# LEF file generated by Abstract Generator version 5.5.12 on Aug 29 14:42:19 2003
#
# Contains LEF for bin IO.
# Options:   [ ] Antenna
#            [x] Geometry
#            [ ] Technology

VERSION 5.4 ;
NAMESCASESENSITIVE ON ;
BUSBITCHARS "[]" ;
DIVIDERCHAR "/" ;
UNITS
  DATABASE MICRONS 1000 ;
END UNITS

USEMINSPACING OBS ON ;
USEMINSPACING PIN OFF ;
CLEARANCEMEASURE EUCLIDEAN ;


MANUFACTURINGGRID 0.001 ;




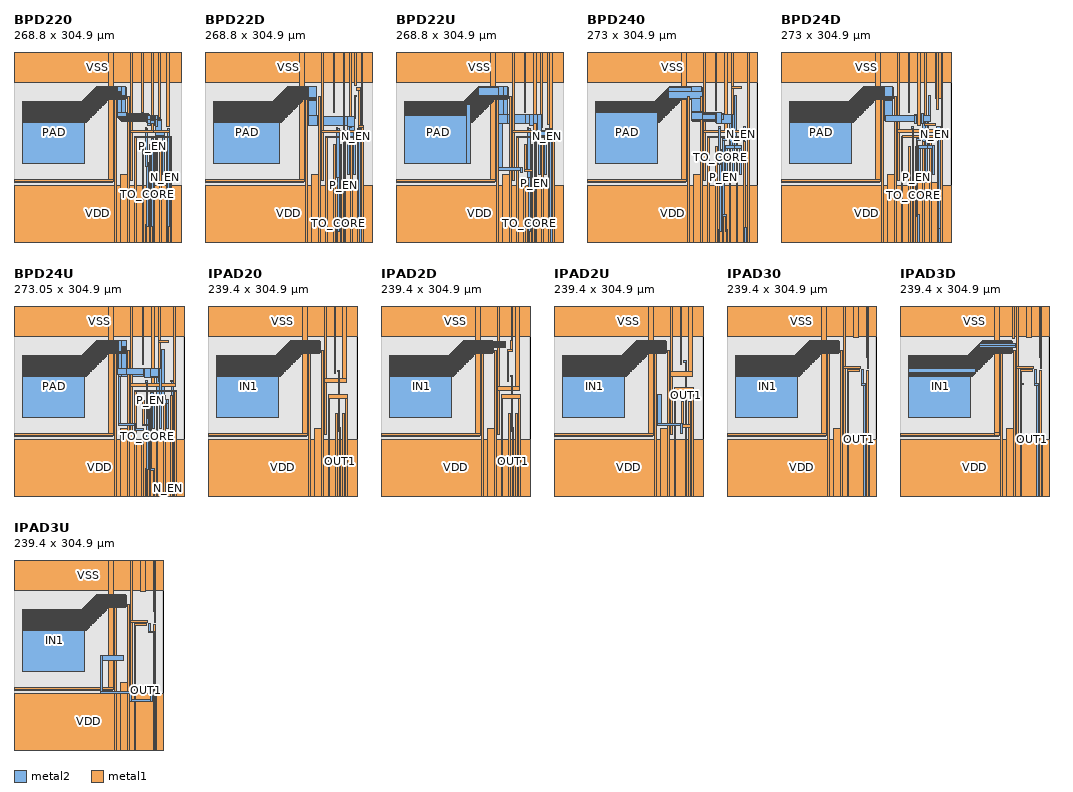
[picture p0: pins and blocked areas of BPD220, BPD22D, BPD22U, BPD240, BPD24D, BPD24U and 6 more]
MACRO BPD220
  CLASS  PAD ;
  FOREIGN BPD220 0.000 0.000 ;
  ORIGIN 0.000 0.000 ;
  SIZE 268.800 BY 304.900 ;
  SYMMETRY X Y R90  ;
  SITE IO ;
  PIN N_EN
    DIRECTION INPUT ;
    PORT
      LAYER metal2 ;
        RECT 244.450 0.000 246.950 27.700 ;
        RECT 246.250 25.200 248.750 182.250 ;
    END
  END N_EN
  PIN TO_CORE
    DIRECTION OUTPUT ;
    PORT
      LAYER metal2 ;
        RECT 211.300 121.300 214.100 181.400 ;
        RECT 212.650 25.200 215.150 128.200 ;
        RECT 210.850 0.000 213.350 27.700 ;
        RECT 210.250 179.000 212.750 183.950 ;
    END
  END TO_CORE
  PIN VSS
    DIRECTION INOUT ;
    USE GROUND ;
    SHAPE ABUTMENT ;
    PORT
      LAYER metal2 ;
        RECT 0.000 256.200 268.800 304.900 ;
      LAYER metal1 ;
        RECT 0.750 95.850 158.334 100.500 ;
        RECT 0.000 256.200 268.800 304.900 ;
        RECT 186.750 175.100 249.900 178.250 ;
        RECT 245.250 184.850 248.800 304.900 ;
        RECT 231.450 183.800 234.950 304.900 ;
        RECT 220.550 175.100 224.250 304.900 ;
        RECT 186.750 175.100 224.250 178.500 ;
        RECT 205.100 208.600 207.600 304.900 ;
        RECT 186.750 99.300 190.950 304.900 ;
        RECT 186.850 99.200 190.850 304.900 ;
        RECT 151.350 97.066 159.550 304.900 ;
        RECT 0.750 96.850 159.334 100.500 ;
    END
  END VSS
  PIN PAD
    DIRECTION INOUT ;
    PORT
      LAYER metal2 ;
        RECT 14.751 125.550 112.998 225.550 ;
        RECT 14.650 125.651 112.998 225.550 ;
        RECT 112.998 229.147 179.547 229.799 ;
        RECT 14.650 126.352 113.800 225.550 ;
        RECT 227.850 170.550 241.800 176.000 ;
        RECT 237.600 107.600 241.800 176.000 ;
        RECT 227.850 170.550 236.350 196.450 ;
        RECT 169.500 196.400 235.800 197.000 ;
        RECT 227.900 107.600 230.800 202.000 ;
        RECT 227.850 107.650 230.800 202.000 ;
        RECT 166.500 199.400 231.800 201.000 ;
        RECT 227.399 185.800 230.150 202.650 ;
        RECT 167.500 198.400 232.800 200.000 ;
        RECT 226.150 186.800 230.150 202.650 ;
        RECT 168.500 197.400 233.800 199.000 ;
        RECT 214.122 190.950 230.150 202.650 ;
        RECT 214.250 190.822 219.500 202.650 ;
        RECT 214.650 186.300 219.500 202.650 ;
        RECT 165.500 200.400 217.650 203.550 ;
        RECT 165.500 200.400 216.650 204.550 ;
        RECT 165.500 200.400 215.650 205.550 ;
        RECT 165.500 200.400 214.650 206.550 ;
        RECT 169.500 196.400 234.800 198.000 ;
        RECT 213.122 191.950 214.250 206.950 ;
        RECT 170.500 195.400 236.350 196.450 ;
        RECT 172.950 192.950 214.250 206.950 ;
        RECT 132.048 229.800 180.200 248.497 ;
        RECT 165.500 200.400 180.200 207.550 ;
        RECT 132.150 229.147 179.547 249.150 ;
        RECT 112.749 228.600 179.200 229.550 ;
        RECT 165.500 200.400 179.200 249.150 ;
        RECT 172.500 193.400 179.200 249.150 ;
        RECT 171.500 194.400 236.350 196.450 ;
        RECT 112.749 228.452 152.150 229.550 ;
        RECT 111.749 227.452 151.150 228.550 ;
        RECT 110.749 226.452 150.150 227.550 ;
        RECT 109.749 225.452 149.150 226.550 ;
        RECT 14.650 224.452 148.150 225.550 ;
        RECT 13.800 223.452 147.150 224.700 ;
        RECT 13.800 222.452 146.150 224.700 ;
        RECT 13.800 221.452 145.150 224.700 ;
        RECT 13.800 220.452 144.150 224.700 ;
        RECT 13.800 219.452 143.150 224.700 ;
        RECT 13.800 218.452 142.150 224.700 ;
        RECT 13.800 217.452 141.150 224.700 ;
        RECT 13.800 216.452 140.150 224.700 ;
        RECT 13.800 215.452 139.150 224.700 ;
        RECT 13.800 214.452 138.150 224.700 ;
        RECT 13.800 213.452 137.150 224.700 ;
        RECT 13.800 212.452 136.150 224.700 ;
        RECT 13.800 211.452 135.150 224.700 ;
        RECT 13.800 210.452 134.150 224.700 ;
        RECT 13.800 209.452 133.150 224.700 ;
        RECT 13.800 208.452 132.150 224.700 ;
        RECT 132.048 229.147 179.547 248.849 ;
        RECT 13.800 208.350 132.048 224.700 ;
        RECT 131.048 229.800 180.200 247.849 ;
        RECT 13.800 207.350 131.048 224.700 ;
        RECT 130.048 229.800 180.200 246.849 ;
        RECT 13.800 206.350 130.048 224.700 ;
        RECT 129.048 229.800 180.200 245.849 ;
        RECT 13.800 205.350 129.048 224.700 ;
        RECT 128.048 229.800 180.200 244.849 ;
        RECT 13.800 204.350 128.048 224.700 ;
        RECT 127.048 229.800 180.200 243.849 ;
        RECT 13.800 203.350 127.048 224.700 ;
        RECT 126.048 229.800 180.200 242.849 ;
        RECT 13.800 202.350 126.048 224.700 ;
        RECT 125.048 229.800 180.200 241.849 ;
        RECT 13.800 201.350 125.048 224.700 ;
        RECT 125.032 229.800 180.200 241.833 ;
        RECT 124.800 229.800 180.200 241.601 ;
        RECT 13.800 201.118 124.800 224.700 ;
        RECT 123.800 229.800 180.200 240.601 ;
        RECT 13.800 200.118 123.800 224.700 ;
        RECT 122.800 229.800 180.200 239.601 ;
        RECT 13.800 199.118 122.800 224.700 ;
        RECT 121.800 229.800 180.200 238.601 ;
        RECT 13.800 198.118 121.800 224.700 ;
        RECT 120.800 229.800 180.200 237.601 ;
        RECT 13.800 197.118 120.800 224.700 ;
        RECT 119.800 229.800 180.200 236.601 ;
        RECT 13.800 196.118 119.800 224.700 ;
        RECT 118.800 229.800 180.200 235.601 ;
        RECT 13.800 195.118 118.800 224.700 ;
        RECT 117.800 229.800 180.200 234.601 ;
        RECT 13.800 194.118 117.800 224.700 ;
        RECT 116.800 229.800 180.200 233.601 ;
        RECT 13.800 193.118 116.800 224.700 ;
        RECT 115.800 229.800 180.200 232.601 ;
        RECT 13.800 192.118 115.800 224.700 ;
        RECT 114.800 229.800 180.200 231.601 ;
        RECT 13.800 191.118 114.800 224.700 ;
        RECT 113.800 229.800 180.200 230.601 ;
        RECT 13.800 126.501 113.800 224.700 ;
    END
  END PAD
  PIN VDD
    DIRECTION INOUT ;
    USE POWER ;
    SHAPE ABUTMENT ;
    PORT
      LAYER metal1 ;
        RECT 161.150 0.000 164.197 233.850 ;
        RECT 0.000 0.000 268.800 90.700 ;
        RECT 250.550 0.000 253.050 169.600 ;
        RECT 245.000 0.000 247.500 161.100 ;
        RECT 233.600 0.000 236.100 161.100 ;
        RECT 222.200 0.000 224.700 161.100 ;
        RECT 216.700 0.000 219.200 155.850 ;
        RECT 205.900 0.000 208.400 155.850 ;
        RECT 193.450 0.000 195.950 169.600 ;
        RECT 182.053 0.000 185.150 233.900 ;
        RECT 182.053 0.000 184.800 234.250 ;
        RECT 181.650 0.000 185.150 233.847 ;
        RECT 170.652 0.000 185.150 108.750 ;
        RECT 170.150 0.000 185.150 108.248 ;
        RECT 161.150 0.000 164.650 233.797 ;
        RECT 161.550 0.000 164.197 234.250 ;
    END
    PORT
      CLASS CORE ;
      LAYER metal1 ;
        RECT 193.450 167.100 253.050 169.600 ;
    END
  END VDD
  PIN P_EN
    DIRECTION INPUT ;
    PORT
      LAYER metal2 ;
        RECT 221.050 25.200 223.550 165.600 ;
        RECT 223.450 0.000 225.950 27.700 ;
        RECT 221.050 163.100 224.000 165.600 ;
    END
  END P_EN
  OBS 
      LAYER metal2 ;
        RECT 0.850 228.500 106.799 253.250 ;
        RECT 167.600 111.198 167.702 192.450 ;
        RECT 167.600 111.700 178.700 190.000 ;
        RECT 167.600 111.700 170.000 190.450 ;
        RECT 167.600 111.700 169.550 191.450 ;
        RECT 167.600 111.700 168.550 192.450 ;
        RECT 183.150 237.200 183.800 253.250 ;
        RECT 188.100 93.650 190.500 96.250 ;
        RECT 193.900 210.500 202.150 253.250 ;
        RECT 165.950 102.550 168.950 108.552 ;
        RECT 198.900 93.650 202.950 190.000 ;
        RECT 165.950 104.750 205.800 108.300 ;
        RECT 166.150 102.450 168.950 108.552 ;
        RECT 166.150 102.350 168.850 108.652 ;
        RECT 0.850 104.850 168.650 108.950 ;
        RECT 0.850 104.850 168.600 109.000 ;
        RECT 0.850 104.850 167.600 109.550 ;
        RECT 0.850 104.850 150.800 110.101 ;
        RECT 0.850 104.850 149.800 122.548 ;
        RECT 0.850 103.450 148.400 122.600 ;
        RECT 115.948 104.850 149.298 123.050 ;
        RECT 115.948 103.450 148.400 123.402 ;
        RECT 198.900 157.900 208.300 164.150 ;
        RECT 198.900 158.800 208.350 164.150 ;
        RECT 198.900 104.750 205.800 190.000 ;
        RECT 195.700 162.150 205.800 190.000 ;
        RECT 193.900 181.450 207.300 190.000 ;
        RECT 193.900 186.900 211.700 187.872 ;
        RECT 193.900 186.900 211.300 188.000 ;
        RECT 116.750 103.450 148.400 188.168 ;
        RECT 193.900 186.900 211.172 189.000 ;
        RECT 117.750 103.450 148.400 189.168 ;
        RECT 193.900 186.900 210.172 190.000 ;
        RECT 118.750 103.450 148.400 190.168 ;
        RECT 119.750 103.450 148.400 191.168 ;
        RECT 120.750 103.450 148.400 192.168 ;
        RECT 121.750 103.450 148.400 193.168 ;
        RECT 122.750 103.450 148.400 194.168 ;
        RECT 123.750 103.450 148.400 195.168 ;
        RECT 124.750 103.450 148.400 196.168 ;
        RECT 125.750 103.450 148.400 197.168 ;
        RECT 126.750 103.450 148.400 198.168 ;
        RECT 127.750 103.450 148.400 198.400 ;
        RECT 127.998 103.450 148.400 199.400 ;
        RECT 128.998 103.450 148.400 200.400 ;
        RECT 129.998 103.450 148.400 201.400 ;
        RECT 130.998 103.450 148.400 202.400 ;
        RECT 131.998 103.450 148.400 203.400 ;
        RECT 132.998 103.450 148.400 204.400 ;
        RECT 133.998 103.450 148.400 205.400 ;
        RECT 134.998 103.450 148.400 205.502 ;
        RECT 135.100 103.450 148.400 206.502 ;
        RECT 136.100 103.450 148.400 207.502 ;
        RECT 137.100 103.450 148.400 208.502 ;
        RECT 138.100 103.450 148.400 209.502 ;
        RECT 139.100 103.450 148.400 210.502 ;
        RECT 140.100 103.450 148.400 211.502 ;
        RECT 141.100 103.450 148.400 212.502 ;
        RECT 142.100 103.450 148.400 213.502 ;
        RECT 143.100 103.450 148.400 214.502 ;
        RECT 144.100 103.450 148.400 215.502 ;
        RECT 145.100 103.450 148.400 216.502 ;
        RECT 146.100 103.450 148.400 217.502 ;
        RECT 147.100 103.450 148.400 218.502 ;
        RECT 148.100 103.450 148.400 219.502 ;
        RECT 210.550 210.500 217.600 253.250 ;
        RECT 220.550 207.800 224.250 253.250 ;
        RECT 227.200 210.500 228.500 253.250 ;
        RECT 227.650 93.650 230.650 104.650 ;
        RECT 231.450 207.800 234.950 253.250 ;
        RECT 239.050 93.650 242.050 104.650 ;
        RECT 237.900 210.500 242.300 253.250 ;
        RECT 251.750 210.500 267.950 253.250 ;
      LAYER metal1 ;
        RECT 0.750 106.650 149.350 249.448 ;
        RECT 0.750 103.250 148.600 253.450 ;
        RECT 166.150 110.250 179.130 135.394 ;
        RECT 166.150 102.350 168.650 135.394 ;
        RECT 166.157 111.270 180.150 135.413 ;
        RECT 166.238 111.270 180.150 135.448 ;
        RECT 166.238 110.468 179.348 135.532 ;
        RECT 166.956 110.468 179.348 136.250 ;
        RECT 166.750 139.250 178.900 253.450 ;
        RECT 167.400 110.250 178.900 253.450 ;
        RECT 166.150 139.850 178.900 253.450 ;
        RECT 166.150 139.906 179.900 253.450 ;
        RECT 166.150 140.156 180.150 253.450 ;
        RECT 162.300 237.000 184.000 253.450 ;
        RECT 187.900 93.450 190.700 96.450 ;
        RECT 193.700 181.250 217.800 205.850 ;
        RECT 205.600 181.250 208.300 206.000 ;
        RECT 193.700 181.250 202.600 212.700 ;
        RECT 193.700 181.250 202.550 231.700 ;
        RECT 193.700 229.200 202.600 231.700 ;
        RECT 210.250 183.800 218.250 249.300 ;
        RECT 210.250 181.250 217.800 250.100 ;
        RECT 193.700 181.250 202.350 253.450 ;
        RECT 210.350 181.250 217.800 253.450 ;
        RECT 198.700 93.450 203.150 164.650 ;
        RECT 198.500 120.950 203.150 164.650 ;
        RECT 198.500 157.900 208.300 164.650 ;
        RECT 211.150 93.450 213.950 164.350 ;
        RECT 210.350 157.650 213.950 164.350 ;
        RECT 198.500 158.600 219.450 164.350 ;
        RECT 227.450 93.450 230.850 164.350 ;
        RECT 238.850 93.450 242.250 164.350 ;
        RECT 198.500 163.850 247.800 164.350 ;
        RECT 198.500 158.600 212.850 164.650 ;
        RECT 221.500 163.100 227.500 165.600 ;
        RECT 227.000 181.250 268.050 182.100 ;
        RECT 230.000 179.750 248.750 182.250 ;
        RECT 227.000 181.250 248.750 182.250 ;
        RECT 226.550 183.800 229.050 249.300 ;
        RECT 227.000 181.250 228.700 253.450 ;
        RECT 237.700 179.750 242.500 253.450 ;
        RECT 251.550 181.250 268.050 253.450 ;
        RECT 255.800 93.450 268.050 164.350 ;
      LAYER via1 ;
        RECT 0.750 0.750 268.050 304.150 ;
  END 
END BPD220


MACRO BPD22D
  CLASS  PAD ;
  FOREIGN BPD22D 0.000 0.000 ;
  ORIGIN 0.000 0.000 ;
  SIZE 268.800 BY 304.900 ;
  SYMMETRY X Y R90  ;
  SITE IO ;
  PIN N_EN
    DIRECTION INPUT ;
    PORT
      LAYER metal2 ;
        RECT 246.750 29.400 249.250 182.250 ;
        RECT 248.650 0.000 251.150 31.900 ;
        RECT 244.000 179.750 249.250 182.250 ;
    END
  END N_EN
  PIN TO_CORE
    DIRECTION OUTPUT ;
    PORT
      LAYER metal2 ;
        RECT 211.800 104.100 215.650 181.400 ;
        RECT 213.150 16.800 215.650 181.400 ;
        RECT 210.850 0.000 213.350 19.300 ;
        RECT 210.750 179.000 213.250 183.950 ;
    END
  END TO_CORE
  PIN VSS
    DIRECTION INOUT ;
    USE GROUND ;
    SHAPE ABUTMENT ;
    PORT
      LAYER metal2 ;
        RECT 0.000 256.200 268.800 304.900 ;
      LAYER metal1 ;
        RECT 0.750 95.850 158.334 100.500 ;
        RECT 0.000 256.200 268.800 304.900 ;
        RECT 250.600 188.000 253.450 304.900 ;
        RECT 186.750 175.100 244.600 178.150 ;
        RECT 240.000 250.650 242.600 304.900 ;
        RECT 232.350 183.800 235.100 304.900 ;
        RECT 221.550 175.100 224.300 304.900 ;
        RECT 186.750 175.100 224.300 178.600 ;
        RECT 205.600 208.600 208.100 304.900 ;
        RECT 186.750 99.300 190.950 304.900 ;
        RECT 186.850 99.200 190.850 304.900 ;
        RECT 151.350 97.066 159.550 304.900 ;
        RECT 0.750 96.850 159.334 100.500 ;
    END
  END VSS
  PIN PAD
    DIRECTION INOUT ;
    PORT
      LAYER metal2 ;
        RECT 113.749 228.600 179.700 230.550 ;
        RECT 114.749 228.600 179.700 231.550 ;
        RECT 115.749 228.600 179.700 232.550 ;
        RECT 116.749 228.600 179.700 233.550 ;
        RECT 117.749 228.600 179.700 234.550 ;
        RECT 239.800 232.950 243.350 235.450 ;
        RECT 239.800 197.950 242.300 235.450 ;
        RECT 238.700 107.600 242.300 174.800 ;
        RECT 167.700 186.651 240.200 202.150 ;
        RECT 168.001 186.350 240.200 202.150 ;
        RECT 228.350 169.450 240.200 202.150 ;
        RECT 228.350 107.650 232.050 202.150 ;
        RECT 228.400 107.600 232.050 202.150 ;
        RECT 227.999 185.350 240.200 202.150 ;
        RECT 166.700 187.651 181.700 202.551 ;
        RECT 166.700 187.651 180.700 203.551 ;
        RECT 132.150 228.600 179.700 249.150 ;
        RECT 165.149 227.600 179.700 249.150 ;
        RECT 166.149 226.600 179.700 249.150 ;
        RECT 166.700 187.651 179.700 249.150 ;
        RECT 112.749 227.952 158.150 229.550 ;
        RECT 111.749 226.952 157.150 228.550 ;
        RECT 110.749 225.952 156.150 227.550 ;
        RECT 109.749 224.952 155.150 226.550 ;
        RECT 14.650 223.952 154.150 225.550 ;
        RECT 13.800 222.952 153.150 224.700 ;
        RECT 13.800 221.952 152.150 224.700 ;
        RECT 13.800 220.952 151.150 224.700 ;
        RECT 13.800 219.952 150.150 224.700 ;
        RECT 13.800 218.952 149.150 224.700 ;
        RECT 13.800 217.952 148.150 224.700 ;
        RECT 13.800 216.952 147.150 224.700 ;
        RECT 13.800 215.952 146.150 224.700 ;
        RECT 13.800 214.952 145.150 224.700 ;
        RECT 13.800 213.952 144.150 224.700 ;
        RECT 13.800 212.952 143.150 224.700 ;
        RECT 13.800 211.952 142.150 224.700 ;
        RECT 13.800 210.952 141.150 224.700 ;
        RECT 13.800 209.952 140.150 224.700 ;
        RECT 13.800 208.952 139.150 224.700 ;
        RECT 13.800 207.952 138.150 224.700 ;
        RECT 13.800 206.952 137.150 224.700 ;
        RECT 13.800 205.952 136.150 224.700 ;
        RECT 13.800 204.952 135.150 224.700 ;
        RECT 13.800 203.952 134.150 224.700 ;
        RECT 13.800 202.952 133.150 224.700 ;
        RECT 13.800 201.952 132.150 224.700 ;
        RECT 131.548 228.600 179.700 248.349 ;
        RECT 13.800 201.350 131.548 224.700 ;
        RECT 131.532 228.600 179.700 248.333 ;
        RECT 131.300 228.600 179.700 248.101 ;
        RECT 13.800 201.118 131.300 224.700 ;
        RECT 130.300 228.600 179.700 247.101 ;
        RECT 13.800 200.118 130.300 224.700 ;
        RECT 129.300 228.600 179.700 246.101 ;
        RECT 13.800 199.118 129.300 224.700 ;
        RECT 128.300 228.600 179.700 245.101 ;
        RECT 13.800 198.118 128.300 224.700 ;
        RECT 127.300 228.600 179.700 244.101 ;
        RECT 13.800 197.118 127.300 224.700 ;
        RECT 126.300 228.600 179.700 243.101 ;
        RECT 13.800 196.118 126.300 224.700 ;
        RECT 125.300 228.600 179.700 242.101 ;
        RECT 13.800 195.118 125.300 224.700 ;
        RECT 124.300 228.600 179.700 241.101 ;
        RECT 13.800 194.118 124.300 224.700 ;
        RECT 123.300 228.600 179.700 240.101 ;
        RECT 13.800 193.118 123.300 224.700 ;
        RECT 122.300 228.600 179.700 239.101 ;
        RECT 13.800 192.118 122.300 224.700 ;
        RECT 121.300 228.600 179.700 238.101 ;
        RECT 13.800 191.118 121.300 224.700 ;
        RECT 120.300 228.600 179.700 237.101 ;
        RECT 13.800 126.501 120.300 224.700 ;
        RECT 14.650 126.352 120.300 225.550 ;
        RECT 119.498 228.600 179.700 236.299 ;
        RECT 14.650 125.651 119.498 225.550 ;
        RECT 14.751 125.550 119.498 225.550 ;
        RECT 118.749 228.600 179.700 235.550 ;
    END
  END PAD
  PIN VDD
    DIRECTION INOUT ;
    USE POWER ;
    SHAPE ABUTMENT ;
    PORT
      LAYER metal1 ;
        RECT 161.150 0.000 164.197 233.850 ;
        RECT 0.000 0.000 268.800 90.700 ;
        RECT 246.350 183.750 253.550 186.300 ;
        RECT 251.050 0.000 253.550 186.300 ;
        RECT 193.950 167.100 253.550 169.600 ;
        RECT 246.350 183.750 248.850 248.550 ;
        RECT 245.500 0.000 248.000 161.100 ;
        RECT 234.100 0.000 236.600 161.100 ;
        RECT 222.700 0.000 225.200 161.100 ;
        RECT 217.200 0.000 219.700 155.850 ;
        RECT 206.400 0.000 208.900 155.850 ;
        RECT 193.950 0.000 196.450 169.600 ;
        RECT 182.053 0.000 185.150 233.900 ;
        RECT 182.053 0.000 184.800 234.250 ;
        RECT 181.650 0.000 185.150 233.847 ;
        RECT 170.652 0.000 185.150 108.750 ;
        RECT 170.150 0.000 185.150 108.248 ;
        RECT 161.150 0.000 164.650 233.797 ;
        RECT 161.550 0.000 164.197 234.250 ;
    END
    PORT
      CLASS CORE ;
      LAYER metal1 ;
        RECT 242.500 243.050 248.850 248.550 ;
    END
  END VDD
  PIN P_EN
    DIRECTION INPUT ;
    PORT
      LAYER metal2 ;
        RECT 221.550 16.800 224.050 165.600 ;
        RECT 223.450 0.000 225.950 19.300 ;
        RECT 221.550 163.100 224.500 165.600 ;
    END
  END P_EN
  OBS 
      LAYER metal2 ;
        RECT 0.850 228.500 106.799 253.250 ;
        RECT 182.650 237.200 183.800 253.250 ;
        RECT 188.100 93.650 191.000 96.250 ;
        RECT 193.900 206.501 202.650 253.250 ;
        RECT 151.302 101.150 155.250 109.550 ;
        RECT 150.800 101.652 155.250 109.550 ;
        RECT 165.950 102.550 170.150 108.950 ;
        RECT 150.800 101.750 155.850 109.550 ;
        RECT 165.950 104.750 191.150 108.300 ;
        RECT 166.150 102.350 170.150 108.950 ;
        RECT 0.850 104.850 169.550 109.550 ;
        RECT 0.850 104.850 151.302 109.599 ;
        RECT 0.850 104.850 150.800 110.101 ;
        RECT 167.600 102.350 167.702 183.400 ;
        RECT 0.850 104.850 149.800 122.548 ;
        RECT 0.850 103.450 148.400 122.600 ;
        RECT 122.448 104.850 149.298 123.050 ;
        RECT 122.448 103.450 148.400 123.402 ;
        RECT 188.650 104.750 191.150 160.400 ;
        RECT 199.400 93.650 203.450 174.100 ;
        RECT 188.650 157.900 208.800 160.400 ;
        RECT 199.400 158.800 208.850 164.150 ;
        RECT 196.200 162.150 208.400 174.100 ;
        RECT 196.200 162.150 203.100 183.400 ;
        RECT 167.600 111.700 178.700 183.400 ;
        RECT 193.900 181.550 207.800 183.400 ;
        RECT 196.200 162.150 198.700 184.350 ;
        RECT 200.600 93.650 203.100 184.450 ;
        RECT 123.250 103.450 148.400 188.168 ;
        RECT 124.250 103.450 148.400 189.168 ;
        RECT 125.250 103.450 148.400 190.168 ;
        RECT 126.250 103.450 148.400 191.168 ;
        RECT 127.250 103.450 148.400 192.168 ;
        RECT 128.250 103.450 148.400 193.168 ;
        RECT 129.250 103.450 148.400 194.168 ;
        RECT 130.250 103.450 148.400 195.168 ;
        RECT 131.250 103.450 148.400 196.168 ;
        RECT 132.250 103.450 148.400 197.168 ;
        RECT 133.250 103.450 148.400 198.168 ;
        RECT 134.250 103.450 148.400 198.400 ;
        RECT 134.498 103.450 148.400 199.002 ;
        RECT 135.100 103.450 148.400 200.002 ;
        RECT 136.100 103.450 148.400 201.002 ;
        RECT 137.100 103.450 148.400 202.002 ;
        RECT 138.100 103.450 148.400 203.002 ;
        RECT 139.100 103.450 148.400 204.002 ;
        RECT 140.100 103.450 148.400 205.002 ;
        RECT 141.100 103.450 148.400 206.002 ;
        RECT 142.100 103.450 148.400 207.002 ;
        RECT 143.100 103.450 148.400 208.002 ;
        RECT 144.100 103.450 148.400 209.002 ;
        RECT 145.100 103.450 148.400 210.002 ;
        RECT 146.100 103.450 148.400 211.002 ;
        RECT 147.100 103.450 148.400 212.002 ;
        RECT 148.100 103.450 148.400 213.002 ;
        RECT 211.050 206.501 218.600 253.250 ;
        RECT 221.550 207.800 224.300 253.250 ;
        RECT 227.250 206.501 229.400 253.250 ;
        RECT 228.150 93.650 231.150 101.150 ;
        RECT 232.350 207.800 235.100 253.250 ;
        RECT 239.550 93.650 242.550 101.150 ;
        RECT 238.050 238.400 243.400 240.100 ;
        RECT 238.050 238.400 239.550 247.700 ;
        RECT 245.550 251.500 247.650 253.250 ;
        RECT 256.400 251.500 267.950 253.250 ;
      LAYER metal1 ;
        RECT 0.750 106.650 149.350 249.448 ;
        RECT 0.750 103.250 148.600 253.450 ;
        RECT 166.150 110.250 179.130 135.394 ;
        RECT 166.150 102.350 168.650 135.394 ;
        RECT 166.157 111.270 180.150 135.413 ;
        RECT 166.238 111.270 180.150 135.448 ;
        RECT 166.238 110.468 179.348 135.532 ;
        RECT 166.956 110.468 179.348 136.250 ;
        RECT 166.750 139.250 178.900 253.450 ;
        RECT 167.400 110.250 178.900 253.450 ;
        RECT 166.150 139.850 178.900 253.450 ;
        RECT 166.150 139.906 179.900 253.450 ;
        RECT 166.150 140.156 180.150 253.450 ;
        RECT 162.300 237.000 184.000 253.450 ;
        RECT 187.900 93.450 191.200 96.450 ;
        RECT 193.700 181.350 218.800 205.850 ;
        RECT 193.700 181.350 203.100 212.700 ;
        RECT 193.700 181.350 203.050 231.700 ;
        RECT 193.700 229.200 203.100 231.700 ;
        RECT 210.750 181.350 218.800 253.150 ;
        RECT 193.700 181.350 202.850 253.450 ;
        RECT 210.850 181.350 218.800 253.450 ;
        RECT 198.200 181.350 200.700 254.200 ;
        RECT 230.500 179.750 246.500 182.250 ;
        RECT 227.050 181.350 246.500 182.250 ;
        RECT 237.850 179.750 243.600 240.300 ;
        RECT 237.850 179.750 243.350 241.550 ;
        RECT 237.850 179.750 239.750 247.900 ;
        RECT 227.050 181.350 229.600 253.450 ;
        RECT 245.350 251.300 247.850 253.450 ;
        RECT 199.200 93.450 203.650 164.650 ;
        RECT 199.000 120.950 203.650 164.650 ;
        RECT 199.000 157.900 208.800 164.650 ;
        RECT 211.650 93.450 214.450 164.350 ;
        RECT 210.850 157.650 214.450 164.350 ;
        RECT 199.000 158.600 219.950 164.350 ;
        RECT 227.950 93.450 231.350 164.350 ;
        RECT 239.350 93.450 242.750 164.350 ;
        RECT 199.000 163.850 248.300 164.350 ;
        RECT 199.000 158.600 213.350 164.650 ;
        RECT 222.000 163.100 228.000 165.600 ;
        RECT 256.200 251.300 268.050 253.450 ;
        RECT 256.300 93.450 268.050 164.350 ;
      LAYER via1 ;
        RECT 0.750 0.750 268.050 304.150 ;
  END 
END BPD22D

MACRO BPD22U
  CLASS  PAD ;
  FOREIGN BPD22U 0.000 0.000 ;
  ORIGIN 0.000 0.000 ;
  SIZE 268.800 BY 304.900 ;
  SYMMETRY X Y R90  ;
  SITE IO ;
  PIN N_EN
    DIRECTION INPUT ;
    PORT
      LAYER metal2 ;
        RECT 246.700 25.200 249.200 182.250 ;
        RECT 248.650 0.000 251.150 27.700 ;
        RECT 240.250 179.750 249.200 182.250 ;
    END
  END N_EN
  PIN TO_CORE
    DIRECTION OUTPUT ;
    PORT
      LAYER metal2 ;
        RECT 211.750 104.100 215.600 181.400 ;
        RECT 213.100 16.800 215.600 181.400 ;
        RECT 210.850 0.000 213.350 19.300 ;
        RECT 210.700 179.000 213.200 183.950 ;
    END
  END TO_CORE
  PIN VSS
    DIRECTION INOUT ;
    USE GROUND ;
    SHAPE ABUTMENT ;
    PORT
      LAYER metal2 ;
        RECT 0.000 256.200 268.800 304.900 ;
      LAYER metal1 ;
        RECT 0.750 95.850 158.334 100.500 ;
        RECT 0.000 256.200 268.800 304.900 ;
        RECT 243.700 188.200 250.800 304.900 ;
        RECT 245.850 175.100 250.800 304.900 ;
        RECT 207.000 175.100 250.800 178.250 ;
        RECT 231.900 183.800 235.400 304.900 ;
        RECT 221.000 175.100 224.700 304.900 ;
        RECT 186.750 175.150 224.700 178.500 ;
        RECT 205.550 208.600 208.050 304.900 ;
        RECT 186.750 99.300 190.950 304.900 ;
        RECT 186.850 99.200 190.850 304.900 ;
        RECT 151.350 97.066 159.550 304.900 ;
        RECT 0.750 96.850 159.334 100.500 ;
    END
  END VSS
  PIN PAD
    DIRECTION INOUT ;
    PORT
      LAYER metal2 ;
        RECT 238.050 107.600 242.250 178.050 ;
        RECT 228.300 170.750 242.250 178.050 ;
        RECT 228.350 107.600 232.100 158.100 ;
        RECT 228.300 107.650 232.050 204.300 ;
        RECT 208.004 189.800 233.900 204.300 ;
        RECT 226.550 170.800 233.900 204.300 ;
        RECT 165.100 190.650 227.450 204.350 ;
        RECT 214.700 186.800 220.300 204.350 ;
        RECT 165.100 114.750 202.950 120.300 ;
        RECT 200.400 111.750 202.950 120.300 ;
        RECT 132.150 229.650 180.200 248.497 ;
        RECT 132.150 228.997 179.547 249.150 ;
        RECT 165.100 190.650 179.300 204.554 ;
        RECT 112.749 228.600 179.150 229.550 ;
        RECT 165.100 190.650 178.300 249.150 ;
        RECT 165.100 190.043 172.600 249.150 ;
        RECT 165.100 114.750 171.600 249.150 ;
        RECT 112.749 228.002 158.150 229.550 ;
        RECT 111.749 227.002 157.150 228.550 ;
        RECT 110.749 226.002 156.150 227.550 ;
        RECT 109.749 225.002 155.150 226.550 ;
        RECT 14.650 224.002 154.150 225.550 ;
        RECT 13.800 223.002 153.150 224.700 ;
        RECT 13.800 222.002 152.150 224.700 ;
        RECT 13.800 221.002 151.150 224.700 ;
        RECT 13.800 220.002 150.150 224.700 ;
        RECT 13.800 219.002 149.150 224.700 ;
        RECT 13.800 218.002 148.150 224.700 ;
        RECT 13.800 217.002 147.150 224.700 ;
        RECT 13.800 216.002 146.150 224.700 ;
        RECT 13.800 215.002 145.150 224.700 ;
        RECT 13.800 214.002 144.150 224.700 ;
        RECT 13.800 213.002 143.150 224.700 ;
        RECT 13.800 212.002 142.150 224.700 ;
        RECT 13.800 211.002 141.150 224.700 ;
        RECT 13.800 210.002 140.150 224.700 ;
        RECT 13.800 209.002 139.150 224.700 ;
        RECT 13.800 208.002 138.150 224.700 ;
        RECT 13.800 207.002 137.150 224.700 ;
        RECT 13.800 206.002 136.150 224.700 ;
        RECT 13.800 205.002 135.150 224.700 ;
        RECT 13.800 204.002 134.150 224.700 ;
        RECT 13.800 203.002 133.150 224.700 ;
        RECT 131.498 202.002 132.150 248.299 ;
        RECT 131.482 229.650 180.200 248.283 ;
        RECT 131.250 201.350 131.498 248.051 ;
        RECT 130.250 201.118 131.250 247.051 ;
        RECT 129.250 200.118 130.250 246.051 ;
        RECT 128.250 199.118 129.250 245.051 ;
        RECT 127.250 198.118 128.250 244.051 ;
        RECT 126.250 197.118 127.250 243.051 ;
        RECT 125.250 196.118 126.250 242.051 ;
        RECT 124.250 195.118 125.250 241.051 ;
        RECT 123.250 194.118 124.250 240.051 ;
        RECT 122.250 193.118 123.250 239.051 ;
        RECT 121.250 192.118 122.250 238.051 ;
        RECT 120.250 191.118 121.250 237.051 ;
        RECT 13.800 126.501 120.250 224.700 ;
        RECT 119.448 126.352 120.250 236.249 ;
        RECT 14.650 125.651 119.448 225.550 ;
        RECT 14.751 125.550 119.448 225.550 ;
        RECT 118.749 229.650 180.200 235.550 ;
        RECT 117.749 229.650 180.200 234.550 ;
        RECT 116.749 229.650 180.200 233.550 ;
        RECT 115.749 229.650 180.200 232.550 ;
        RECT 114.749 229.650 180.200 231.550 ;
        RECT 113.749 125.550 119.448 230.550 ;
    END
  END PAD
  PIN VDD
    DIRECTION INOUT ;
    USE POWER ;
    SHAPE ABUTMENT ;
    PORT
      LAYER metal1 ;
        RECT 161.150 0.000 164.197 233.850 ;
        RECT 0.000 0.000 268.800 90.700 ;
        RECT 251.000 0.000 254.150 169.600 ;
        RECT 245.450 0.000 247.950 161.100 ;
        RECT 234.050 0.000 236.550 161.100 ;
        RECT 222.650 0.000 225.150 161.100 ;
        RECT 217.100 0.000 219.650 155.850 ;
        RECT 206.350 113.550 219.650 116.700 ;
        RECT 214.700 0.000 219.650 116.700 ;
        RECT 206.350 113.550 208.850 155.850 ;
        RECT 205.000 0.000 207.500 94.950 ;
        RECT 193.900 0.000 196.400 169.600 ;
        RECT 182.053 0.000 185.150 233.900 ;
        RECT 182.053 0.000 184.800 234.250 ;
        RECT 181.650 0.000 185.150 233.847 ;
        RECT 170.652 0.000 185.150 108.750 ;
        RECT 170.150 0.000 185.150 108.248 ;
        RECT 161.150 0.000 164.650 233.797 ;
        RECT 161.550 0.000 164.197 234.250 ;
    END
    PORT
      CLASS CORE ;
      LAYER metal1 ;
        RECT 193.900 167.100 254.150 169.600 ;
    END
  END VDD
  PIN P_EN
    DIRECTION INPUT ;
    PORT
      LAYER metal2 ;
        RECT 221.500 21.000 224.000 165.600 ;
        RECT 223.450 0.000 225.950 23.500 ;
        RECT 221.500 163.100 224.450 165.600 ;
    END
  END P_EN
  OBS 
      LAYER metal2 ;
        RECT 0.850 228.500 106.799 253.250 ;
        RECT 166.150 102.350 168.650 108.950 ;
        RECT 0.850 104.850 168.600 109.000 ;
        RECT 0.850 104.850 167.600 109.550 ;
        RECT 0.850 104.850 149.800 121.300 ;
        RECT 0.850 104.850 149.400 121.700 ;
        RECT 0.850 103.450 148.400 122.600 ;
        RECT 122.398 103.450 148.400 123.402 ;
        RECT 123.200 103.450 148.400 188.168 ;
        RECT 124.200 103.450 148.400 189.168 ;
        RECT 125.200 103.450 148.400 190.168 ;
        RECT 126.200 103.450 148.400 191.168 ;
        RECT 127.200 103.450 148.400 192.168 ;
        RECT 128.200 103.450 148.400 193.168 ;
        RECT 129.200 103.450 148.400 194.168 ;
        RECT 130.200 103.450 148.400 195.168 ;
        RECT 131.200 103.450 148.400 196.168 ;
        RECT 132.200 103.450 148.400 197.168 ;
        RECT 133.200 103.450 148.400 198.168 ;
        RECT 134.200 103.450 148.400 198.400 ;
        RECT 134.448 103.450 148.400 199.052 ;
        RECT 135.100 103.450 148.400 200.052 ;
        RECT 136.100 103.450 148.400 201.052 ;
        RECT 137.100 103.450 148.400 202.052 ;
        RECT 138.100 103.450 148.400 203.052 ;
        RECT 139.100 103.450 148.400 204.052 ;
        RECT 140.100 103.450 148.400 205.052 ;
        RECT 141.100 103.450 148.400 206.052 ;
        RECT 142.100 103.450 148.400 207.052 ;
        RECT 143.100 103.450 148.400 208.052 ;
        RECT 144.100 103.450 148.400 209.052 ;
        RECT 145.100 103.450 148.400 210.052 ;
        RECT 146.100 103.450 148.400 211.052 ;
        RECT 147.100 103.450 148.400 212.052 ;
        RECT 148.100 103.450 148.400 213.052 ;
        RECT 167.600 111.198 167.702 111.800 ;
        RECT 167.600 111.700 178.700 111.800 ;
        RECT 183.150 237.200 183.800 253.250 ;
        RECT 193.900 207.504 202.600 253.250 ;
        RECT 174.550 124.850 179.150 135.350 ;
        RECT 199.350 123.250 203.400 174.100 ;
        RECT 174.550 132.450 205.700 135.350 ;
        RECT 199.350 132.450 205.700 174.100 ;
        RECT 199.350 157.900 208.750 164.150 ;
        RECT 199.350 158.800 208.800 164.150 ;
        RECT 196.150 162.150 208.350 174.100 ;
        RECT 196.150 162.150 203.050 187.700 ;
        RECT 193.900 181.450 207.750 186.850 ;
        RECT 174.550 123.250 178.700 187.093 ;
        RECT 175.550 123.250 178.700 187.700 ;
        RECT 193.900 181.450 205.054 187.700 ;
        RECT 200.550 123.250 203.050 188.300 ;
        RECT 199.350 93.650 202.050 108.800 ;
        RECT 186.750 96.850 202.050 99.350 ;
        RECT 199.350 97.900 210.150 101.150 ;
        RECT 188.100 93.650 190.950 108.350 ;
        RECT 186.750 96.850 190.950 108.350 ;
        RECT 187.750 96.850 190.750 108.550 ;
        RECT 199.350 97.900 208.800 108.800 ;
        RECT 187.750 96.850 189.750 109.350 ;
        RECT 187.950 96.850 189.750 109.550 ;
        RECT 211.000 207.504 218.050 253.250 ;
        RECT 221.000 207.800 224.700 253.250 ;
        RECT 227.650 207.504 228.950 253.250 ;
        RECT 228.100 93.650 231.100 101.150 ;
        RECT 231.900 207.800 235.400 253.250 ;
        RECT 238.350 207.504 240.750 253.250 ;
        RECT 239.500 93.650 242.500 101.150 ;
        RECT 253.750 207.504 267.950 253.250 ;
      LAYER metal1 ;
        RECT 0.750 106.650 149.350 249.448 ;
        RECT 0.750 103.250 148.600 253.450 ;
        RECT 166.150 110.250 179.130 135.394 ;
        RECT 166.150 102.350 168.650 135.394 ;
        RECT 166.157 111.270 180.150 135.413 ;
        RECT 166.238 111.270 180.150 135.448 ;
        RECT 166.238 110.468 179.348 135.532 ;
        RECT 166.956 110.468 179.348 136.250 ;
        RECT 166.750 139.250 178.900 253.450 ;
        RECT 167.400 110.250 178.900 253.450 ;
        RECT 166.150 139.850 178.900 253.450 ;
        RECT 166.150 139.906 179.900 253.450 ;
        RECT 166.150 140.156 180.150 253.450 ;
        RECT 162.300 237.000 184.000 253.450 ;
        RECT 187.900 93.450 191.150 96.450 ;
        RECT 193.700 172.350 204.250 172.400 ;
        RECT 211.750 121.350 214.250 155.050 ;
        RECT 196.150 181.200 208.700 205.850 ;
        RECT 193.700 181.250 218.250 205.850 ;
        RECT 193.700 181.250 203.050 212.700 ;
        RECT 193.700 181.250 203.000 231.700 ;
        RECT 193.700 229.200 203.050 231.700 ;
        RECT 210.700 183.800 218.700 249.300 ;
        RECT 210.700 181.250 218.250 250.100 ;
        RECT 193.700 181.250 202.800 253.450 ;
        RECT 210.800 181.250 218.250 253.450 ;
        RECT 230.400 179.750 243.200 182.250 ;
        RECT 227.450 181.250 243.200 182.250 ;
        RECT 238.150 179.750 243.100 185.450 ;
        RECT 227.000 183.800 229.500 249.300 ;
        RECT 227.450 181.250 229.150 253.450 ;
        RECT 238.150 179.750 240.950 253.450 ;
        RECT 199.150 93.450 202.250 164.650 ;
        RECT 199.000 96.850 204.900 99.350 ;
        RECT 210.250 93.450 211.950 110.800 ;
        RECT 199.150 97.700 211.950 110.800 ;
        RECT 227.900 93.450 231.300 110.800 ;
        RECT 239.300 93.450 242.700 110.800 ;
        RECT 199.150 97.700 207.550 110.900 ;
        RECT 199.150 96.850 203.600 164.650 ;
        RECT 198.950 120.950 203.600 164.650 ;
        RECT 198.950 157.900 208.750 164.650 ;
        RECT 228.350 93.450 230.850 164.350 ;
        RECT 239.750 93.450 242.250 164.350 ;
        RECT 198.950 158.600 219.900 164.350 ;
        RECT 227.900 158.600 231.300 164.350 ;
        RECT 239.300 158.600 242.700 164.350 ;
        RECT 198.950 163.850 248.250 164.350 ;
        RECT 210.800 157.650 213.300 164.650 ;
        RECT 198.950 158.600 213.300 164.650 ;
        RECT 221.950 163.100 227.950 165.600 ;
        RECT 253.550 181.250 268.050 253.450 ;
        RECT 256.900 158.600 268.050 164.350 ;
        RECT 256.900 93.450 268.050 110.800 ;
      LAYER via1 ;
        RECT 0.750 0.750 268.050 304.150 ;
  END 
END BPD22U

MACRO BPD240
  CLASS  PAD ;
  FOREIGN BPD240 0.000 0.000 ;
  ORIGIN 0.000 0.000 ;
  SIZE 273.000 BY 304.900 ;
  SYMMETRY X Y R90  ;
  SITE IO ;
  PIN N_EN
    DIRECTION INPUT ;
    PORT
      LAYER metal2 ;
        RECT 250.900 21.000 253.400 184.900 ;
        RECT 252.850 0.000 255.350 23.500 ;
        RECT 250.900 182.400 253.800 184.900 ;
    END
  END N_EN
  PIN TO_CORE
    DIRECTION OUTPUT ;
    PORT
      LAYER metal2 ;
        RECT 211.750 123.600 214.250 184.800 ;
        RECT 213.100 16.800 215.600 149.200 ;
        RECT 210.700 182.300 214.250 184.800 ;
        RECT 210.850 0.000 213.350 19.300 ;
    END
  END TO_CORE
  PIN VSS
    DIRECTION INOUT ;
    USE GROUND ;
    SHAPE ABUTMENT ;
    PORT
      LAYER metal2 ;
        RECT 0.000 256.200 273.000 304.900 ;
      LAYER metal1 ;
        RECT 0.750 95.850 158.334 100.500 ;
        RECT 0.000 256.200 273.000 304.900 ;
        RECT 257.100 178.700 260.550 304.900 ;
        RECT 186.750 175.200 260.500 178.700 ;
        RECT 231.900 246.900 248.250 249.400 ;
        RECT 231.900 183.800 235.400 304.900 ;
        RECT 221.000 175.200 224.700 304.900 ;
        RECT 205.550 211.400 208.050 304.900 ;
        RECT 186.750 99.300 190.950 304.900 ;
        RECT 186.850 99.200 190.850 304.900 ;
        RECT 151.350 97.066 159.550 304.900 ;
        RECT 0.750 96.850 159.334 100.500 ;
    END
  END VSS
  PIN PAD
    DIRECTION INOUT ;
    PORT
      LAYER metal2 ;
        RECT 228.300 149.400 247.950 155.500 ;
        RECT 245.050 107.600 247.950 155.500 ;
        RECT 237.300 149.400 240.700 234.300 ;
        RECT 228.300 149.400 240.700 204.300 ;
        RECT 222.650 149.300 237.000 155.100 ;
        RECT 233.700 107.600 237.000 204.300 ;
        RECT 168.100 195.103 240.700 204.300 ;
        RECT 208.300 189.800 240.700 204.300 ;
        RECT 222.650 107.600 225.650 155.100 ;
        RECT 167.100 196.103 219.300 204.600 ;
        RECT 167.100 196.103 218.300 205.600 ;
        RECT 167.100 196.103 217.300 206.600 ;
        RECT 167.100 196.103 216.300 207.600 ;
        RECT 169.100 194.103 240.700 204.300 ;
        RECT 207.700 190.400 216.300 207.600 ;
        RECT 170.100 193.103 240.700 204.300 ;
        RECT 206.700 191.400 216.300 207.600 ;
        RECT 170.603 192.600 240.700 204.300 ;
        RECT 205.700 192.400 216.300 207.600 ;
        RECT 167.100 196.103 185.400 208.404 ;
        RECT 131.048 229.850 184.550 247.650 ;
        RECT 131.048 229.700 184.400 247.800 ;
        RECT 167.100 196.103 184.400 209.404 ;
        RECT 132.150 228.600 183.050 249.150 ;
        RECT 167.100 196.103 183.400 248.800 ;
        RECT 112.749 228.452 152.150 229.550 ;
        RECT 111.749 227.452 151.150 228.550 ;
        RECT 110.749 226.452 150.150 227.550 ;
        RECT 109.749 225.452 149.150 226.550 ;
        RECT 14.650 224.452 148.150 225.550 ;
        RECT 13.800 223.452 147.150 224.700 ;
        RECT 13.800 222.452 146.150 224.700 ;
        RECT 13.800 221.452 145.150 224.700 ;
        RECT 13.800 220.452 144.150 224.700 ;
        RECT 13.800 219.452 143.150 224.700 ;
        RECT 13.800 218.452 142.150 224.700 ;
        RECT 13.800 217.452 141.150 224.700 ;
        RECT 13.800 216.452 140.150 224.700 ;
        RECT 13.800 215.452 139.150 224.700 ;
        RECT 13.800 214.452 138.150 224.700 ;
        RECT 13.800 213.452 137.150 224.700 ;
        RECT 13.800 212.452 136.150 224.700 ;
        RECT 13.800 211.452 135.150 224.700 ;
        RECT 13.800 210.452 134.150 224.700 ;
        RECT 13.800 209.452 133.150 224.700 ;
        RECT 13.800 208.452 132.150 224.700 ;
        RECT 132.048 228.600 183.050 248.849 ;
        RECT 13.800 208.350 132.048 224.700 ;
        RECT 131.048 228.600 183.400 247.849 ;
        RECT 130.048 207.350 131.048 246.849 ;
        RECT 129.048 206.350 130.048 245.849 ;
        RECT 128.048 205.350 129.048 244.849 ;
        RECT 127.048 204.350 128.048 243.849 ;
        RECT 126.048 203.350 127.048 242.849 ;
        RECT 125.048 202.350 126.048 241.849 ;
        RECT 125.032 229.850 184.550 241.833 ;
        RECT 124.800 201.350 125.048 241.601 ;
        RECT 123.800 201.118 124.800 240.601 ;
        RECT 122.800 200.118 123.800 239.601 ;
        RECT 121.800 199.118 122.800 238.601 ;
        RECT 120.800 198.118 121.800 237.601 ;
        RECT 119.800 197.118 120.800 236.601 ;
        RECT 118.800 196.118 119.800 235.601 ;
        RECT 117.800 195.118 118.800 234.601 ;
        RECT 116.800 194.118 117.800 233.601 ;
        RECT 115.800 193.118 116.800 232.601 ;
        RECT 114.800 192.118 115.800 231.601 ;
        RECT 113.800 191.118 114.800 230.601 ;
        RECT 13.800 126.501 113.800 224.700 ;
        RECT 112.998 126.352 113.800 229.799 ;
        RECT 14.650 125.651 112.998 225.550 ;
        RECT 14.751 125.550 112.998 225.550 ;
    END
  END PAD
  PIN VDD
    DIRECTION INOUT ;
    USE POWER ;
    SHAPE ABUTMENT ;
    PORT
      LAYER metal1 ;
        RECT 161.150 0.000 164.197 233.850 ;
        RECT 0.000 0.000 273.000 90.700 ;
        RECT 258.200 0.000 260.700 169.600 ;
        RECT 251.650 0.000 254.150 161.100 ;
        RECT 239.750 0.000 242.250 161.100 ;
        RECT 228.350 0.000 230.850 161.100 ;
        RECT 217.150 0.000 219.650 152.650 ;
        RECT 206.350 0.000 208.850 152.600 ;
        RECT 193.900 0.000 196.400 169.650 ;
        RECT 182.053 0.000 185.150 233.900 ;
        RECT 182.053 0.000 184.800 234.250 ;
        RECT 181.650 0.000 185.150 233.847 ;
        RECT 170.652 0.000 185.150 108.750 ;
        RECT 170.150 0.000 185.150 108.248 ;
        RECT 161.150 0.000 164.650 233.797 ;
        RECT 161.550 0.000 164.197 234.250 ;
    END
    PORT
      CLASS CORE ;
      LAYER metal1 ;
        RECT 193.900 167.100 260.700 169.600 ;
    END
  END VDD
  PIN P_EN
    DIRECTION INPUT ;
    PORT
      LAYER metal2 ;
        RECT 218.150 40.300 220.650 165.600 ;
        RECT 223.450 0.000 225.950 19.300 ;
        RECT 218.150 163.100 224.450 165.600 ;
        RECT 218.150 40.300 224.000 44.500 ;
        RECT 221.500 16.800 224.000 44.500 ;
    END
  END P_EN
  OBS 
      LAYER metal2 ;
        RECT 0.850 228.500 106.799 253.250 ;
        RECT 167.600 111.198 167.702 189.650 ;
        RECT 167.600 111.700 178.700 189.650 ;
        RECT 167.600 111.198 167.653 190.153 ;
        RECT 188.100 93.650 190.950 96.250 ;
        RECT 193.900 212.354 202.600 253.250 ;
        RECT 165.950 102.550 168.950 108.552 ;
        RECT 165.950 104.750 189.650 108.300 ;
        RECT 166.150 102.450 168.950 108.552 ;
        RECT 166.150 102.350 168.850 108.652 ;
        RECT 0.850 104.850 168.650 108.950 ;
        RECT 0.850 104.850 168.600 109.000 ;
        RECT 0.850 104.850 167.600 109.550 ;
        RECT 0.850 104.850 150.800 110.101 ;
        RECT 0.850 104.850 149.800 122.548 ;
        RECT 0.850 103.450 148.400 122.600 ;
        RECT 115.948 104.850 149.298 123.050 ;
        RECT 115.948 103.450 148.400 123.402 ;
        RECT 199.350 93.650 203.400 189.450 ;
        RECT 186.150 104.750 189.650 160.200 ;
        RECT 186.150 157.700 208.800 160.200 ;
        RECT 199.350 155.550 208.800 164.150 ;
        RECT 195.850 162.100 205.950 187.200 ;
        RECT 193.900 181.650 207.750 186.850 ;
        RECT 193.900 181.650 205.350 187.450 ;
        RECT 116.750 103.450 148.400 188.168 ;
        RECT 193.900 181.650 204.750 188.450 ;
        RECT 117.750 103.450 148.400 189.168 ;
        RECT 193.900 181.650 203.750 189.450 ;
        RECT 193.900 181.650 203.050 189.650 ;
        RECT 118.750 103.450 148.400 190.168 ;
        RECT 119.750 103.450 148.400 191.168 ;
        RECT 120.750 103.450 148.400 192.168 ;
        RECT 121.750 103.450 148.400 193.168 ;
        RECT 122.750 103.450 148.400 194.168 ;
        RECT 123.750 103.450 148.400 195.168 ;
        RECT 124.750 103.450 148.400 196.168 ;
        RECT 125.750 103.450 148.400 197.168 ;
        RECT 126.750 103.450 148.400 198.168 ;
        RECT 127.750 103.450 148.400 198.400 ;
        RECT 127.998 103.450 148.400 199.400 ;
        RECT 128.998 103.450 148.400 200.400 ;
        RECT 129.998 103.450 148.400 201.400 ;
        RECT 130.998 103.450 148.400 202.400 ;
        RECT 131.998 103.450 148.400 203.400 ;
        RECT 132.998 103.450 148.400 204.400 ;
        RECT 133.998 103.450 148.400 205.400 ;
        RECT 134.998 103.450 148.400 205.502 ;
        RECT 135.100 103.450 148.400 206.502 ;
        RECT 136.100 103.450 148.400 207.502 ;
        RECT 137.100 103.450 148.400 208.502 ;
        RECT 138.100 103.450 148.400 209.502 ;
        RECT 139.100 103.450 148.400 210.502 ;
        RECT 140.100 103.450 148.400 211.502 ;
        RECT 141.100 103.450 148.400 212.502 ;
        RECT 142.100 103.450 148.400 213.502 ;
        RECT 143.100 103.450 148.400 214.502 ;
        RECT 144.100 103.450 148.400 215.502 ;
        RECT 145.100 103.450 148.400 216.502 ;
        RECT 146.100 103.450 148.400 217.502 ;
        RECT 147.100 103.450 148.400 218.502 ;
        RECT 148.100 103.450 148.400 219.502 ;
        RECT 211.000 212.354 218.050 253.250 ;
        RECT 221.000 207.800 224.700 253.250 ;
        RECT 223.600 93.650 225.400 104.650 ;
        RECT 227.650 212.354 228.950 253.250 ;
        RECT 231.900 207.800 235.400 253.250 ;
        RECT 233.800 93.650 236.800 104.650 ;
        RECT 245.200 93.650 247.950 104.650 ;
        RECT 238.350 252.350 254.150 253.250 ;
        RECT 238.350 237.250 254.150 243.950 ;
        RECT 263.500 252.350 272.150 253.250 ;
        RECT 263.500 237.250 272.150 243.950 ;
      LAYER metal1 ;
        RECT 0.750 106.650 149.350 249.448 ;
        RECT 0.750 103.250 148.600 253.450 ;
        RECT 166.150 110.250 179.130 135.394 ;
        RECT 166.150 102.350 168.650 135.394 ;
        RECT 166.157 111.270 180.150 135.413 ;
        RECT 166.238 111.270 180.150 135.448 ;
        RECT 166.238 110.468 179.348 135.532 ;
        RECT 166.956 110.468 179.348 136.250 ;
        RECT 166.750 139.250 178.900 253.450 ;
        RECT 167.400 110.250 178.900 253.450 ;
        RECT 166.150 139.850 178.900 253.450 ;
        RECT 166.150 139.906 179.900 253.450 ;
        RECT 166.150 140.156 180.150 253.450 ;
        RECT 162.300 237.000 184.000 253.450 ;
        RECT 187.900 93.450 191.150 96.450 ;
        RECT 193.700 181.450 218.250 208.650 ;
        RECT 206.150 181.450 208.700 208.750 ;
        RECT 193.700 181.450 203.050 234.500 ;
        RECT 210.700 183.800 218.700 249.300 ;
        RECT 210.700 181.450 218.250 252.900 ;
        RECT 193.700 181.450 202.800 253.450 ;
        RECT 210.800 181.450 218.250 253.450 ;
        RECT 227.000 183.800 229.500 249.300 ;
        RECT 227.450 181.450 229.150 253.450 ;
        RECT 238.150 252.150 254.350 253.450 ;
        RECT 237.300 183.800 254.350 243.300 ;
        RECT 238.150 181.450 254.350 244.150 ;
        RECT 251.300 181.450 253.800 246.000 ;
        RECT 199.150 93.450 203.600 164.600 ;
        RECT 198.950 117.700 203.600 164.600 ;
        RECT 198.950 154.300 205.950 164.600 ;
        RECT 210.350 153.800 214.400 164.350 ;
        RECT 211.600 93.450 214.400 164.350 ;
        RECT 222.400 93.450 225.600 165.600 ;
        RECT 198.950 155.400 225.600 164.350 ;
        RECT 233.600 93.450 237.000 164.350 ;
        RECT 245.000 93.450 248.900 164.350 ;
        RECT 198.950 163.850 255.450 164.350 ;
        RECT 198.950 155.350 212.850 164.600 ;
        RECT 221.950 163.100 227.950 165.600 ;
        RECT 263.300 252.150 272.250 253.450 ;
        RECT 263.300 181.450 272.250 244.150 ;
        RECT 199.150 172.350 272.250 172.450 ;
        RECT 193.700 172.400 272.250 172.450 ;
        RECT 263.450 93.450 272.250 164.350 ;
      LAYER via1 ;
        RECT 0.750 0.750 272.250 304.150 ;
  END 
END BPD240



MACRO BPD24D
  CLASS  PAD ;
  FOREIGN BPD24D 0.000 0.000 ;
  ORIGIN 0.000 0.000 ;
  SIZE 273.000 BY 304.900 ;
  SYMMETRY X Y R90  ;
  SITE IO ;
  PIN N_EN
    DIRECTION INPUT ;
    PORT
      LAYER metal2 ;
        RECT 252.850 0.000 255.350 22.250 ;
        RECT 250.300 182.900 255.800 185.400 ;
        RECT 253.300 16.950 255.800 185.400 ;
    END
  END N_EN
  PIN TO_CORE
    DIRECTION OUTPUT ;
    PORT
      LAYER metal2 ;
        RECT 210.500 123.600 213.000 184.800 ;
        RECT 210.850 0.000 213.350 149.200 ;
        RECT 209.450 182.300 213.000 184.800 ;
    END
  END TO_CORE
  PIN VSS
    DIRECTION INOUT ;
    USE GROUND ;
    SHAPE ABUTMENT ;
    PORT
      LAYER metal2 ;
        RECT 0.000 256.200 273.000 304.900 ;
      LAYER metal1 ;
        RECT 0.750 95.850 158.334 100.500 ;
        RECT 0.000 256.200 273.000 304.900 ;
        RECT 247.900 230.150 259.350 304.900 ;
        RECT 256.850 175.550 259.350 304.900 ;
        RECT 186.750 175.550 259.350 180.200 ;
        RECT 249.500 213.050 252.000 304.900 ;
        RECT 230.650 186.950 247.850 190.300 ;
        RECT 230.650 186.950 234.150 304.900 ;
        RECT 219.750 186.200 223.450 304.900 ;
        RECT 204.300 208.100 206.800 304.900 ;
        RECT 186.750 99.300 190.950 304.900 ;
        RECT 186.850 99.200 190.850 304.900 ;
        RECT 151.350 97.066 159.550 304.900 ;
        RECT 0.750 96.850 159.334 100.500 ;
    END
  END VSS
  PIN PAD
    DIRECTION INOUT ;
    PORT
      LAYER metal2 ;
        RECT 14.751 125.550 112.998 225.550 ;
        RECT 14.650 125.651 112.998 225.550 ;
        RECT 112.998 229.147 179.547 229.799 ;
        RECT 14.650 126.352 113.800 225.550 ;
        RECT 13.800 126.501 113.800 224.700 ;
        RECT 113.800 229.800 180.200 230.601 ;
        RECT 13.800 191.118 114.800 224.700 ;
        RECT 114.800 229.800 180.200 231.601 ;
        RECT 13.800 192.118 115.800 224.700 ;
        RECT 115.800 229.800 180.200 232.601 ;
        RECT 13.800 193.118 116.800 224.700 ;
        RECT 116.800 229.800 180.200 233.601 ;
        RECT 13.800 194.118 117.800 224.700 ;
        RECT 117.800 229.800 180.200 234.601 ;
        RECT 221.400 149.400 246.700 155.100 ;
        RECT 243.800 107.600 246.700 155.100 ;
        RECT 236.050 193.000 239.750 234.300 ;
        RECT 225.250 193.000 239.750 202.850 ;
        RECT 227.050 149.400 235.950 202.850 ;
        RECT 221.400 149.300 235.750 155.100 ;
        RECT 232.450 107.600 235.750 202.850 ;
        RECT 225.250 189.600 228.600 205.950 ;
        RECT 167.188 193.500 228.600 202.900 ;
        RECT 221.400 107.600 224.400 155.100 ;
        RECT 214.100 189.800 217.450 205.400 ;
        RECT 214.050 189.800 217.450 202.900 ;
        RECT 132.048 229.800 180.200 248.497 ;
        RECT 132.150 229.147 179.547 249.150 ;
        RECT 112.749 229.050 179.450 229.550 ;
        RECT 112.749 228.600 178.450 229.550 ;
        RECT 165.600 227.600 178.450 249.150 ;
        RECT 166.350 194.338 178.450 249.150 ;
        RECT 112.749 228.452 152.150 229.550 ;
        RECT 111.749 227.452 151.150 228.550 ;
        RECT 110.749 226.452 150.150 227.550 ;
        RECT 109.749 225.452 149.150 226.550 ;
        RECT 14.650 224.452 148.150 225.550 ;
        RECT 13.800 223.452 147.150 224.700 ;
        RECT 13.800 222.452 146.150 224.700 ;
        RECT 13.800 221.452 145.150 224.700 ;
        RECT 13.800 220.452 144.150 224.700 ;
        RECT 13.800 219.452 143.150 224.700 ;
        RECT 13.800 218.452 142.150 224.700 ;
        RECT 13.800 217.452 141.150 224.700 ;
        RECT 13.800 216.452 140.150 224.700 ;
        RECT 13.800 215.452 139.150 224.700 ;
        RECT 13.800 214.452 138.150 224.700 ;
        RECT 13.800 213.452 137.150 224.700 ;
        RECT 13.800 212.452 136.150 224.700 ;
        RECT 13.800 211.452 135.150 224.700 ;
        RECT 13.800 210.452 134.150 224.700 ;
        RECT 13.800 209.452 133.150 224.700 ;
        RECT 13.800 208.452 132.150 224.700 ;
        RECT 132.048 229.147 179.547 248.849 ;
        RECT 13.800 208.350 132.048 224.700 ;
        RECT 131.048 229.800 180.200 247.849 ;
        RECT 13.800 207.350 131.048 224.700 ;
        RECT 130.048 229.800 180.200 246.849 ;
        RECT 13.800 206.350 130.048 224.700 ;
        RECT 129.048 229.800 180.200 245.849 ;
        RECT 13.800 205.350 129.048 224.700 ;
        RECT 128.048 229.800 180.200 244.849 ;
        RECT 13.800 204.350 128.048 224.700 ;
        RECT 127.048 229.800 180.200 243.849 ;
        RECT 13.800 203.350 127.048 224.700 ;
        RECT 126.048 229.800 180.200 242.849 ;
        RECT 13.800 202.350 126.048 224.700 ;
        RECT 125.048 229.800 180.200 241.849 ;
        RECT 13.800 201.350 125.048 224.700 ;
        RECT 125.032 229.800 180.200 241.833 ;
        RECT 124.800 229.800 180.200 241.601 ;
        RECT 13.800 201.118 124.800 224.700 ;
        RECT 123.800 229.800 180.200 240.601 ;
        RECT 13.800 200.118 123.800 224.700 ;
        RECT 122.800 229.800 180.200 239.601 ;
        RECT 13.800 199.118 122.800 224.700 ;
        RECT 121.800 229.800 180.200 238.601 ;
        RECT 13.800 198.118 121.800 224.700 ;
        RECT 120.800 229.800 180.200 237.601 ;
        RECT 13.800 197.118 120.800 224.700 ;
        RECT 119.800 229.800 180.200 236.601 ;
        RECT 13.800 196.118 119.800 224.700 ;
        RECT 118.800 229.800 180.200 235.601 ;
        RECT 13.800 195.118 118.800 224.700 ;
    END
  END PAD
  PIN VDD
    DIRECTION INOUT ;
    USE POWER ;
    SHAPE ABUTMENT ;
    PORT
      LAYER metal1 ;
        RECT 161.150 0.000 164.197 233.850 ;
        RECT 0.000 0.000 273.000 90.700 ;
        RECT 256.150 0.000 259.850 170.500 ;
        RECT 205.100 0.000 259.850 94.900 ;
        RECT 250.400 0.000 252.900 161.100 ;
        RECT 238.500 0.000 241.000 161.100 ;
        RECT 227.100 0.000 229.600 161.100 ;
        RECT 215.900 0.000 218.400 152.650 ;
        RECT 205.100 0.000 207.600 152.600 ;
        RECT 192.650 0.000 195.150 169.650 ;
        RECT 182.053 0.000 185.150 233.900 ;
        RECT 182.053 0.000 184.800 234.250 ;
        RECT 181.650 0.000 185.150 233.847 ;
        RECT 170.652 0.000 185.150 108.750 ;
        RECT 170.150 0.000 185.150 108.248 ;
        RECT 161.150 0.000 164.650 233.797 ;
        RECT 161.550 0.000 164.197 234.250 ;
    END
    PORT
      CLASS CORE ;
      LAYER metal1 ;
        RECT 195.150 167.100 259.850 170.500 ;
    END
  END VDD
  PIN P_EN
    DIRECTION INPUT ;
    PORT
      LAYER metal2 ;
        RECT 216.900 40.300 219.400 165.600 ;
        RECT 216.900 163.100 223.200 165.600 ;
        RECT 219.250 0.000 221.750 44.500 ;
    END
  END P_EN
  OBS 
      LAYER metal2 ;
        RECT 0.850 228.500 106.799 253.250 ;
        RECT 167.600 111.198 167.702 190.550 ;
        RECT 167.600 111.700 178.700 190.550 ;
        RECT 183.150 237.200 183.800 253.250 ;
        RECT 188.100 93.650 189.700 96.250 ;
        RECT 193.900 205.850 201.350 253.250 ;
        RECT 165.950 102.550 168.950 108.552 ;
        RECT 198.100 93.650 202.150 190.550 ;
        RECT 165.950 104.750 204.700 107.750 ;
        RECT 0.850 104.850 189.650 108.300 ;
        RECT 166.150 102.450 168.950 108.552 ;
        RECT 166.150 102.350 168.850 108.652 ;
        RECT 0.850 104.850 168.650 108.950 ;
        RECT 0.850 104.850 168.600 109.000 ;
        RECT 0.850 104.850 167.600 109.550 ;
        RECT 0.850 104.850 150.800 110.101 ;
        RECT 0.850 104.850 149.800 122.548 ;
        RECT 0.850 103.450 148.400 122.600 ;
        RECT 115.948 104.850 149.298 123.050 ;
        RECT 115.948 103.450 148.400 123.402 ;
        RECT 198.100 155.550 207.550 164.150 ;
        RECT 198.100 104.750 204.700 190.550 ;
        RECT 194.600 162.100 204.700 190.550 ;
        RECT 193.900 183.150 206.500 190.550 ;
        RECT 116.750 103.450 148.400 188.168 ;
        RECT 117.750 103.450 148.400 189.168 ;
        RECT 118.750 103.450 148.400 190.168 ;
        RECT 193.900 187.750 211.100 190.550 ;
        RECT 119.750 103.450 148.400 191.168 ;
        RECT 120.750 103.450 148.400 192.168 ;
        RECT 121.750 103.450 148.400 193.168 ;
        RECT 122.750 103.450 148.400 194.168 ;
        RECT 123.750 103.450 148.400 195.168 ;
        RECT 124.750 103.450 148.400 196.168 ;
        RECT 125.750 103.450 148.400 197.168 ;
        RECT 126.750 103.450 148.400 198.168 ;
        RECT 127.750 103.450 148.400 198.400 ;
        RECT 127.998 103.450 148.400 199.400 ;
        RECT 128.998 103.450 148.400 200.400 ;
        RECT 129.998 103.450 148.400 201.400 ;
        RECT 130.998 103.450 148.400 202.400 ;
        RECT 131.998 103.450 148.400 203.400 ;
        RECT 132.998 103.450 148.400 204.400 ;
        RECT 133.998 103.450 148.400 205.400 ;
        RECT 134.998 103.450 148.400 205.502 ;
        RECT 135.100 103.450 148.400 206.502 ;
        RECT 136.100 103.450 148.400 207.502 ;
        RECT 137.100 103.450 148.400 208.502 ;
        RECT 138.100 103.450 148.400 209.502 ;
        RECT 139.100 103.450 148.400 210.502 ;
        RECT 140.100 103.450 148.400 211.502 ;
        RECT 141.100 103.450 148.400 212.502 ;
        RECT 142.100 103.450 148.400 213.502 ;
        RECT 143.100 103.450 148.400 214.502 ;
        RECT 144.100 103.450 148.400 215.502 ;
        RECT 145.100 103.450 148.400 216.502 ;
        RECT 146.100 103.450 148.400 217.502 ;
        RECT 147.100 103.450 148.400 218.502 ;
        RECT 148.100 103.450 148.400 219.502 ;
        RECT 209.750 205.850 211.150 253.250 ;
        RECT 209.750 208.350 216.800 253.250 ;
        RECT 219.750 207.800 223.450 253.250 ;
        RECT 222.350 97.850 224.150 104.650 ;
        RECT 226.400 208.900 227.700 253.250 ;
        RECT 230.650 207.800 234.150 253.250 ;
        RECT 232.550 97.850 235.550 104.650 ;
        RECT 237.100 237.250 244.950 253.250 ;
        RECT 243.950 97.850 251.250 104.650 ;
        RECT 248.750 89.400 251.250 173.800 ;
        RECT 243.350 171.100 251.200 173.900 ;
        RECT 243.350 171.100 245.850 203.950 ;
        RECT 262.300 237.250 272.150 253.250 ;
        RECT 262.800 93.650 272.150 104.650 ;
      LAYER metal1 ;
        RECT 0.750 106.650 149.350 249.448 ;
        RECT 0.750 103.250 148.600 253.450 ;
        RECT 166.150 110.250 179.130 135.394 ;
        RECT 166.150 102.350 168.650 135.394 ;
        RECT 166.157 111.270 180.150 135.413 ;
        RECT 166.238 111.270 180.150 135.448 ;
        RECT 166.238 110.468 179.348 135.532 ;
        RECT 166.956 110.468 179.348 136.250 ;
        RECT 166.750 139.250 178.900 253.450 ;
        RECT 167.400 110.250 178.900 253.450 ;
        RECT 166.150 139.850 178.900 253.450 ;
        RECT 166.150 139.906 179.900 253.450 ;
        RECT 166.150 140.156 180.150 253.450 ;
        RECT 162.300 237.000 184.000 253.450 ;
        RECT 187.900 93.450 189.900 96.450 ;
        RECT 197.900 93.450 202.350 164.600 ;
        RECT 197.700 117.700 202.350 164.600 ;
        RECT 197.700 154.300 204.700 164.600 ;
        RECT 209.100 153.800 213.150 164.350 ;
        RECT 210.350 97.650 213.150 164.350 ;
        RECT 221.150 97.650 224.350 165.600 ;
        RECT 197.700 155.400 224.350 164.350 ;
        RECT 232.350 97.650 235.750 164.350 ;
        RECT 243.750 97.650 247.650 164.350 ;
        RECT 197.700 163.850 253.400 164.350 ;
        RECT 197.700 155.350 211.600 164.600 ;
        RECT 220.700 163.100 226.700 165.600 ;
        RECT 193.700 182.950 254.100 183.450 ;
        RECT 226.200 182.950 254.100 184.200 ;
        RECT 250.300 182.900 252.800 210.300 ;
        RECT 250.050 190.750 252.800 210.300 ;
        RECT 193.700 182.950 217.000 205.350 ;
        RECT 236.900 193.050 254.100 210.300 ;
        RECT 236.050 193.450 246.750 227.400 ;
        RECT 193.700 182.950 201.800 230.500 ;
        RECT 209.450 182.300 211.950 252.900 ;
        RECT 209.550 187.450 217.450 252.950 ;
        RECT 225.750 187.450 228.250 252.950 ;
        RECT 236.050 193.450 245.150 252.950 ;
        RECT 193.700 182.950 201.550 253.450 ;
        RECT 209.550 182.950 217.000 253.450 ;
        RECT 226.200 182.950 227.900 253.450 ;
        RECT 236.900 193.050 245.150 253.450 ;
        RECT 262.100 193.050 272.250 253.450 ;
        RECT 262.100 182.950 272.250 184.200 ;
        RECT 262.600 93.450 272.250 164.350 ;
      LAYER via1 ;
        RECT 0.750 0.750 272.250 304.150 ;
  END 
END BPD24D

MACRO BPD24U
  CLASS  PAD ;
  FOREIGN BPD24U 0.000 0.000 ;
  ORIGIN 0.000 0.000 ;
  SIZE 273.050 BY 304.900 ;
  SYMMETRY X Y R90  ;
  SITE IO ;
  PIN N_EN
    DIRECTION INPUT ;
    PORT
      LAYER metal2 ;
        RECT 252.850 0.000 255.350 185.600 ;
        RECT 251.400 183.100 255.350 185.600 ;
    END
  END N_EN
  PIN TO_CORE
    DIRECTION OUTPUT ;
    PORT
      LAYER metal2 ;
        RECT 211.850 123.600 214.350 184.800 ;
        RECT 213.200 42.000 215.700 149.200 ;
        RECT 210.800 182.300 214.350 184.800 ;
        RECT 210.850 0.000 213.350 44.500 ;
    END
  END TO_CORE
  PIN VSS
    DIRECTION INOUT ;
    USE GROUND ;
    SHAPE ABUTMENT ;
    PORT
      LAYER metal2 ;
        RECT 0.000 256.200 273.000 304.900 ;
      LAYER metal1 ;
        RECT 0.750 95.850 158.334 100.500 ;
        RECT 0.000 256.200 273.000 304.900 ;
        RECT 255.800 175.100 258.400 304.900 ;
        RECT 186.750 175.100 258.400 179.800 ;
        RECT 232.000 246.900 248.350 249.400 ;
        RECT 232.000 183.800 235.500 304.900 ;
        RECT 221.100 175.100 224.800 304.900 ;
        RECT 205.650 211.400 208.150 304.900 ;
        RECT 186.750 99.300 190.950 304.900 ;
        RECT 186.850 99.200 190.850 304.900 ;
        RECT 187.150 92.550 189.650 304.900 ;
        RECT 151.350 97.066 159.550 304.900 ;
        RECT 0.750 96.850 159.334 100.500 ;
    END
  END VSS
  PIN PAD
    DIRECTION INOUT ;
    PORT
      LAYER metal2 ;
        RECT 14.751 125.550 112.998 225.550 ;
        RECT 14.650 125.651 112.998 225.550 ;
        RECT 112.998 228.637 180.750 229.799 ;
        RECT 14.650 126.352 113.800 225.550 ;
        RECT 13.800 126.501 113.800 224.700 ;
        RECT 113.800 228.637 180.750 230.601 ;
        RECT 13.800 191.118 114.800 224.700 ;
        RECT 114.800 228.637 180.750 231.601 ;
        RECT 13.800 192.118 115.800 224.700 ;
        RECT 115.800 228.637 180.750 232.601 ;
        RECT 222.750 148.250 248.050 155.100 ;
        RECT 245.150 107.600 248.050 155.100 ;
        RECT 244.950 148.250 248.000 155.150 ;
        RECT 237.400 148.250 241.600 234.300 ;
        RECT 228.400 148.250 241.600 204.300 ;
        RECT 222.750 147.700 237.100 155.100 ;
        RECT 233.800 107.600 237.100 204.300 ;
        RECT 167.750 194.207 241.600 204.300 ;
        RECT 209.554 189.800 241.600 204.300 ;
        RECT 222.750 107.600 225.750 155.100 ;
        RECT 166.750 195.207 218.800 204.350 ;
        RECT 167.850 192.554 241.600 204.300 ;
        RECT 208.800 190.554 218.800 204.350 ;
        RECT 207.800 191.554 241.600 204.300 ;
        RECT 193.050 105.400 207.650 107.900 ;
        RECT 167.850 113.250 195.650 116.300 ;
        RECT 193.050 105.400 195.650 116.300 ;
        RECT 166.750 195.207 180.850 204.554 ;
        RECT 132.048 228.637 180.750 248.050 ;
        RECT 132.150 228.600 179.650 249.150 ;
        RECT 167.850 192.450 171.850 249.150 ;
        RECT 167.850 113.250 170.850 249.150 ;
        RECT 166.750 195.207 179.850 248.950 ;
        RECT 112.749 228.452 152.150 229.550 ;
        RECT 111.749 227.452 151.150 228.550 ;
        RECT 110.749 226.452 150.150 227.550 ;
        RECT 109.749 225.452 149.150 226.550 ;
        RECT 14.650 224.452 148.150 225.550 ;
        RECT 13.800 223.452 147.150 224.700 ;
        RECT 13.800 222.452 146.150 224.700 ;
        RECT 13.800 221.452 145.150 224.700 ;
        RECT 13.800 220.452 144.150 224.700 ;
        RECT 13.800 219.452 143.150 224.700 ;
        RECT 13.800 218.452 142.150 224.700 ;
        RECT 13.800 217.452 141.150 224.700 ;
        RECT 13.800 216.452 140.150 224.700 ;
        RECT 13.800 215.452 139.150 224.700 ;
        RECT 13.800 214.452 138.150 224.700 ;
        RECT 13.800 213.452 137.150 224.700 ;
        RECT 13.800 212.452 136.150 224.700 ;
        RECT 13.800 211.452 135.150 224.700 ;
        RECT 13.800 210.452 134.150 224.700 ;
        RECT 13.800 209.452 133.150 224.700 ;
        RECT 13.800 208.452 132.150 224.700 ;
        RECT 132.048 228.600 179.850 248.849 ;
        RECT 13.800 208.350 132.048 224.700 ;
        RECT 131.048 228.637 180.750 247.849 ;
        RECT 13.800 207.350 131.048 224.700 ;
        RECT 130.048 228.637 180.750 246.849 ;
        RECT 13.800 206.350 130.048 224.700 ;
        RECT 129.048 228.637 180.750 245.849 ;
        RECT 13.800 205.350 129.048 224.700 ;
        RECT 128.048 228.637 180.750 244.849 ;
        RECT 13.800 204.350 128.048 224.700 ;
        RECT 127.048 228.637 180.750 243.849 ;
        RECT 13.800 203.350 127.048 224.700 ;
        RECT 126.048 228.637 180.750 242.849 ;
        RECT 13.800 202.350 126.048 224.700 ;
        RECT 125.048 228.637 180.750 241.849 ;
        RECT 13.800 201.350 125.048 224.700 ;
        RECT 125.032 228.637 180.750 241.833 ;
        RECT 124.800 228.637 180.750 241.601 ;
        RECT 13.800 201.118 124.800 224.700 ;
        RECT 123.800 228.637 180.750 240.601 ;
        RECT 13.800 200.118 123.800 224.700 ;
        RECT 122.800 228.637 180.750 239.601 ;
        RECT 13.800 199.118 122.800 224.700 ;
        RECT 121.800 228.637 180.750 238.601 ;
        RECT 13.800 198.118 121.800 224.700 ;
        RECT 120.800 228.637 180.750 237.601 ;
        RECT 13.800 197.118 120.800 224.700 ;
        RECT 119.800 228.637 180.750 236.601 ;
        RECT 13.800 196.118 119.800 224.700 ;
        RECT 118.800 228.637 180.750 235.601 ;
        RECT 13.800 195.118 118.800 224.700 ;
        RECT 117.800 228.637 180.750 234.601 ;
        RECT 13.800 194.118 117.800 224.700 ;
        RECT 116.800 228.637 180.750 233.601 ;
        RECT 13.800 193.118 116.800 224.700 ;
    END
  END PAD
  PIN VDD
    DIRECTION INOUT ;
    USE POWER ;
    SHAPE ABUTMENT ;
    PORT
      LAYER metal1 ;
        RECT 161.150 0.000 164.197 233.850 ;
        RECT 0.000 0.000 273.050 90.700 ;
        RECT 258.300 0.000 260.800 169.600 ;
        RECT 251.750 0.000 254.250 161.100 ;
        RECT 239.850 0.000 242.350 161.100 ;
        RECT 228.450 0.000 230.950 161.100 ;
        RECT 217.250 0.000 219.750 152.650 ;
        RECT 206.450 112.900 219.750 115.450 ;
        RECT 214.150 0.000 219.750 115.450 ;
        RECT 206.450 112.900 208.950 152.600 ;
        RECT 205.000 0.000 207.600 94.900 ;
        RECT 193.750 0.000 196.500 169.650 ;
        RECT 182.053 0.000 185.150 233.900 ;
        RECT 182.053 0.000 184.800 234.250 ;
        RECT 181.650 0.000 185.150 233.847 ;
        RECT 170.652 0.000 185.150 108.750 ;
        RECT 170.150 0.000 185.150 108.248 ;
        RECT 161.150 0.000 164.650 233.797 ;
        RECT 161.550 0.000 164.197 234.250 ;
    END
    PORT
      CLASS CORE ;
      LAYER metal1 ;
        RECT 193.750 167.100 260.800 169.600 ;
    END
  END VDD
  PIN P_EN
    DIRECTION INPUT ;
    PORT
      LAYER metal2 ;
        RECT 218.250 40.300 220.750 165.600 ;
        RECT 218.250 40.300 225.950 44.500 ;
        RECT 223.450 0.000 225.950 44.500 ;
        RECT 218.250 163.100 224.550 165.600 ;
    END
  END P_EN
  OBS 
      LAYER metal2 ;
        RECT 0.850 228.500 106.799 253.250 ;
        RECT 183.700 237.200 183.800 253.250 ;
        RECT 165.950 102.550 168.950 108.552 ;
        RECT 165.950 104.750 189.650 108.300 ;
        RECT 166.150 102.450 168.950 108.552 ;
        RECT 166.150 102.350 168.850 108.652 ;
        RECT 0.850 104.850 168.650 108.950 ;
        RECT 0.850 104.850 168.050 109.550 ;
        RECT 0.850 104.850 150.800 110.101 ;
        RECT 0.850 104.850 149.800 122.548 ;
        RECT 0.850 103.450 148.400 122.600 ;
        RECT 115.948 104.850 149.298 123.050 ;
        RECT 115.948 103.450 148.400 123.402 ;
        RECT 116.750 103.450 148.400 188.168 ;
        RECT 117.750 103.450 148.400 189.168 ;
        RECT 118.750 103.450 148.400 190.168 ;
        RECT 119.750 103.450 148.400 191.168 ;
        RECT 120.750 103.450 148.400 192.168 ;
        RECT 121.750 103.450 148.400 193.168 ;
        RECT 122.750 103.450 148.400 194.168 ;
        RECT 123.750 103.450 148.400 195.168 ;
        RECT 124.750 103.450 148.400 196.168 ;
        RECT 125.750 103.450 148.400 197.168 ;
        RECT 126.750 103.450 148.400 198.168 ;
        RECT 127.750 103.450 148.400 198.400 ;
        RECT 127.998 103.450 148.400 199.400 ;
        RECT 128.998 103.450 148.400 200.400 ;
        RECT 129.998 103.450 148.400 201.400 ;
        RECT 130.998 103.450 148.400 202.400 ;
        RECT 131.998 103.450 148.400 203.400 ;
        RECT 132.998 103.450 148.400 204.400 ;
        RECT 133.998 103.450 148.400 205.400 ;
        RECT 134.998 103.450 148.400 205.502 ;
        RECT 135.100 103.450 148.400 206.502 ;
        RECT 136.100 103.450 148.400 207.502 ;
        RECT 137.100 103.450 148.400 208.502 ;
        RECT 138.100 103.450 148.400 209.502 ;
        RECT 139.100 103.450 148.400 210.502 ;
        RECT 140.100 103.450 148.400 211.502 ;
        RECT 141.100 103.450 148.400 212.502 ;
        RECT 142.100 103.450 148.400 213.502 ;
        RECT 143.100 103.450 148.400 214.502 ;
        RECT 144.100 103.450 148.400 215.502 ;
        RECT 145.100 103.450 148.400 216.502 ;
        RECT 146.100 103.450 148.400 217.502 ;
        RECT 147.100 103.450 148.400 218.502 ;
        RECT 148.100 103.450 148.400 219.502 ;
        RECT 199.450 119.250 203.500 189.604 ;
        RECT 173.800 122.700 179.100 160.200 ;
        RECT 173.800 157.700 208.900 160.200 ;
        RECT 199.450 155.550 208.900 164.150 ;
        RECT 195.950 162.100 206.050 187.604 ;
        RECT 193.900 182.750 207.850 186.850 ;
        RECT 193.900 182.750 206.604 187.604 ;
        RECT 193.900 182.750 205.850 188.604 ;
        RECT 173.800 119.250 178.700 189.500 ;
        RECT 174.800 119.250 178.700 189.604 ;
        RECT 193.900 182.750 204.850 189.604 ;
        RECT 200.650 119.250 203.150 189.900 ;
        RECT 187.150 92.550 189.650 99.350 ;
        RECT 199.450 93.650 202.050 102.450 ;
        RECT 187.150 96.850 202.050 99.350 ;
        RECT 199.450 97.850 210.250 102.450 ;
        RECT 193.900 207.504 218.150 208.450 ;
        RECT 193.900 207.504 202.700 253.250 ;
        RECT 211.100 207.504 218.150 253.250 ;
        RECT 221.100 207.800 224.800 253.250 ;
        RECT 223.700 93.650 225.500 102.450 ;
        RECT 227.750 207.504 229.050 253.250 ;
        RECT 232.000 207.800 235.500 253.250 ;
        RECT 233.900 93.650 236.900 102.450 ;
        RECT 245.300 93.650 248.800 102.450 ;
        RECT 238.450 252.350 252.850 253.250 ;
        RECT 238.450 237.250 252.850 243.950 ;
        RECT 261.350 252.350 272.200 253.250 ;
        RECT 261.350 237.250 272.200 243.950 ;
        RECT 263.750 93.650 272.200 102.450 ;
      LAYER metal1 ;
        RECT 0.750 106.650 149.350 249.448 ;
        RECT 0.750 103.250 148.600 253.450 ;
        RECT 166.150 110.250 179.130 135.394 ;
        RECT 166.150 102.350 168.650 135.394 ;
        RECT 166.157 111.270 180.150 135.413 ;
        RECT 166.238 111.270 180.150 135.448 ;
        RECT 166.238 110.468 179.348 135.532 ;
        RECT 166.956 110.468 179.348 136.250 ;
        RECT 166.750 139.250 178.900 253.450 ;
        RECT 167.400 110.250 178.900 253.450 ;
        RECT 166.150 139.850 178.900 253.450 ;
        RECT 166.150 139.906 179.900 253.450 ;
        RECT 166.150 140.156 180.150 253.450 ;
        RECT 162.300 237.000 184.000 253.450 ;
        RECT 211.850 118.100 214.350 151.700 ;
        RECT 193.700 182.550 218.350 208.650 ;
        RECT 193.700 182.550 203.150 234.500 ;
        RECT 210.800 183.800 218.800 249.300 ;
        RECT 210.800 182.300 213.300 252.900 ;
        RECT 193.700 182.550 202.900 253.450 ;
        RECT 210.900 182.550 218.350 253.450 ;
        RECT 227.100 183.800 229.600 249.300 ;
        RECT 227.550 182.550 229.250 253.450 ;
        RECT 238.250 252.150 253.050 253.450 ;
        RECT 237.400 183.800 253.900 243.300 ;
        RECT 238.250 182.550 253.050 244.150 ;
        RECT 251.400 183.100 253.900 246.000 ;
        RECT 199.250 93.450 202.250 164.600 ;
        RECT 199.100 96.850 205.000 99.350 ;
        RECT 210.350 93.450 211.400 110.150 ;
        RECT 199.250 97.650 211.400 110.150 ;
        RECT 222.500 93.450 225.700 110.150 ;
        RECT 233.700 93.450 237.100 110.150 ;
        RECT 245.100 93.450 249.000 110.150 ;
        RECT 199.250 97.650 207.650 110.900 ;
        RECT 199.250 96.850 203.700 164.600 ;
        RECT 199.050 117.700 203.700 164.600 ;
        RECT 199.050 154.300 206.050 164.600 ;
        RECT 222.750 93.450 225.250 165.600 ;
        RECT 234.150 93.450 236.650 164.350 ;
        RECT 245.550 93.450 248.050 164.350 ;
        RECT 199.050 155.350 214.500 164.350 ;
        RECT 222.500 155.350 225.700 165.600 ;
        RECT 199.050 155.400 225.700 164.350 ;
        RECT 233.700 155.350 237.100 164.350 ;
        RECT 245.100 155.350 249.000 164.350 ;
        RECT 199.050 163.850 255.550 164.350 ;
        RECT 210.450 153.800 212.950 164.600 ;
        RECT 199.050 155.350 212.950 164.600 ;
        RECT 222.050 163.100 228.050 165.600 ;
        RECT 261.150 252.150 272.300 253.450 ;
        RECT 261.150 182.550 272.300 244.150 ;
        RECT 263.550 155.350 272.300 164.350 ;
        RECT 263.550 93.450 272.300 110.150 ;
      LAYER via1 ;
        RECT 0.750 0.750 272.300 304.150 ;
  END 
END BPD24U



MACRO IPAD20
  CLASS  PAD ;
  FOREIGN IPAD20 0.000 0.000 ;
  ORIGIN 0.000 0.000 ;
  SIZE 239.400 BY 304.900 ;
  SYMMETRY X Y R90  ;
  SITE IO ;
  PIN OUT1
    DIRECTION OUTPUT ;
    PORT
      LAYER metal2 ;
        RECT 208.800 104.100 211.300 201.900 ;
        RECT 210.850 0.000 213.350 109.600 ;
        RECT 207.800 199.400 211.300 201.900 ;
    END
  END OUT1
  PIN VSS
    DIRECTION INOUT ;
    USE GROUND ;
    SHAPE ABUTMENT ;
    PORT
      LAYER metal2 ;
        RECT 0.000 256.200 239.400 304.900 ;
      LAYER metal1 ;
        RECT 0.750 95.850 158.334 100.500 ;
        RECT 0.000 256.200 239.400 304.900 ;
        RECT 215.850 181.550 221.950 304.900 ;
        RECT 186.750 181.550 221.950 188.850 ;
        RECT 202.650 196.400 205.150 304.900 ;
        RECT 186.750 99.300 190.950 304.900 ;
        RECT 186.850 99.200 190.850 304.900 ;
        RECT 151.350 97.066 159.550 304.900 ;
        RECT 0.750 96.850 159.334 100.500 ;
    END
  END VSS
  PIN IN1
    DIRECTION INPUT ;
    PORT
      LAYER metal2 ;
        RECT 14.751 125.550 112.998 225.550 ;
        RECT 14.650 125.651 112.998 225.550 ;
        RECT 112.998 229.147 179.547 229.799 ;
        RECT 14.650 126.352 113.800 225.550 ;
        RECT 13.800 126.501 113.800 224.700 ;
        RECT 113.800 229.800 180.200 230.601 ;
        RECT 13.800 191.118 114.800 224.700 ;
        RECT 114.800 229.800 180.200 231.601 ;
        RECT 13.800 192.118 115.800 224.700 ;
        RECT 115.800 229.800 180.200 232.601 ;
        RECT 13.800 193.118 116.800 224.700 ;
        RECT 116.800 229.800 180.200 233.601 ;
        RECT 13.800 194.118 117.800 224.700 ;
        RECT 117.800 229.800 180.200 234.601 ;
        RECT 13.800 195.118 118.800 224.700 ;
        RECT 118.800 229.800 180.200 235.601 ;
        RECT 132.048 229.800 180.200 248.497 ;
        RECT 132.150 229.147 179.547 249.150 ;
        RECT 112.749 228.600 179.000 229.550 ;
        RECT 112.749 228.452 152.150 229.550 ;
        RECT 111.749 227.452 151.150 228.550 ;
        RECT 110.749 226.452 150.150 227.550 ;
        RECT 109.749 225.452 149.150 226.550 ;
        RECT 14.650 224.452 148.150 225.550 ;
        RECT 13.800 223.452 147.150 224.700 ;
        RECT 13.800 222.452 146.150 224.700 ;
        RECT 13.800 221.452 145.150 224.700 ;
        RECT 13.800 220.452 144.150 224.700 ;
        RECT 13.800 219.452 143.150 224.700 ;
        RECT 13.800 218.452 142.150 224.700 ;
        RECT 13.800 217.452 141.150 224.700 ;
        RECT 13.800 216.452 140.150 224.700 ;
        RECT 13.800 215.452 139.150 224.700 ;
        RECT 13.800 214.452 138.150 224.700 ;
        RECT 13.800 213.452 137.150 224.700 ;
        RECT 13.800 212.452 136.150 224.700 ;
        RECT 13.800 211.452 135.150 224.700 ;
        RECT 13.800 210.452 134.150 224.700 ;
        RECT 13.800 209.452 133.150 224.700 ;
        RECT 13.800 208.452 132.150 224.700 ;
        RECT 132.048 229.147 179.547 248.849 ;
        RECT 13.800 208.350 132.048 224.700 ;
        RECT 131.048 229.800 180.200 247.849 ;
        RECT 13.800 207.350 131.048 224.700 ;
        RECT 130.048 229.800 180.200 246.849 ;
        RECT 13.800 206.350 130.048 224.700 ;
        RECT 129.048 229.800 180.200 245.849 ;
        RECT 13.800 205.350 129.048 224.700 ;
        RECT 128.048 229.800 180.200 244.849 ;
        RECT 13.800 204.350 128.048 224.700 ;
        RECT 127.048 229.800 180.200 243.849 ;
        RECT 13.800 203.350 127.048 224.700 ;
        RECT 126.048 229.800 180.200 242.849 ;
        RECT 13.800 202.350 126.048 224.700 ;
        RECT 125.048 229.800 180.200 241.849 ;
        RECT 13.800 201.350 125.048 224.700 ;
        RECT 125.032 229.800 180.200 241.833 ;
        RECT 124.800 229.800 180.200 241.601 ;
        RECT 13.800 201.118 124.800 224.700 ;
        RECT 123.800 229.800 180.200 240.601 ;
        RECT 13.800 200.118 123.800 224.700 ;
        RECT 122.800 229.800 180.200 239.601 ;
        RECT 13.800 199.118 122.800 224.700 ;
        RECT 121.800 229.800 180.200 238.601 ;
        RECT 13.800 198.118 121.800 224.700 ;
        RECT 120.800 229.800 180.200 237.601 ;
        RECT 13.800 197.118 120.800 224.700 ;
        RECT 119.800 229.800 180.200 236.601 ;
        RECT 13.800 196.118 119.800 224.700 ;
    END
  END IN1
  PIN VDD
    DIRECTION INOUT ;
    USE POWER ;
    SHAPE ABUTMENT ;
    PORT
      LAYER metal1 ;
        RECT 161.150 0.000 164.197 233.850 ;
        RECT 0.000 0.000 239.400 90.700 ;
        RECT 221.300 0.000 223.800 162.300 ;
        RECT 216.200 0.000 218.700 132.600 ;
        RECT 205.400 0.000 207.900 132.600 ;
        RECT 192.900 0.000 195.400 162.300 ;
        RECT 182.053 0.000 185.150 233.900 ;
        RECT 182.053 0.000 184.800 234.250 ;
        RECT 181.650 0.000 185.150 233.847 ;
        RECT 170.652 0.000 185.150 108.750 ;
        RECT 170.150 0.000 185.150 108.248 ;
        RECT 161.150 0.000 164.650 233.797 ;
        RECT 161.550 0.000 164.197 234.250 ;
    END
    PORT
      CLASS CORE ;
      LAYER metal1 ;
        RECT 192.900 155.800 223.800 162.300 ;
    END
  END VDD
  OBS 
      LAYER metal2 ;
        RECT 0.850 228.500 106.799 253.250 ;
        RECT 167.600 111.198 167.702 225.650 ;
        RECT 167.600 111.700 178.700 225.650 ;
        RECT 183.150 247.799 183.800 253.250 ;
        RECT 188.100 93.650 189.950 96.250 ;
        RECT 193.900 247.799 199.700 253.250 ;
        RECT 198.350 93.650 202.450 181.550 ;
        RECT 166.150 104.750 204.700 108.300 ;
        RECT 166.150 102.350 168.650 108.950 ;
        RECT 0.850 104.850 168.600 109.000 ;
        RECT 0.850 104.850 167.600 109.550 ;
        RECT 0.850 104.850 149.800 121.750 ;
        RECT 0.850 104.850 149.400 122.150 ;
        RECT 0.850 103.450 148.400 122.600 ;
        RECT 115.948 103.450 148.400 123.402 ;
        RECT 198.350 104.750 204.700 181.550 ;
        RECT 198.350 135.550 205.850 152.850 ;
        RECT 195.750 138.100 205.800 181.550 ;
        RECT 193.900 165.250 205.850 178.600 ;
        RECT 116.750 103.450 148.400 188.168 ;
        RECT 117.750 103.450 148.400 189.168 ;
        RECT 118.750 103.450 148.400 190.168 ;
        RECT 119.750 103.450 148.400 191.168 ;
        RECT 120.750 103.450 148.400 192.168 ;
        RECT 121.750 103.450 148.400 193.168 ;
        RECT 191.150 191.800 205.850 193.450 ;
        RECT 191.150 172.450 202.050 193.650 ;
        RECT 122.750 103.450 148.400 194.168 ;
        RECT 123.750 103.450 148.400 195.168 ;
        RECT 124.750 103.450 148.400 196.168 ;
        RECT 125.750 103.450 148.400 197.168 ;
        RECT 126.750 103.450 148.400 198.168 ;
        RECT 127.750 103.450 148.400 198.400 ;
        RECT 127.998 103.450 148.400 199.400 ;
        RECT 128.998 103.450 148.400 200.400 ;
        RECT 129.998 103.450 148.400 201.400 ;
        RECT 130.998 103.450 148.400 202.400 ;
        RECT 131.998 103.450 148.400 203.400 ;
        RECT 132.998 103.450 148.400 204.400 ;
        RECT 133.998 103.450 148.400 205.400 ;
        RECT 134.998 103.450 148.400 205.502 ;
        RECT 135.100 103.450 148.400 206.502 ;
        RECT 136.100 103.450 148.400 207.502 ;
        RECT 137.100 103.450 148.400 208.502 ;
        RECT 138.100 103.450 148.400 209.502 ;
        RECT 139.100 103.450 148.400 210.502 ;
        RECT 140.100 103.450 148.400 211.502 ;
        RECT 141.100 103.450 148.400 212.502 ;
        RECT 142.100 103.450 148.400 213.502 ;
        RECT 191.150 172.450 199.700 216.100 ;
        RECT 143.100 103.450 148.400 214.502 ;
        RECT 144.100 103.450 148.400 215.502 ;
        RECT 191.150 213.600 200.150 216.100 ;
        RECT 145.100 103.450 148.400 216.502 ;
        RECT 146.100 103.450 148.400 217.502 ;
        RECT 147.100 103.450 148.400 218.502 ;
        RECT 148.100 103.450 148.400 219.502 ;
        RECT 193.900 165.250 199.700 225.650 ;
        RECT 208.100 247.799 212.900 253.250 ;
        RECT 208.100 204.850 212.900 225.650 ;
        RECT 224.900 247.799 238.550 253.250 ;
        RECT 224.900 204.850 238.550 225.650 ;
        RECT 226.750 93.650 238.550 101.150 ;
      LAYER metal1 ;
        RECT 0.750 106.650 149.350 249.448 ;
        RECT 0.750 103.250 148.600 253.450 ;
        RECT 166.150 110.250 179.130 135.394 ;
        RECT 166.150 102.350 168.650 135.394 ;
        RECT 166.157 111.270 180.150 135.413 ;
        RECT 166.238 111.270 180.150 135.448 ;
        RECT 166.238 110.468 179.348 135.532 ;
        RECT 166.956 110.468 179.348 136.250 ;
        RECT 166.750 139.250 178.900 253.450 ;
        RECT 167.400 110.250 178.900 253.450 ;
        RECT 166.150 139.850 178.900 253.450 ;
        RECT 166.150 139.906 179.900 253.450 ;
        RECT 166.150 140.156 180.150 253.450 ;
        RECT 162.300 237.000 184.000 253.450 ;
        RECT 187.900 93.450 190.150 96.450 ;
        RECT 192.950 191.150 205.800 193.650 ;
        RECT 192.950 191.600 213.100 193.650 ;
        RECT 192.950 213.600 200.150 219.500 ;
        RECT 192.950 191.150 199.900 224.350 ;
        RECT 207.800 196.400 213.100 237.900 ;
        RECT 193.700 191.150 199.900 253.450 ;
        RECT 207.900 191.600 213.100 253.450 ;
        RECT 198.150 93.450 202.650 153.050 ;
        RECT 198.000 134.900 204.700 145.300 ;
        RECT 210.650 93.450 213.450 153.050 ;
        RECT 209.000 134.250 213.450 153.050 ;
        RECT 198.000 97.700 202.650 145.300 ;
        RECT 198.150 135.350 218.550 153.050 ;
        RECT 224.700 191.600 238.650 253.450 ;
        RECT 193.700 165.050 238.650 178.800 ;
        RECT 226.550 93.450 238.650 153.050 ;
      LAYER via1 ;
        RECT 0.750 0.750 238.650 304.150 ;
  END 
END IPAD20

MACRO IPAD2D
  CLASS  PAD ;
  FOREIGN IPAD2D 0.000 0.000 ;
  ORIGIN 0.000 0.000 ;
  SIZE 239.400 BY 304.900 ;
  SYMMETRY X Y R90  ;
  SITE IO ;
  PIN OUT1
    DIRECTION OUTPUT ;
    PORT
      LAYER metal2 ;
        RECT 208.800 104.100 211.300 193.650 ;
        RECT 210.850 0.000 213.350 109.600 ;
        RECT 207.800 191.150 211.300 193.650 ;
    END
  END OUT1
  PIN VSS
    DIRECTION INOUT ;
    USE GROUND ;
    SHAPE ABUTMENT ;
    PORT
      LAYER metal2 ;
        RECT 0.000 256.200 239.400 304.900 ;
      LAYER metal1 ;
        RECT 0.750 95.850 158.334 100.500 ;
        RECT 0.000 256.200 239.400 304.900 ;
        RECT 215.850 168.550 221.950 304.900 ;
        RECT 186.750 168.550 221.950 175.850 ;
        RECT 208.750 231.750 211.300 304.900 ;
        RECT 208.100 231.750 211.300 249.900 ;
        RECT 202.650 231.750 211.300 235.000 ;
        RECT 202.650 184.150 205.150 235.000 ;
        RECT 186.750 99.300 190.950 304.900 ;
        RECT 186.850 99.200 190.850 304.900 ;
        RECT 151.350 97.066 159.550 304.900 ;
        RECT 0.750 96.850 159.334 100.500 ;
    END
  END VSS
  PIN IN1
    DIRECTION INPUT ;
    PORT
      LAYER metal2 ;
        RECT 14.751 125.550 112.998 225.550 ;
        RECT 14.650 125.651 112.998 225.550 ;
        RECT 14.650 126.352 113.800 225.550 ;
        RECT 13.800 126.501 113.800 224.700 ;
        RECT 113.800 229.800 180.200 230.601 ;
        RECT 13.800 191.118 114.800 224.700 ;
        RECT 114.800 229.800 180.200 231.601 ;
        RECT 13.800 192.118 115.800 224.700 ;
        RECT 115.800 229.800 180.200 232.601 ;
        RECT 13.800 193.118 116.800 224.700 ;
        RECT 116.800 229.800 180.200 233.601 ;
        RECT 13.800 194.118 117.800 224.700 ;
        RECT 117.800 229.800 180.200 234.601 ;
        RECT 13.800 195.118 118.800 224.700 ;
        RECT 118.800 229.800 180.200 235.601 ;
        RECT 132.048 238.250 199.400 248.550 ;
        RECT 121.800 229.800 180.200 238.601 ;
        RECT 112.998 229.747 180.147 229.799 ;
        RECT 132.150 229.147 179.547 249.150 ;
        RECT 112.749 228.600 179.000 229.550 ;
        RECT 112.749 228.452 152.150 229.550 ;
        RECT 111.749 227.452 151.150 228.550 ;
        RECT 110.749 226.452 150.150 227.550 ;
        RECT 109.749 225.452 149.150 226.550 ;
        RECT 14.650 224.452 148.150 225.550 ;
        RECT 13.800 223.452 147.150 224.700 ;
        RECT 13.800 222.452 146.150 224.700 ;
        RECT 13.800 221.452 145.150 224.700 ;
        RECT 13.800 220.452 144.150 224.700 ;
        RECT 13.800 219.452 143.150 224.700 ;
        RECT 13.800 218.452 142.150 224.700 ;
        RECT 13.800 217.452 141.150 224.700 ;
        RECT 13.800 216.452 140.150 224.700 ;
        RECT 13.800 215.452 139.150 224.700 ;
        RECT 13.800 214.452 138.150 224.700 ;
        RECT 13.800 213.452 137.150 224.700 ;
        RECT 13.800 212.452 136.150 224.700 ;
        RECT 13.800 211.452 135.150 224.700 ;
        RECT 13.800 210.452 134.150 224.700 ;
        RECT 13.800 209.452 133.150 224.700 ;
        RECT 13.800 208.452 132.150 224.700 ;
        RECT 132.048 229.147 179.547 248.849 ;
        RECT 13.800 208.350 132.048 224.700 ;
        RECT 131.048 238.250 199.400 247.849 ;
        RECT 13.800 207.350 131.048 224.700 ;
        RECT 130.048 238.250 199.400 246.849 ;
        RECT 13.800 206.350 130.048 224.700 ;
        RECT 129.048 238.250 199.400 245.849 ;
        RECT 13.800 205.350 129.048 224.700 ;
        RECT 128.048 238.250 199.400 244.849 ;
        RECT 13.800 204.350 128.048 224.700 ;
        RECT 127.048 238.250 199.400 243.849 ;
        RECT 13.800 203.350 127.048 224.700 ;
        RECT 126.048 238.250 199.400 242.849 ;
        RECT 13.800 202.350 126.048 224.700 ;
        RECT 125.048 238.250 199.400 241.849 ;
        RECT 13.800 201.350 125.048 224.700 ;
        RECT 125.032 238.250 199.400 241.833 ;
        RECT 124.800 238.250 199.400 241.601 ;
        RECT 13.800 201.118 124.800 224.700 ;
        RECT 123.800 238.250 199.400 240.601 ;
        RECT 13.800 200.118 123.800 224.700 ;
        RECT 122.800 238.250 199.400 239.601 ;
        RECT 13.800 199.118 122.800 224.700 ;
        RECT 112.998 229.147 179.547 229.799 ;
        RECT 13.800 198.118 121.800 224.700 ;
        RECT 120.800 229.800 180.200 237.601 ;
        RECT 13.800 197.118 120.800 224.700 ;
        RECT 119.800 229.800 180.200 236.601 ;
        RECT 13.800 196.118 119.800 224.700 ;
    END
  END IN1
  PIN VDD
    DIRECTION INOUT ;
    USE POWER ;
    SHAPE ABUTMENT ;
    PORT
      LAYER metal1 ;
        RECT 161.150 0.000 164.197 233.850 ;
        RECT 0.000 0.000 239.400 90.700 ;
        RECT 221.300 0.000 223.800 162.300 ;
        RECT 216.200 0.000 218.700 132.600 ;
        RECT 205.400 0.000 207.900 132.600 ;
        RECT 192.900 0.000 195.400 162.300 ;
        RECT 182.053 0.000 185.150 233.900 ;
        RECT 182.053 0.000 184.800 234.250 ;
        RECT 181.650 0.000 185.150 233.847 ;
        RECT 170.652 0.000 185.150 108.750 ;
        RECT 170.150 0.000 185.150 108.248 ;
        RECT 161.150 0.000 164.650 233.797 ;
        RECT 161.550 0.000 164.197 234.250 ;
    END
    PORT
      CLASS CORE ;
      LAYER metal1 ;
        RECT 192.900 155.800 223.800 162.300 ;
    END
  END VDD
  OBS 
      LAYER metal2 ;
        RECT 0.850 228.500 106.799 253.250 ;
        RECT 167.600 111.198 167.702 225.650 ;
        RECT 167.600 111.700 178.700 225.650 ;
        RECT 182.497 251.500 183.800 253.250 ;
        RECT 188.100 93.650 189.950 96.250 ;
        RECT 193.900 251.500 205.150 253.250 ;
        RECT 193.900 252.850 205.800 253.250 ;
        RECT 166.150 104.750 193.900 108.300 ;
        RECT 166.150 102.350 168.650 108.950 ;
        RECT 0.850 104.850 168.600 109.000 ;
        RECT 0.850 104.850 167.600 109.550 ;
        RECT 0.850 104.850 149.800 121.749 ;
        RECT 0.850 104.850 149.400 122.149 ;
        RECT 0.850 103.450 148.400 122.600 ;
        RECT 115.948 103.450 148.400 123.402 ;
        RECT 198.350 93.650 202.450 152.850 ;
        RECT 198.350 135.550 205.850 152.850 ;
        RECT 190.900 165.250 205.850 165.600 ;
        RECT 190.900 178.800 205.850 181.200 ;
        RECT 190.900 138.300 200.400 181.400 ;
        RECT 116.750 103.450 148.400 188.168 ;
        RECT 117.750 103.450 148.400 189.168 ;
        RECT 118.750 103.450 148.400 190.168 ;
        RECT 119.750 103.450 148.400 191.168 ;
        RECT 120.750 103.450 148.400 192.168 ;
        RECT 121.750 103.450 148.400 193.168 ;
        RECT 122.750 103.450 148.400 194.168 ;
        RECT 123.750 103.450 148.400 195.168 ;
        RECT 124.750 103.450 148.400 196.168 ;
        RECT 125.750 103.450 148.400 197.168 ;
        RECT 126.750 103.450 148.400 198.168 ;
        RECT 190.900 104.750 193.900 200.850 ;
        RECT 127.750 103.450 148.400 198.400 ;
        RECT 127.998 103.450 148.400 199.400 ;
        RECT 128.998 103.450 148.400 200.400 ;
        RECT 190.900 198.350 200.150 200.850 ;
        RECT 129.998 103.450 148.400 201.400 ;
        RECT 130.998 103.450 148.400 202.400 ;
        RECT 131.998 103.450 148.400 203.400 ;
        RECT 132.998 103.450 148.400 204.400 ;
        RECT 133.998 103.450 148.400 205.400 ;
        RECT 134.998 103.450 148.400 205.502 ;
        RECT 135.100 103.450 148.400 206.502 ;
        RECT 136.100 103.450 148.400 207.502 ;
        RECT 137.100 103.450 148.400 208.502 ;
        RECT 138.100 103.450 148.400 209.502 ;
        RECT 139.100 103.450 148.400 210.502 ;
        RECT 140.100 103.450 148.400 211.502 ;
        RECT 141.100 103.450 148.400 212.502 ;
        RECT 142.100 103.450 148.400 213.502 ;
        RECT 143.100 103.450 148.400 214.502 ;
        RECT 144.100 103.450 148.400 215.502 ;
        RECT 145.100 103.450 148.400 216.502 ;
        RECT 146.100 103.450 148.400 217.502 ;
        RECT 147.100 103.450 148.400 218.502 ;
        RECT 148.100 103.450 148.400 219.502 ;
        RECT 180.950 128.850 185.150 225.050 ;
        RECT 193.900 138.300 199.700 225.650 ;
        RECT 180.950 221.600 199.700 225.050 ;
        RECT 192.300 221.600 194.800 231.350 ;
        RECT 192.300 228.250 195.500 231.350 ;
        RECT 224.900 252.850 238.550 253.250 ;
        RECT 226.750 93.650 238.550 101.150 ;
      LAYER metal1 ;
        RECT 0.750 106.650 149.350 249.448 ;
        RECT 0.750 103.250 148.600 253.450 ;
        RECT 166.150 110.250 179.130 135.394 ;
        RECT 166.150 102.350 168.650 135.394 ;
        RECT 166.157 111.270 180.150 135.413 ;
        RECT 166.238 111.270 180.150 135.448 ;
        RECT 166.238 110.468 179.348 135.532 ;
        RECT 166.956 110.468 179.348 136.250 ;
        RECT 166.750 139.250 178.900 253.450 ;
        RECT 167.400 110.250 178.900 253.450 ;
        RECT 166.150 139.850 178.900 253.450 ;
        RECT 166.150 139.906 179.900 253.450 ;
        RECT 166.150 140.156 180.150 253.450 ;
        RECT 162.300 237.000 184.000 253.450 ;
        RECT 187.900 93.450 190.150 96.450 ;
        RECT 207.800 184.150 210.300 229.650 ;
        RECT 193.700 178.600 213.100 181.400 ;
        RECT 192.950 198.350 200.150 204.250 ;
        RECT 192.950 178.900 199.900 209.100 ;
        RECT 192.800 228.250 199.900 231.350 ;
        RECT 193.700 178.600 199.900 253.450 ;
        RECT 193.700 237.750 205.350 253.450 ;
        RECT 193.700 252.650 206.000 253.450 ;
        RECT 193.750 178.600 199.400 253.950 ;
        RECT 198.150 93.450 202.650 153.050 ;
        RECT 198.000 134.900 204.700 145.300 ;
        RECT 210.650 93.450 213.450 153.050 ;
        RECT 209.000 134.250 213.450 153.050 ;
        RECT 198.000 97.700 202.650 145.300 ;
        RECT 198.150 135.350 218.550 153.050 ;
        RECT 224.700 252.650 238.650 253.450 ;
        RECT 224.700 178.600 238.650 181.400 ;
        RECT 193.700 165.050 238.650 165.800 ;
        RECT 226.550 93.450 238.650 153.050 ;
      LAYER via1 ;
        RECT 0.750 0.750 238.650 304.150 ;
  END 
END IPAD2D

MACRO IPAD2U
  CLASS  PAD ;
  FOREIGN IPAD2U 0.000 0.000 ;
  ORIGIN 0.000 0.000 ;
  SIZE 239.400 BY 304.900 ;
  SYMMETRY X Y R90  ;
  SITE IO ;
  PIN OUT1
    DIRECTION OUTPUT ;
    PORT
      LAYER metal2 ;
        RECT 210.800 104.100 213.300 217.150 ;
        RECT 210.850 0.000 213.350 109.600 ;
        RECT 207.800 214.650 213.300 217.150 ;
    END
  END OUT1
  PIN VSS
    DIRECTION INOUT ;
    USE GROUND ;
    SHAPE ABUTMENT ;
    PORT
      LAYER metal2 ;
        RECT 0.000 256.200 239.400 304.900 ;
      LAYER metal1 ;
        RECT 0.750 95.850 158.334 100.500 ;
        RECT 0.000 256.200 239.400 304.900 ;
        RECT 215.850 192.300 221.950 304.900 ;
        RECT 186.750 192.300 221.950 199.600 ;
        RECT 202.650 211.650 205.150 304.900 ;
        RECT 186.750 99.300 190.950 304.900 ;
        RECT 186.850 99.200 190.850 304.900 ;
        RECT 151.350 97.066 159.550 304.900 ;
        RECT 0.750 96.850 159.334 100.500 ;
    END
  END VSS
  PIN IN1
    DIRECTION INPUT ;
    PORT
      LAYER metal2 ;
        RECT 14.751 125.550 112.998 225.550 ;
        RECT 14.650 125.651 112.998 225.550 ;
        RECT 112.998 229.147 179.547 229.799 ;
        RECT 14.650 126.352 113.800 225.550 ;
        RECT 13.800 126.501 113.800 224.700 ;
        RECT 113.800 229.800 180.200 230.601 ;
        RECT 13.800 191.118 114.800 224.700 ;
        RECT 114.800 229.800 180.200 231.601 ;
        RECT 13.800 192.118 115.800 224.700 ;
        RECT 115.800 229.800 180.200 232.601 ;
        RECT 13.800 193.118 116.800 224.700 ;
        RECT 116.800 229.800 180.200 233.601 ;
        RECT 13.800 194.118 117.800 224.700 ;
        RECT 117.800 229.800 180.200 234.601 ;
        RECT 13.800 195.118 118.800 224.700 ;
        RECT 118.800 229.800 180.200 235.601 ;
        RECT 166.550 112.650 205.950 115.850 ;
        RECT 203.400 100.550 205.950 115.850 ;
        RECT 166.550 112.650 172.300 163.450 ;
        RECT 132.048 229.800 180.200 248.497 ;
        RECT 132.150 229.147 179.547 249.150 ;
        RECT 112.749 228.600 179.000 229.550 ;
        RECT 112.749 228.452 152.150 229.550 ;
        RECT 111.749 227.452 151.150 228.550 ;
        RECT 110.749 226.452 150.150 227.550 ;
        RECT 109.749 225.452 149.150 226.550 ;
        RECT 14.650 224.452 148.150 225.550 ;
        RECT 13.800 223.452 147.150 224.700 ;
        RECT 13.800 222.452 146.150 224.700 ;
        RECT 13.800 221.452 145.150 224.700 ;
        RECT 13.800 220.452 144.150 224.700 ;
        RECT 13.800 219.452 143.150 224.700 ;
        RECT 13.800 218.452 142.150 224.700 ;
        RECT 13.800 217.452 141.150 224.700 ;
        RECT 13.800 216.452 140.150 224.700 ;
        RECT 13.800 215.452 139.150 224.700 ;
        RECT 13.800 214.452 138.150 224.700 ;
        RECT 13.800 213.452 137.150 224.700 ;
        RECT 13.800 212.452 136.150 224.700 ;
        RECT 13.800 211.452 135.150 224.700 ;
        RECT 13.800 210.452 134.150 224.700 ;
        RECT 13.800 209.452 133.150 224.700 ;
        RECT 13.800 208.452 132.150 224.700 ;
        RECT 132.048 229.147 179.547 248.849 ;
        RECT 13.800 208.350 132.048 224.700 ;
        RECT 131.048 229.800 180.200 247.849 ;
        RECT 13.800 207.350 131.048 224.700 ;
        RECT 130.048 229.800 180.200 246.849 ;
        RECT 13.800 206.350 130.048 224.700 ;
        RECT 129.048 229.800 180.200 245.849 ;
        RECT 13.800 205.350 129.048 224.700 ;
        RECT 128.048 229.800 180.200 244.849 ;
        RECT 13.800 204.350 128.048 224.700 ;
        RECT 127.048 229.800 180.200 243.849 ;
        RECT 13.800 203.350 127.048 224.700 ;
        RECT 126.048 229.800 180.200 242.849 ;
        RECT 13.800 202.350 126.048 224.700 ;
        RECT 125.048 229.800 180.200 241.849 ;
        RECT 13.800 201.350 125.048 224.700 ;
        RECT 125.032 229.800 180.200 241.833 ;
        RECT 124.800 229.800 180.200 241.601 ;
        RECT 13.800 201.118 124.800 224.700 ;
        RECT 123.800 229.800 180.200 240.601 ;
        RECT 13.800 200.118 123.800 224.700 ;
        RECT 122.800 229.800 180.200 239.601 ;
        RECT 13.800 199.118 122.800 224.700 ;
        RECT 121.800 229.800 180.200 238.601 ;
        RECT 13.800 198.118 121.800 224.700 ;
        RECT 120.800 229.800 180.200 237.601 ;
        RECT 13.800 197.118 120.800 224.700 ;
        RECT 119.800 229.800 180.200 236.601 ;
        RECT 13.800 196.118 119.800 224.700 ;
    END
  END IN1
  PIN VDD
    DIRECTION INOUT ;
    USE POWER ;
    SHAPE ABUTMENT ;
    PORT
      LAYER metal1 ;
        RECT 161.150 0.000 164.197 233.850 ;
        RECT 0.000 0.000 239.400 90.700 ;
        RECT 221.300 0.000 223.800 174.450 ;
        RECT 216.200 0.000 218.700 151.350 ;
        RECT 205.400 110.650 218.700 114.500 ;
        RECT 205.400 110.650 207.900 151.350 ;
        RECT 192.900 0.000 195.400 174.450 ;
        RECT 182.053 0.000 185.150 233.900 ;
        RECT 182.053 0.000 184.800 234.250 ;
        RECT 181.650 0.000 185.150 233.847 ;
        RECT 170.652 0.000 185.150 108.750 ;
        RECT 170.150 0.000 185.150 108.248 ;
        RECT 161.150 0.000 164.650 233.797 ;
        RECT 161.550 0.000 164.197 234.250 ;
    END
    PORT
      CLASS CORE ;
      LAYER metal1 ;
        RECT 192.900 166.550 223.800 174.450 ;
    END
  END VDD
  OBS 
      LAYER metal2 ;
        RECT 0.850 228.500 106.799 253.250 ;
        RECT 166.150 102.350 168.650 108.950 ;
        RECT 0.850 104.850 168.050 109.550 ;
        RECT 0.850 104.850 149.800 121.750 ;
        RECT 0.850 104.850 149.400 122.150 ;
        RECT 0.850 103.450 148.400 122.600 ;
        RECT 115.948 103.450 148.400 123.402 ;
        RECT 116.750 103.450 148.400 188.168 ;
        RECT 117.750 103.450 148.400 189.168 ;
        RECT 118.750 103.450 148.400 190.168 ;
        RECT 119.750 103.450 148.400 191.168 ;
        RECT 120.750 103.450 148.400 192.168 ;
        RECT 121.750 103.450 148.400 193.168 ;
        RECT 122.750 103.450 148.400 194.168 ;
        RECT 123.750 103.450 148.400 195.168 ;
        RECT 124.750 103.450 148.400 196.168 ;
        RECT 125.750 103.450 148.400 197.168 ;
        RECT 126.750 103.450 148.400 198.168 ;
        RECT 127.750 103.450 148.400 198.400 ;
        RECT 127.998 103.450 148.400 199.400 ;
        RECT 128.998 103.450 148.400 200.400 ;
        RECT 129.998 103.450 148.400 201.400 ;
        RECT 130.998 103.450 148.400 202.400 ;
        RECT 131.998 103.450 148.400 203.400 ;
        RECT 132.998 103.450 148.400 204.400 ;
        RECT 133.998 103.450 148.400 205.400 ;
        RECT 134.998 103.450 148.400 205.502 ;
        RECT 135.100 103.450 148.400 206.502 ;
        RECT 136.100 103.450 148.400 207.502 ;
        RECT 137.100 103.450 148.400 208.502 ;
        RECT 138.100 103.450 148.400 209.502 ;
        RECT 139.100 103.450 148.400 210.502 ;
        RECT 140.100 103.450 148.400 211.502 ;
        RECT 141.100 103.450 148.400 212.502 ;
        RECT 142.100 103.450 148.400 213.502 ;
        RECT 143.100 103.450 148.400 214.502 ;
        RECT 144.100 103.450 148.400 215.502 ;
        RECT 145.100 103.450 148.400 216.502 ;
        RECT 146.100 103.450 148.400 217.502 ;
        RECT 147.100 103.450 148.400 218.502 ;
        RECT 148.100 103.450 148.400 219.502 ;
        RECT 167.600 166.400 178.700 225.650 ;
        RECT 183.150 247.799 183.800 253.250 ;
        RECT 193.900 247.799 199.700 253.250 ;
        RECT 174.800 123.500 193.900 134.250 ;
        RECT 190.900 157.050 204.700 159.550 ;
        RECT 197.900 161.550 205.450 164.050 ;
        RECT 190.900 177.400 207.850 189.350 ;
        RECT 190.900 202.550 207.850 208.700 ;
        RECT 197.900 161.550 200.400 208.900 ;
        RECT 190.900 177.400 199.700 225.650 ;
        RECT 190.900 123.500 193.900 231.350 ;
        RECT 190.900 228.850 200.150 231.350 ;
        RECT 186.750 92.650 199.900 95.150 ;
        RECT 198.350 93.650 207.900 97.600 ;
        RECT 186.750 92.650 190.950 108.850 ;
        RECT 198.350 93.650 200.450 109.700 ;
        RECT 208.100 247.799 212.900 253.250 ;
        RECT 208.100 220.100 212.900 225.650 ;
        RECT 224.900 247.799 238.550 253.250 ;
        RECT 224.900 220.100 238.550 225.650 ;
        RECT 226.750 93.650 238.550 97.600 ;
      LAYER metal1 ;
        RECT 0.750 106.650 149.350 249.448 ;
        RECT 0.750 103.250 148.600 253.450 ;
        RECT 166.150 110.250 179.130 135.394 ;
        RECT 166.150 102.350 168.650 135.394 ;
        RECT 166.157 111.270 180.150 135.413 ;
        RECT 166.238 111.270 180.150 135.448 ;
        RECT 166.238 110.468 179.348 135.532 ;
        RECT 166.956 110.468 179.348 136.250 ;
        RECT 166.750 139.250 178.900 253.450 ;
        RECT 167.400 110.250 178.900 253.450 ;
        RECT 166.150 139.850 178.900 253.450 ;
        RECT 166.150 139.906 179.900 253.450 ;
        RECT 166.150 140.156 180.150 253.450 ;
        RECT 162.300 237.000 184.000 253.450 ;
        RECT 187.900 93.450 190.150 96.450 ;
        RECT 193.700 202.350 213.100 208.900 ;
        RECT 192.950 228.850 200.150 236.750 ;
        RECT 192.950 206.400 199.900 241.600 ;
        RECT 207.800 211.650 213.100 253.150 ;
        RECT 193.700 202.350 199.900 253.450 ;
        RECT 207.900 202.350 213.100 253.450 ;
        RECT 210.800 116.850 213.300 149.750 ;
        RECT 197.400 92.650 203.300 95.150 ;
        RECT 198.150 93.450 213.450 107.900 ;
        RECT 198.150 93.450 205.950 108.900 ;
        RECT 198.150 92.650 202.650 164.050 ;
        RECT 198.000 116.450 202.650 164.050 ;
        RECT 198.000 153.650 204.700 164.050 ;
        RECT 198.000 154.100 218.550 163.800 ;
        RECT 209.000 153.000 211.500 164.050 ;
        RECT 198.000 154.100 211.500 164.050 ;
        RECT 224.700 202.350 238.650 253.450 ;
        RECT 193.700 177.200 238.650 189.550 ;
        RECT 226.550 154.100 238.650 163.800 ;
        RECT 226.550 93.450 238.650 107.900 ;
      LAYER via1 ;
        RECT 0.750 0.750 238.650 304.150 ;
  END 
END IPAD2U

MACRO IPAD30
  CLASS  PAD ;
  FOREIGN IPAD30 0.000 0.000 ;
  ORIGIN 0.000 0.000 ;
  SIZE 239.400 BY 304.900 ;
  SYMMETRY X Y R90  ;
  SITE IO ;
  PIN OUT1
    DIRECTION OUTPUT ;
    PORT
      LAYER metal2 ;
        RECT 216.300 177.900 218.800 202.500 ;
        RECT 216.300 177.900 221.750 180.450 ;
        RECT 219.250 0.000 221.750 180.450 ;
    END
  END OUT1
  PIN VSS
    DIRECTION INOUT ;
    USE GROUND ;
    SHAPE ABUTMENT ;
    PORT
      LAYER metal2 ;
        RECT 0.000 256.200 239.400 304.900 ;
      LAYER metal1 ;
        RECT 1.272 95.850 158.334 100.463 ;
        RECT 0.000 256.200 239.400 304.900 ;
        RECT 223.200 222.200 227.200 304.900 ;
        RECT 224.700 205.000 227.200 304.900 ;
        RECT 186.750 204.800 214.800 207.300 ;
        RECT 203.050 255.000 211.550 304.900 ;
        RECT 186.750 99.300 190.950 304.900 ;
        RECT 186.850 99.200 190.850 304.900 ;
        RECT 151.350 97.066 159.550 304.900 ;
        RECT 0.750 96.850 159.334 99.941 ;
        RECT 0.750 96.372 158.334 99.941 ;
        RECT 1.309 97.066 159.550 100.500 ;
    END
  END VSS
  PIN IN1
    DIRECTION INPUT ;
    PORT
      LAYER metal2 ;
        RECT 14.751 125.550 112.998 225.550 ;
        RECT 14.650 125.651 112.998 225.550 ;
        RECT 112.998 229.147 179.547 229.799 ;
        RECT 14.650 126.352 113.800 225.550 ;
        RECT 13.800 126.501 113.800 224.700 ;
        RECT 113.800 229.800 180.200 230.601 ;
        RECT 13.800 191.118 114.800 224.700 ;
        RECT 114.800 229.800 180.200 231.601 ;
        RECT 13.800 192.118 115.800 224.700 ;
        RECT 115.800 229.800 180.200 232.601 ;
        RECT 13.800 193.118 116.800 224.700 ;
        RECT 116.800 229.800 180.200 233.601 ;
        RECT 13.800 194.118 117.800 224.700 ;
        RECT 117.800 229.800 180.200 234.601 ;
        RECT 13.800 195.118 118.800 224.700 ;
        RECT 118.800 229.800 180.200 235.601 ;
        RECT 132.048 229.800 180.200 248.497 ;
        RECT 132.150 229.147 179.547 249.150 ;
        RECT 112.749 228.600 179.000 229.550 ;
        RECT 112.749 228.452 152.150 229.550 ;
        RECT 111.749 227.452 151.150 228.550 ;
        RECT 110.749 226.452 150.150 227.550 ;
        RECT 109.749 225.452 149.150 226.550 ;
        RECT 14.650 224.452 148.150 225.550 ;
        RECT 13.800 223.452 147.150 224.700 ;
        RECT 13.800 222.452 146.150 224.700 ;
        RECT 13.800 221.452 145.150 224.700 ;
        RECT 13.800 220.452 144.150 224.700 ;
        RECT 13.800 219.452 143.150 224.700 ;
        RECT 13.800 218.452 142.150 224.700 ;
        RECT 13.800 217.452 141.150 224.700 ;
        RECT 13.800 216.452 140.150 224.700 ;
        RECT 13.800 215.452 139.150 224.700 ;
        RECT 13.800 214.452 138.150 224.700 ;
        RECT 13.800 213.452 137.150 224.700 ;
        RECT 13.800 212.452 136.150 224.700 ;
        RECT 13.800 211.452 135.150 224.700 ;
        RECT 13.800 210.452 134.150 224.700 ;
        RECT 13.800 209.452 133.150 224.700 ;
        RECT 13.800 208.452 132.150 224.700 ;
        RECT 132.048 229.147 179.547 248.849 ;
        RECT 13.800 208.350 132.048 224.700 ;
        RECT 131.048 229.800 180.200 247.849 ;
        RECT 13.800 207.350 131.048 224.700 ;
        RECT 130.048 229.800 180.200 246.849 ;
        RECT 13.800 206.350 130.048 224.700 ;
        RECT 129.048 229.800 180.200 245.849 ;
        RECT 13.800 205.350 129.048 224.700 ;
        RECT 128.048 229.800 180.200 244.849 ;
        RECT 13.800 204.350 128.048 224.700 ;
        RECT 127.048 229.800 180.200 243.849 ;
        RECT 13.800 203.350 127.048 224.700 ;
        RECT 126.048 229.800 180.200 242.849 ;
        RECT 13.800 202.350 126.048 224.700 ;
        RECT 125.048 229.800 180.200 241.849 ;
        RECT 13.800 201.350 125.048 224.700 ;
        RECT 125.032 229.800 180.200 241.833 ;
        RECT 124.800 229.800 180.200 241.601 ;
        RECT 13.800 201.118 124.800 224.700 ;
        RECT 123.800 229.800 180.200 240.601 ;
        RECT 13.800 200.118 123.800 224.700 ;
        RECT 122.800 229.800 180.200 239.601 ;
        RECT 13.800 199.118 122.800 224.700 ;
        RECT 121.800 229.800 180.200 238.601 ;
        RECT 13.800 198.118 121.800 224.700 ;
        RECT 120.800 229.800 180.200 237.601 ;
        RECT 13.800 197.118 120.800 224.700 ;
        RECT 119.800 229.800 180.200 236.601 ;
        RECT 13.800 196.118 119.800 224.700 ;
    END
  END IN1
  PIN VDD
    DIRECTION INOUT ;
    USE POWER ;
    SHAPE ABUTMENT ;
    PORT
      LAYER metal1 ;
        RECT 161.150 0.000 164.197 233.850 ;
        RECT 0.000 0.000 239.400 90.700 ;
        RECT 192.850 0.000 228.150 91.001 ;
        RECT 224.650 0.000 227.150 201.550 ;
        RECT 224.299 0.000 227.150 95.900 ;
        RECT 192.850 0.000 227.150 94.900 ;
        RECT 192.850 0.000 195.350 202.300 ;
        RECT 182.053 0.000 185.150 233.900 ;
        RECT 182.053 0.000 184.800 234.250 ;
        RECT 181.650 0.000 185.150 233.847 ;
        RECT 170.652 0.000 185.150 108.750 ;
        RECT 170.150 0.000 185.150 108.248 ;
        RECT 161.150 0.000 164.650 233.797 ;
        RECT 161.550 0.000 164.197 234.250 ;
    END
    PORT
      CLASS CORE ;
      LAYER metal1 ;
        RECT 192.850 199.800 213.350 202.300 ;
    END
  END VDD
  OBS 
      LAYER metal2 ;
        RECT 0.850 228.500 106.799 253.250 ;
        RECT 167.600 111.198 167.702 225.650 ;
        RECT 167.600 111.700 178.700 225.650 ;
        RECT 183.150 247.799 183.800 253.250 ;
        RECT 188.100 93.650 189.900 96.250 ;
        RECT 201.050 86.650 203.550 252.050 ;
        RECT 188.196 103.750 216.300 108.300 ;
        RECT 188.350 103.500 216.300 108.300 ;
        RECT 166.150 104.750 216.300 108.300 ;
        RECT 188.950 102.900 216.300 108.300 ;
        RECT 166.150 102.350 168.650 108.950 ;
        RECT 0.850 104.850 168.600 109.000 ;
        RECT 0.850 104.850 167.600 109.550 ;
        RECT 0.850 104.850 149.800 121.899 ;
        RECT 0.850 104.850 149.400 122.299 ;
        RECT 0.850 103.450 148.400 122.600 ;
        RECT 115.948 103.450 148.400 123.402 ;
        RECT 198.300 97.850 216.300 174.950 ;
        RECT 190.650 173.950 216.150 176.100 ;
        RECT 116.750 103.450 148.400 188.168 ;
        RECT 117.750 103.450 148.400 189.168 ;
        RECT 118.750 103.450 148.400 190.168 ;
        RECT 119.750 103.450 148.400 191.168 ;
        RECT 120.750 103.450 148.400 192.168 ;
        RECT 121.750 103.450 148.400 193.168 ;
        RECT 122.750 103.450 148.400 194.168 ;
        RECT 123.750 103.450 148.400 195.168 ;
        RECT 124.750 103.450 148.400 196.168 ;
        RECT 190.650 173.950 213.350 196.850 ;
        RECT 125.750 103.450 148.400 197.168 ;
        RECT 126.750 103.450 148.400 198.168 ;
        RECT 127.750 103.450 148.400 198.400 ;
        RECT 127.998 103.450 148.400 199.400 ;
        RECT 128.998 103.450 148.400 200.400 ;
        RECT 129.998 103.450 148.400 201.400 ;
        RECT 130.998 103.450 148.400 202.400 ;
        RECT 131.998 103.450 148.400 203.400 ;
        RECT 132.998 103.450 148.400 204.400 ;
        RECT 133.998 103.450 148.400 205.400 ;
        RECT 134.998 103.450 148.400 205.502 ;
        RECT 135.100 103.450 148.400 206.502 ;
        RECT 136.100 103.450 148.400 207.502 ;
        RECT 137.100 103.450 148.400 208.502 ;
        RECT 138.100 103.450 148.400 209.502 ;
        RECT 206.300 86.650 208.800 252.050 ;
        RECT 190.650 173.950 208.800 225.650 ;
        RECT 139.100 103.450 148.400 210.502 ;
        RECT 140.100 103.450 148.400 211.502 ;
        RECT 141.100 103.450 148.400 212.502 ;
        RECT 142.100 103.450 148.400 213.502 ;
        RECT 143.100 103.450 148.400 214.502 ;
        RECT 144.100 103.450 148.400 215.502 ;
        RECT 145.100 103.450 148.400 216.502 ;
        RECT 146.100 103.450 148.400 217.502 ;
        RECT 147.100 103.450 148.400 218.502 ;
        RECT 190.650 210.250 221.750 219.250 ;
        RECT 148.100 103.450 148.400 219.502 ;
        RECT 190.650 210.250 220.250 225.650 ;
        RECT 190.650 173.950 195.400 226.950 ;
        RECT 212.400 210.250 214.900 245.400 ;
        RECT 201.000 210.250 209.100 252.050 ;
        RECT 193.900 247.799 220.250 252.050 ;
        RECT 193.900 247.799 203.500 253.250 ;
        RECT 214.500 247.799 220.250 253.250 ;
        RECT 230.150 247.799 238.550 253.250 ;
        RECT 230.150 210.250 238.550 225.650 ;
        RECT 231.100 93.650 238.550 174.950 ;
        RECT 230.100 93.951 238.550 174.950 ;
      LAYER metal1 ;
        RECT 0.750 106.650 149.350 249.448 ;
        RECT 0.750 103.250 148.600 253.450 ;
        RECT 166.150 110.250 179.130 135.394 ;
        RECT 166.150 102.350 168.650 135.394 ;
        RECT 166.157 111.270 180.150 135.413 ;
        RECT 166.238 111.270 180.150 135.448 ;
        RECT 166.238 110.468 179.348 135.532 ;
        RECT 166.956 110.468 179.348 136.250 ;
        RECT 166.750 139.250 178.900 253.450 ;
        RECT 167.400 110.250 178.900 253.450 ;
        RECT 166.150 139.850 178.900 253.450 ;
        RECT 166.150 139.906 179.900 253.450 ;
        RECT 166.150 140.156 180.150 253.450 ;
        RECT 162.300 237.000 184.000 253.450 ;
        RECT 187.900 93.450 190.100 96.450 ;
        RECT 196.850 98.650 221.900 176.450 ;
        RECT 196.850 96.400 199.400 176.450 ;
        RECT 198.100 97.650 221.549 197.300 ;
        RECT 201.800 96.500 216.550 197.300 ;
        RECT 196.900 183.300 223.100 197.300 ;
        RECT 216.300 112.700 223.100 218.700 ;
        RECT 192.900 209.700 221.950 219.450 ;
        RECT 192.900 209.700 220.800 222.400 ;
        RECT 216.300 97.650 220.800 242.900 ;
        RECT 193.700 209.700 220.450 252.250 ;
        RECT 192.900 224.400 200.300 253.450 ;
        RECT 214.300 209.700 220.450 253.450 ;
        RECT 192.900 224.400 195.400 254.250 ;
        RECT 197.150 209.700 200.050 254.650 ;
        RECT 214.900 209.700 218.150 254.700 ;
        RECT 229.950 210.050 238.650 253.450 ;
        RECT 230.900 93.450 238.650 197.050 ;
        RECT 229.900 93.751 238.650 197.050 ;
      LAYER via1 ;
        RECT 0.750 0.750 238.650 304.150 ;
  END 
END IPAD30

MACRO IPAD3D
  CLASS  PAD ;
  FOREIGN IPAD3D 0.000 0.000 ;
  ORIGIN 0.000 0.000 ;
  SIZE 239.400 BY 304.900 ;
  SYMMETRY X Y R90  ;
  SITE IO ;
  PIN OUT1
    DIRECTION OUTPUT ;
    PORT
      LAYER metal2 ;
        RECT 216.300 177.900 218.800 202.500 ;
        RECT 216.300 177.900 221.750 180.450 ;
        RECT 219.250 0.000 221.750 180.450 ;
    END
  END OUT1
  PIN VSS
    DIRECTION INOUT ;
    USE GROUND ;
    SHAPE ABUTMENT ;
    PORT
      LAYER metal2 ;
        RECT 0.000 256.200 239.400 304.900 ;
      LAYER metal1 ;
        RECT 1.352 95.850 158.334 100.500 ;
        RECT 0.000 256.200 239.400 304.900 ;
        RECT 223.200 222.200 227.200 304.900 ;
        RECT 224.700 205.000 227.200 304.900 ;
        RECT 186.750 204.800 214.800 207.300 ;
        RECT 203.050 255.000 211.550 304.900 ;
        RECT 186.750 99.300 190.950 304.900 ;
        RECT 186.850 99.200 190.850 304.900 ;
        RECT 181.250 252.800 184.150 304.900 ;
        RECT 151.350 97.066 159.550 304.900 ;
        RECT 0.750 96.850 159.334 99.898 ;
        RECT 0.750 96.452 158.334 99.898 ;
        RECT 151.250 97.066 159.550 101.500 ;
    END
  END VSS
  PIN IN1
    DIRECTION INPUT ;
    PORT
      LAYER metal2 ;
        RECT 14.751 125.550 112.998 225.550 ;
        RECT 14.650 125.651 112.998 225.550 ;
        RECT 112.998 229.147 179.547 229.799 ;
        RECT 14.650 126.352 113.800 225.550 ;
        RECT 13.800 126.501 113.800 224.700 ;
        RECT 113.800 229.800 180.200 230.601 ;
        RECT 13.800 191.118 114.800 224.700 ;
        RECT 114.800 229.800 180.200 231.601 ;
        RECT 13.800 192.118 115.800 224.700 ;
        RECT 128.048 238.300 184.650 244.300 ;
        RECT 132.048 229.800 180.200 248.497 ;
        RECT 132.150 229.147 179.547 249.150 ;
        RECT 112.749 228.600 179.000 229.550 ;
        RECT 112.749 228.452 152.150 229.550 ;
        RECT 111.749 227.452 151.150 228.550 ;
        RECT 110.749 226.452 150.150 227.550 ;
        RECT 109.749 225.452 149.150 226.550 ;
        RECT 14.650 224.452 148.150 225.550 ;
        RECT 13.800 223.452 147.150 224.700 ;
        RECT 13.800 222.452 146.150 224.700 ;
        RECT 13.800 221.452 145.150 224.700 ;
        RECT 13.800 220.452 144.150 224.700 ;
        RECT 13.800 219.452 143.150 224.700 ;
        RECT 13.800 218.452 142.150 224.700 ;
        RECT 13.800 217.452 141.150 224.700 ;
        RECT 13.800 216.452 140.150 224.700 ;
        RECT 13.800 215.452 139.150 224.700 ;
        RECT 13.800 214.452 138.150 224.700 ;
        RECT 13.800 213.452 137.150 224.700 ;
        RECT 13.800 212.452 136.150 224.700 ;
        RECT 13.800 211.452 135.150 224.700 ;
        RECT 13.800 210.452 134.150 224.700 ;
        RECT 13.800 209.452 133.150 224.700 ;
        RECT 13.800 208.452 132.150 224.700 ;
        RECT 132.048 229.147 179.547 248.849 ;
        RECT 13.800 208.350 132.048 224.700 ;
        RECT 131.048 229.800 180.200 247.849 ;
        RECT 13.800 207.350 131.048 224.700 ;
        RECT 130.048 229.800 180.200 246.849 ;
        RECT 13.800 206.350 130.048 224.700 ;
        RECT 129.048 229.800 180.200 245.849 ;
        RECT 13.800 205.350 129.048 224.700 ;
        RECT 128.048 229.800 180.200 244.849 ;
        RECT 127.048 204.350 128.048 243.849 ;
        RECT 126.048 203.350 127.048 242.849 ;
        RECT 125.048 202.350 126.048 241.849 ;
        RECT 125.032 238.300 184.650 241.833 ;
        RECT 124.800 201.350 125.048 241.601 ;
        RECT 123.800 201.118 124.800 240.601 ;
        RECT 122.800 200.118 123.800 239.601 ;
        RECT 121.800 199.118 122.800 238.601 ;
        RECT 13.800 198.118 121.800 224.700 ;
        RECT 120.800 229.800 180.200 237.601 ;
        RECT 13.800 197.118 120.800 224.700 ;
        RECT 119.800 229.800 180.200 236.601 ;
        RECT 13.800 196.118 119.800 224.700 ;
        RECT 118.800 229.800 180.200 235.601 ;
        RECT 13.800 195.118 118.800 224.700 ;
        RECT 117.800 229.800 180.200 234.601 ;
        RECT 13.800 194.118 117.800 224.700 ;
        RECT 116.800 229.800 180.200 233.601 ;
        RECT 13.800 193.118 116.800 224.700 ;
        RECT 115.800 229.800 180.200 232.601 ;
    END
  END IN1
  PIN VDD
    DIRECTION INOUT ;
    USE POWER ;
    SHAPE ABUTMENT ;
    PORT
      LAYER metal1 ;
        RECT 161.150 0.000 164.197 233.850 ;
        RECT 0.000 0.000 239.400 90.700 ;
        RECT 192.850 0.000 228.150 91.001 ;
        RECT 224.650 0.000 227.150 201.550 ;
        RECT 224.299 0.000 227.150 95.900 ;
        RECT 192.850 0.000 227.150 94.900 ;
        RECT 192.850 178.150 198.600 180.650 ;
        RECT 192.850 0.000 195.350 202.300 ;
        RECT 182.053 0.000 185.150 233.900 ;
        RECT 182.053 0.000 184.800 234.250 ;
        RECT 181.650 0.000 185.150 233.847 ;
        RECT 170.652 0.000 185.150 108.750 ;
        RECT 170.150 0.000 185.150 108.248 ;
        RECT 161.150 0.000 164.650 233.797 ;
        RECT 161.550 0.000 164.197 234.250 ;
    END
    PORT
      CLASS CORE ;
      LAYER metal1 ;
        RECT 192.850 199.800 213.350 202.300 ;
    END
  END VDD
  OBS 
      LAYER metal2 ;
        RECT 0.850 228.500 106.799 253.250 ;
        RECT 167.600 111.198 167.702 225.650 ;
        RECT 167.600 111.700 178.700 225.650 ;
        RECT 188.100 93.650 189.900 94.116 ;
        RECT 201.050 86.650 203.550 252.050 ;
        RECT 188.350 103.452 199.350 108.300 ;
        RECT 166.150 104.750 216.300 108.300 ;
        RECT 188.902 102.900 199.350 108.300 ;
        RECT 166.150 102.350 168.650 108.950 ;
        RECT 0.850 104.850 168.600 109.000 ;
        RECT 0.850 104.850 167.600 109.550 ;
        RECT 0.850 104.850 149.800 122.400 ;
        RECT 0.850 103.450 148.300 122.600 ;
        RECT 115.948 104.850 149.150 123.050 ;
        RECT 115.948 104.450 148.400 123.402 ;
        RECT 198.300 104.450 216.300 174.950 ;
        RECT 190.650 173.950 216.150 175.200 ;
        RECT 212.850 104.450 216.150 176.100 ;
        RECT 116.750 104.450 148.400 188.168 ;
        RECT 117.750 104.450 148.400 189.168 ;
        RECT 118.750 104.450 148.400 190.168 ;
        RECT 119.750 104.450 148.400 191.168 ;
        RECT 120.750 104.450 148.400 192.168 ;
        RECT 121.750 104.450 148.400 193.168 ;
        RECT 122.750 104.450 148.400 194.168 ;
        RECT 123.750 104.450 148.400 195.168 ;
        RECT 124.750 104.450 148.400 196.168 ;
        RECT 190.650 183.600 213.350 196.850 ;
        RECT 125.750 104.450 148.400 197.168 ;
        RECT 126.750 104.450 148.400 198.168 ;
        RECT 127.750 104.450 148.400 198.400 ;
        RECT 127.998 104.450 148.400 199.400 ;
        RECT 128.998 104.450 148.400 200.400 ;
        RECT 129.998 104.450 148.400 201.400 ;
        RECT 130.998 104.450 148.400 202.400 ;
        RECT 131.998 104.450 148.400 203.400 ;
        RECT 132.998 104.450 148.400 204.400 ;
        RECT 133.998 104.450 148.400 205.400 ;
        RECT 134.998 104.450 148.400 205.502 ;
        RECT 135.100 104.450 148.400 206.502 ;
        RECT 136.100 104.450 148.400 207.502 ;
        RECT 137.100 104.450 148.400 208.502 ;
        RECT 138.100 104.450 148.400 209.502 ;
        RECT 206.300 86.650 208.800 252.050 ;
        RECT 190.650 173.950 208.800 225.650 ;
        RECT 139.100 104.450 148.400 210.502 ;
        RECT 140.100 104.450 148.400 211.502 ;
        RECT 141.100 104.450 148.400 212.502 ;
        RECT 142.100 104.450 148.400 213.502 ;
        RECT 143.100 104.450 148.400 214.502 ;
        RECT 144.100 104.450 148.400 215.502 ;
        RECT 145.100 104.450 148.400 216.502 ;
        RECT 146.100 104.450 148.400 217.502 ;
        RECT 147.100 104.450 148.400 218.502 ;
        RECT 190.650 210.250 221.750 219.250 ;
        RECT 148.100 104.450 148.400 219.502 ;
        RECT 190.650 210.250 220.250 225.650 ;
        RECT 190.650 173.950 195.000 226.950 ;
        RECT 212.400 210.250 214.900 245.400 ;
        RECT 196.750 210.250 209.100 252.050 ;
        RECT 183.150 247.799 183.800 253.550 ;
        RECT 193.900 247.799 220.250 252.050 ;
        RECT 171.850 251.050 203.500 253.250 ;
        RECT 214.500 247.799 220.250 253.250 ;
        RECT 171.850 251.050 199.300 253.550 ;
        RECT 230.150 247.799 238.550 253.250 ;
        RECT 230.150 210.250 238.550 225.650 ;
        RECT 230.100 104.450 238.550 174.950 ;
        RECT 231.100 93.650 238.550 94.116 ;
        RECT 230.100 93.951 238.550 94.116 ;
      LAYER metal1 ;
        RECT 0.750 103.250 148.500 253.450 ;
        RECT 0.750 106.650 149.350 249.448 ;
        RECT 0.750 104.250 148.600 253.450 ;
        RECT 166.150 110.250 179.130 135.394 ;
        RECT 166.150 102.350 168.650 135.394 ;
        RECT 166.157 111.270 180.150 135.413 ;
        RECT 166.238 111.270 180.150 135.448 ;
        RECT 166.238 110.468 179.348 135.532 ;
        RECT 166.956 110.468 179.348 136.250 ;
        RECT 166.750 139.250 178.900 250.050 ;
        RECT 167.400 110.250 178.900 250.050 ;
        RECT 166.150 139.850 178.900 250.050 ;
        RECT 166.150 139.906 179.900 250.050 ;
        RECT 166.150 140.156 180.150 250.050 ;
        RECT 162.300 237.900 184.600 244.000 ;
        RECT 162.300 237.000 184.000 250.050 ;
        RECT 162.300 237.000 178.800 253.450 ;
        RECT 171.850 110.250 178.800 253.550 ;
        RECT 187.900 93.450 190.100 94.316 ;
        RECT 200.300 178.150 217.800 181.100 ;
        RECT 201.800 96.500 216.550 99.600 ;
        RECT 196.850 96.400 199.400 175.400 ;
        RECT 201.050 102.900 212.550 175.400 ;
        RECT 214.050 96.500 216.550 176.100 ;
        RECT 196.850 104.250 221.900 175.400 ;
        RECT 201.500 104.250 219.000 176.100 ;
        RECT 196.850 96.400 199.350 176.450 ;
        RECT 196.900 183.300 218.800 197.300 ;
        RECT 220.600 112.700 223.100 218.700 ;
        RECT 192.900 209.700 221.950 219.450 ;
        RECT 192.900 209.700 220.800 222.400 ;
        RECT 216.300 183.400 220.800 242.900 ;
        RECT 192.450 224.400 220.800 226.950 ;
        RECT 193.700 209.700 220.450 252.250 ;
        RECT 192.900 224.400 200.300 253.450 ;
        RECT 214.300 209.700 220.450 253.450 ;
        RECT 192.900 224.400 195.400 254.250 ;
        RECT 197.150 209.700 200.050 254.650 ;
        RECT 214.900 209.700 218.150 254.700 ;
        RECT 229.950 210.050 238.650 253.450 ;
        RECT 229.900 183.400 238.650 197.050 ;
        RECT 229.900 104.250 238.650 175.400 ;
        RECT 230.900 93.450 238.650 94.316 ;
        RECT 229.900 93.751 238.650 94.316 ;
      LAYER via1 ;
        RECT 0.750 0.750 238.650 304.150 ;
  END 
END IPAD3D

MACRO IPAD3U
  CLASS  PAD ;
  FOREIGN IPAD3U 0.000 0.000 ;
  ORIGIN 0.000 0.000 ;
  SIZE 239.400 BY 304.900 ;
  SYMMETRY X Y R90  ;
  SITE IO ;
  PIN OUT1
    DIRECTION OUTPUT ;
    PORT
      LAYER metal2 ;
        RECT 216.300 187.850 218.800 202.500 ;
        RECT 216.300 187.850 225.950 190.400 ;
        RECT 223.450 0.000 225.950 190.400 ;
    END
  END OUT1
  PIN VSS
    DIRECTION INOUT ;
    USE GROUND ;
    SHAPE ABUTMENT ;
    PORT
      LAYER metal2 ;
        RECT 0.000 256.200 239.400 304.900 ;
      LAYER metal1 ;
        RECT 1.358 95.850 158.334 100.476 ;
        RECT 0.000 256.200 239.400 304.900 ;
        RECT 223.200 222.200 227.200 304.900 ;
        RECT 224.700 205.000 227.200 304.900 ;
        RECT 186.750 204.800 214.800 207.300 ;
        RECT 203.050 255.000 211.550 304.900 ;
        RECT 186.750 99.300 190.950 304.900 ;
        RECT 186.850 99.200 190.850 304.900 ;
        RECT 151.350 97.066 159.550 304.900 ;
        RECT 0.750 96.850 159.334 99.868 ;
        RECT 0.750 96.458 158.334 99.868 ;
        RECT 1.382 97.066 159.550 100.500 ;
    END
  END VSS
  PIN IN1
    DIRECTION INPUT ;
    PORT
      LAYER metal2 ;
        RECT 14.751 125.550 112.998 225.550 ;
        RECT 14.650 125.651 112.998 225.550 ;
        RECT 112.998 229.147 179.547 229.799 ;
        RECT 14.650 126.352 113.800 225.550 ;
        RECT 13.800 126.501 113.800 224.700 ;
        RECT 113.800 229.800 180.200 230.601 ;
        RECT 13.800 191.118 114.800 224.700 ;
        RECT 114.800 229.800 180.200 231.601 ;
        RECT 13.800 192.118 115.800 224.700 ;
        RECT 115.800 229.800 180.200 232.601 ;
        RECT 13.800 193.118 116.800 224.700 ;
        RECT 116.800 229.800 180.200 233.601 ;
        RECT 13.800 194.118 117.800 224.700 ;
        RECT 117.800 229.800 180.200 234.601 ;
        RECT 13.800 195.118 118.800 224.700 ;
        RECT 118.800 229.800 180.200 235.601 ;
        RECT 218.600 77.950 221.500 102.050 ;
        RECT 185.500 77.950 221.500 81.250 ;
        RECT 138.800 90.850 188.700 94.450 ;
        RECT 185.500 77.950 188.700 94.450 ;
        RECT 138.800 143.550 174.950 151.950 ;
        RECT 138.800 90.850 142.100 151.950 ;
        RECT 132.048 229.800 180.200 248.497 ;
        RECT 132.150 229.147 179.547 249.150 ;
        RECT 112.749 228.600 179.000 229.550 ;
        RECT 112.749 228.452 152.150 229.550 ;
        RECT 111.749 227.452 151.150 228.550 ;
        RECT 110.749 226.452 150.150 227.550 ;
        RECT 109.749 225.452 149.150 226.550 ;
        RECT 14.650 224.452 148.150 225.550 ;
        RECT 13.800 223.452 147.150 224.700 ;
        RECT 13.800 222.452 146.150 224.700 ;
        RECT 13.800 221.452 145.150 224.700 ;
        RECT 13.800 220.452 144.150 224.700 ;
        RECT 13.800 219.452 143.150 224.700 ;
        RECT 13.800 218.452 142.150 224.700 ;
        RECT 13.800 217.452 141.150 224.700 ;
        RECT 13.800 216.452 140.150 224.700 ;
        RECT 13.800 215.452 139.150 224.700 ;
        RECT 13.800 214.452 138.150 224.700 ;
        RECT 13.800 213.452 137.150 224.700 ;
        RECT 13.800 212.452 136.150 224.700 ;
        RECT 13.800 211.452 135.150 224.700 ;
        RECT 13.800 210.452 134.150 224.700 ;
        RECT 13.800 209.452 133.150 224.700 ;
        RECT 13.800 208.452 132.150 224.700 ;
        RECT 132.048 229.147 179.547 248.849 ;
        RECT 13.800 208.350 132.048 224.700 ;
        RECT 131.048 229.800 180.200 247.849 ;
        RECT 13.800 207.350 131.048 224.700 ;
        RECT 130.048 229.800 180.200 246.849 ;
        RECT 13.800 206.350 130.048 224.700 ;
        RECT 129.048 229.800 180.200 245.849 ;
        RECT 13.800 205.350 129.048 224.700 ;
        RECT 128.048 229.800 180.200 244.849 ;
        RECT 13.800 204.350 128.048 224.700 ;
        RECT 127.048 229.800 180.200 243.849 ;
        RECT 13.800 203.350 127.048 224.700 ;
        RECT 126.048 229.800 180.200 242.849 ;
        RECT 13.800 202.350 126.048 224.700 ;
        RECT 125.048 229.800 180.200 241.849 ;
        RECT 13.800 201.350 125.048 224.700 ;
        RECT 125.032 229.800 180.200 241.833 ;
        RECT 124.800 229.800 180.200 241.601 ;
        RECT 13.800 201.118 124.800 224.700 ;
        RECT 123.800 229.800 180.200 240.601 ;
        RECT 13.800 200.118 123.800 224.700 ;
        RECT 122.800 229.800 180.200 239.601 ;
        RECT 13.800 199.118 122.800 224.700 ;
        RECT 121.800 229.800 180.200 238.601 ;
        RECT 13.800 198.118 121.800 224.700 ;
        RECT 120.800 229.800 180.200 237.601 ;
        RECT 13.800 197.118 120.800 224.700 ;
        RECT 119.800 229.800 180.200 236.601 ;
        RECT 13.800 196.118 119.800 224.700 ;
    END
  END IN1
  PIN VDD
    DIRECTION INOUT ;
    USE POWER ;
    SHAPE ABUTMENT ;
    PORT
      LAYER metal1 ;
        RECT 161.150 0.000 164.197 233.850 ;
        RECT 0.000 0.000 239.400 90.700 ;
        RECT 192.850 0.000 228.150 91.001 ;
        RECT 224.650 0.000 227.150 201.550 ;
        RECT 192.850 0.000 227.150 94.900 ;
        RECT 192.850 0.000 195.350 202.300 ;
        RECT 182.053 0.000 185.150 233.900 ;
        RECT 182.053 0.000 184.800 234.250 ;
        RECT 181.650 0.000 185.150 233.847 ;
        RECT 170.652 0.000 185.150 108.750 ;
        RECT 170.150 0.000 185.150 108.248 ;
        RECT 161.150 0.000 164.650 233.797 ;
        RECT 161.550 0.000 164.197 234.250 ;
    END
    PORT
      CLASS CORE ;
      LAYER metal1 ;
        RECT 192.850 199.800 213.350 202.300 ;
    END
  END VDD
  OBS 
      LAYER metal2 ;
        RECT 0.850 228.500 106.799 253.250 ;
        RECT 0.850 103.450 135.850 122.600 ;
        RECT 115.948 103.450 135.850 123.402 ;
        RECT 116.750 103.450 135.850 188.168 ;
        RECT 117.750 154.900 148.400 189.168 ;
        RECT 118.750 154.900 148.400 190.168 ;
        RECT 119.750 154.900 148.400 191.168 ;
        RECT 120.750 154.900 148.400 192.168 ;
        RECT 121.750 154.900 148.400 193.168 ;
        RECT 122.750 154.900 148.400 194.168 ;
        RECT 123.750 154.900 148.400 195.168 ;
        RECT 124.750 154.900 148.400 196.168 ;
        RECT 125.750 154.900 148.400 197.168 ;
        RECT 126.750 154.900 148.400 198.168 ;
        RECT 127.750 154.900 148.400 198.400 ;
        RECT 127.998 154.900 148.400 199.400 ;
        RECT 128.998 154.900 148.400 200.400 ;
        RECT 129.998 154.900 148.400 201.400 ;
        RECT 130.998 154.900 148.400 202.400 ;
        RECT 131.998 154.900 148.400 203.400 ;
        RECT 132.998 154.900 148.400 204.400 ;
        RECT 133.998 154.900 148.400 205.400 ;
        RECT 134.998 154.900 148.400 205.502 ;
        RECT 135.100 154.900 148.400 206.502 ;
        RECT 136.100 154.900 148.400 207.502 ;
        RECT 137.100 154.900 148.400 208.502 ;
        RECT 138.100 154.900 148.400 209.502 ;
        RECT 139.100 154.900 148.400 210.502 ;
        RECT 140.100 154.900 148.400 211.502 ;
        RECT 141.100 154.900 148.400 212.502 ;
        RECT 142.100 154.900 148.400 213.502 ;
        RECT 143.100 154.900 148.400 214.502 ;
        RECT 144.100 154.900 148.400 215.502 ;
        RECT 145.100 154.900 148.400 216.502 ;
        RECT 146.100 154.900 148.400 217.502 ;
        RECT 147.100 154.900 148.400 218.502 ;
        RECT 148.100 154.900 148.400 219.502 ;
        RECT 167.600 154.900 178.700 225.650 ;
        RECT 167.600 111.198 167.702 140.600 ;
        RECT 167.600 111.700 178.700 140.600 ;
        RECT 183.150 247.799 183.800 253.250 ;
        RECT 201.050 86.650 203.550 252.050 ;
        RECT 145.050 104.850 167.600 109.550 ;
        RECT 166.150 104.750 215.650 108.300 ;
        RECT 188.350 103.900 215.650 108.300 ;
        RECT 189.350 102.900 215.650 108.300 ;
        RECT 166.150 102.350 168.650 108.950 ;
        RECT 144.000 105.706 168.600 109.000 ;
        RECT 144.000 105.706 148.400 122.597 ;
        RECT 144.453 105.253 148.400 123.050 ;
        RECT 145.050 103.450 148.400 140.600 ;
        RECT 198.300 97.850 215.650 140.600 ;
        RECT 198.300 154.900 221.500 184.400 ;
        RECT 201.000 107.550 221.500 184.400 ;
        RECT 201.000 105.000 220.500 184.900 ;
        RECT 190.650 173.950 214.450 196.850 ;
        RECT 211.750 97.850 214.450 207.800 ;
        RECT 211.750 205.100 224.550 207.800 ;
        RECT 206.300 86.650 208.800 252.050 ;
        RECT 190.650 173.950 208.800 225.650 ;
        RECT 190.650 210.250 224.550 225.650 ;
        RECT 190.650 173.950 195.400 226.950 ;
        RECT 212.400 210.250 214.900 245.400 ;
        RECT 201.000 210.250 209.100 252.050 ;
        RECT 193.900 247.799 224.550 252.050 ;
        RECT 193.900 247.799 203.500 253.250 ;
        RECT 221.850 205.100 224.550 253.250 ;
        RECT 214.500 247.799 224.550 253.250 ;
        RECT 230.150 247.799 238.550 253.250 ;
        RECT 230.150 210.250 238.550 225.650 ;
        RECT 230.100 154.900 238.550 184.900 ;
        RECT 230.100 105.000 238.550 140.600 ;
      LAYER metal1 ;
        RECT 0.750 106.650 149.350 249.448 ;
        RECT 0.750 103.250 148.600 253.450 ;
        RECT 166.150 110.250 179.130 135.394 ;
        RECT 166.150 102.350 168.650 135.394 ;
        RECT 166.157 111.270 180.150 135.413 ;
        RECT 166.238 111.270 180.150 135.448 ;
        RECT 166.238 110.468 179.348 135.532 ;
        RECT 166.956 110.468 179.348 136.250 ;
        RECT 166.750 139.250 178.900 253.450 ;
        RECT 167.400 110.250 178.900 253.450 ;
        RECT 166.150 139.850 178.900 253.450 ;
        RECT 166.150 139.906 179.900 253.450 ;
        RECT 166.150 140.156 180.150 253.450 ;
        RECT 162.300 237.000 184.000 253.450 ;
        RECT 187.900 93.450 190.100 96.450 ;
        RECT 218.650 96.400 221.500 219.450 ;
        RECT 196.850 103.650 223.050 111.100 ;
        RECT 196.850 96.400 199.400 176.450 ;
        RECT 198.100 97.650 221.900 197.300 ;
        RECT 201.800 96.500 216.550 197.300 ;
        RECT 196.900 183.300 223.100 197.300 ;
        RECT 216.300 112.700 223.100 218.700 ;
        RECT 192.900 209.700 221.950 219.450 ;
        RECT 192.900 209.700 220.800 222.400 ;
        RECT 218.650 96.400 220.800 242.900 ;
        RECT 193.700 209.700 220.450 252.250 ;
        RECT 192.900 224.400 200.300 253.450 ;
        RECT 214.300 209.700 220.450 253.450 ;
        RECT 192.900 224.400 195.400 254.250 ;
        RECT 197.150 209.700 200.050 254.650 ;
        RECT 214.900 209.700 218.150 254.700 ;
        RECT 229.950 210.050 238.650 253.450 ;
        RECT 230.900 93.450 238.650 197.050 ;
        RECT 229.900 93.751 238.650 197.050 ;
      LAYER via1 ;
        RECT 0.750 0.750 238.650 304.150 ;
  END 
END IPAD3U

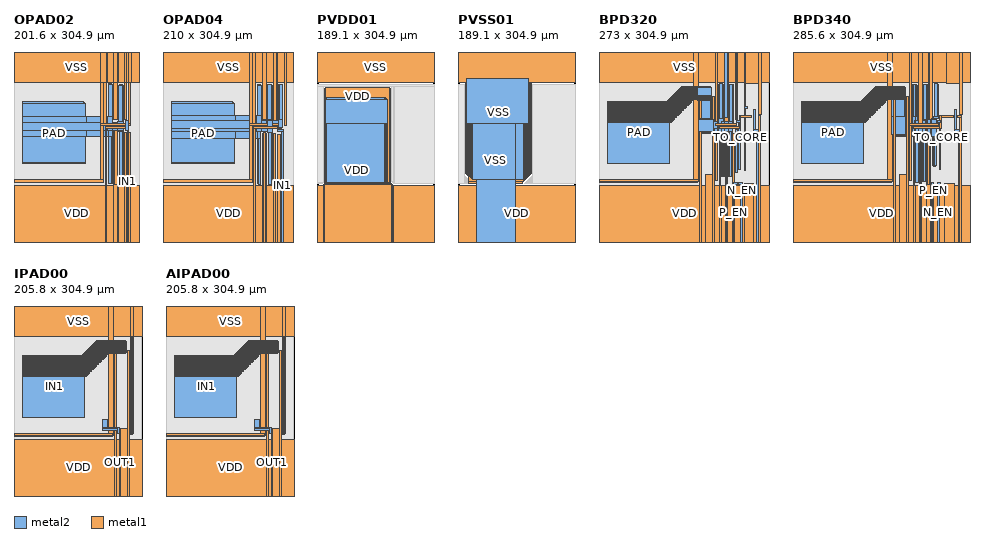
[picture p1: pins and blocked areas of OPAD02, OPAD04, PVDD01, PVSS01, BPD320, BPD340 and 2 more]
MACRO OPAD02
  CLASS  PAD ;
  FOREIGN OPAD02 0.000 0.000 ;
  ORIGIN 0.000 0.000 ;
  SIZE 201.600 BY 304.900 ;
  SYMMETRY X Y R90  ;
  SITE IO ;
  PIN VSS
    DIRECTION INOUT ;
    USE GROUND ;
    SHAPE ABUTMENT ;
    PORT
      LAYER metal2 ;
        RECT 0.000 256.200 201.600 304.900 ;
      LAYER metal1 ;
        RECT 0.750 95.850 143.050 100.500 ;
        RECT 0.000 256.200 201.600 304.900 ;
        RECT 183.450 256.000 188.350 304.900 ;
        RECT 183.450 187.750 187.350 304.900 ;
        RECT 138.950 187.750 187.350 190.350 ;
        RECT 176.795 255.200 180.300 304.900 ;
        RECT 177.250 195.950 180.300 304.900 ;
        RECT 176.800 196.400 180.300 304.900 ;
        RECT 159.246 255.850 167.000 304.900 ;
        RECT 159.246 255.200 166.000 304.900 ;
        RECT 159.450 195.950 166.000 304.900 ;
        RECT 138.500 256.145 149.950 304.900 ;
        RECT 138.500 255.200 148.950 304.900 ;
        RECT 138.950 187.750 148.950 304.900 ;
        RECT 138.950 95.850 143.050 304.900 ;
    END
  END VSS
  PIN IN1
    DIRECTION INPUT ;
    PORT
      LAYER metal2 ;
        RECT 181.450 0.000 183.950 194.400 ;
        RECT 179.400 178.200 183.950 194.400 ;
    END
  END IN1
  PIN PAD
    DIRECTION OUTPUT ;
    PORT
      LAYER metal2 ;
        RECT 168.700 93.003 175.100 250.840 ;
        RECT 169.200 92.400 174.497 251.443 ;
        RECT 168.851 92.749 173.940 252.000 ;
        RECT 168.700 92.900 173.940 251.849 ;
        RECT 167.700 176.899 174.497 250.849 ;
        RECT 167.299 177.300 175.100 193.849 ;
        RECT 166.299 178.300 175.100 192.849 ;
        RECT 166.250 178.300 175.100 192.800 ;
        RECT 13.800 178.300 175.100 191.800 ;
        RECT 151.600 178.300 157.650 252.595 ;
        RECT 151.600 178.300 157.550 252.695 ;
        RECT 152.251 93.700 157.300 252.945 ;
        RECT 152.400 93.100 156.700 253.545 ;
        RECT 152.251 93.249 156.645 253.600 ;
        RECT 151.600 93.900 156.700 252.949 ;
        RECT 150.950 168.946 157.300 252.299 ;
        RECT 150.396 178.300 157.650 201.296 ;
        RECT 13.800 169.500 157.300 200.900 ;
        RECT 13.800 169.500 116.001 201.199 ;
        RECT 13.800 127.652 115.100 221.549 ;
        RECT 13.800 127.550 114.998 221.651 ;
        RECT 13.800 126.550 113.998 222.651 ;
        RECT 14.751 125.550 112.998 223.651 ;
        RECT 13.800 126.501 112.099 224.550 ;
        RECT 14.650 125.651 111.099 225.550 ;
        RECT 13.800 126.501 111.099 224.700 ;
    END
  END PAD
  PIN VDD
    DIRECTION INOUT ;
    USE POWER ;
    SHAPE ABUTMENT ;
    PORT
      LAYER metal1 ;
        RECT 146.100 0.000 149.100 185.400 ;
        RECT 0.000 0.000 201.600 90.700 ;
        RECT 182.200 0.000 187.300 176.300 ;
        RECT 176.950 0.000 180.650 176.200 ;
        RECT 176.799 0.000 180.650 91.700 ;
        RECT 159.150 0.000 167.400 91.377 ;
        RECT 160.751 0.000 166.400 177.296 ;
        RECT 160.751 0.000 165.546 178.150 ;
        RECT 159.850 0.000 166.400 177.249 ;
        RECT 159.150 0.000 166.400 91.700 ;
    END
    PORT
      CLASS CORE ;
      LAYER metal1 ;
        RECT 146.100 182.750 183.300 185.400 ;
    END
  END VDD
  OBS 
      LAYER metal2 ;
        RECT 116.948 224.601 135.550 253.250 ;
        RECT 115.948 225.601 136.000 252.250 ;
        RECT 117.948 224.499 135.550 253.250 ;
        RECT 115.049 226.601 136.000 252.250 ;
        RECT 118.050 204.149 135.550 253.250 ;
        RECT 114.049 227.500 136.000 252.250 ;
        RECT 118.951 203.850 136.000 252.250 ;
        RECT 0.850 228.500 135.550 253.250 ;
        RECT 0.850 103.450 136.000 122.600 ;
        RECT 115.948 103.450 136.000 123.600 ;
        RECT 116.948 103.450 136.000 124.600 ;
        RECT 117.948 103.450 136.000 124.702 ;
        RECT 118.050 103.450 136.000 166.550 ;
        RECT 159.450 204.400 166.000 304.900 ;
        RECT 177.250 197.850 180.100 304.900 ;
      LAYER metal1 ;
        RECT 0.750 103.250 136.200 252.450 ;
        RECT 0.750 103.250 135.750 253.450 ;
        RECT 152.200 93.050 156.548 180.000 ;
        RECT 151.850 93.400 156.548 180.000 ;
        RECT 151.100 94.150 157.036 178.198 ;
        RECT 151.850 94.302 157.800 178.548 ;
        RECT 151.850 93.538 157.036 180.000 ;
        RECT 151.850 179.655 157.179 180.000 ;
        RECT 151.850 179.999 158.001 180.000 ;
        RECT 150.950 193.100 181.900 193.200 ;
        RECT 167.700 193.100 181.900 193.650 ;
        RECT 175.950 191.900 181.900 194.400 ;
        RECT 167.700 192.500 174.400 252.600 ;
        RECT 150.950 192.400 157.650 252.950 ;
        RECT 168.350 192.150 174.400 253.000 ;
        RECT 168.350 191.850 174.100 253.250 ;
        RECT 151.500 191.850 157.650 253.298 ;
        RECT 168.700 191.850 174.100 253.300 ;
        RECT 168.700 191.850 174.045 253.450 ;
        RECT 151.500 191.850 157.048 253.500 ;
        RECT 168.700 191.850 173.800 253.600 ;
        RECT 151.900 191.850 157.048 253.900 ;
        RECT 190.100 193.100 200.850 253.250 ;
        RECT 191.100 193.100 200.850 253.450 ;
        RECT 169.302 93.000 174.500 180.000 ;
        RECT 169.150 93.152 174.500 180.000 ;
        RECT 168.700 93.602 174.900 178.349 ;
        RECT 169.150 93.400 174.900 180.000 ;
        RECT 169.150 178.950 183.950 180.000 ;
        RECT 190.050 93.450 200.850 180.000 ;
        RECT 169.150 179.050 200.850 180.000 ;
        RECT 176.900 178.200 183.950 180.700 ;
      LAYER via1 ;
        RECT 0.750 0.750 200.850 304.150 ;
  END 
END OPAD02

MACRO OPAD04
  CLASS  PAD ;
  FOREIGN OPAD04 0.000 0.000 ;
  ORIGIN 0.000 0.000 ;
  SIZE 210.000 BY 304.900 ;
  SYMMETRY X Y R90  ;
  SITE IO ;
  PIN VSS
    DIRECTION INOUT ;
    USE GROUND ;
    SHAPE ABUTMENT ;
    PORT
      LAYER metal2 ;
        RECT 0.000 256.200 210.000 304.900 ;
      LAYER metal1 ;
        RECT 0.750 95.850 143.050 100.500 ;
        RECT 0.000 256.200 210.000 304.900 ;
        RECT 195.150 187.750 197.650 304.900 ;
        RECT 138.950 187.750 188.900 190.350 ;
        RECT 176.800 196.400 183.300 304.900 ;
        RECT 177.700 196.207 183.300 304.900 ;
        RECT 177.700 195.500 182.593 304.900 ;
        RECT 159.450 196.509 166.000 304.900 ;
        RECT 159.450 196.362 165.441 304.900 ;
        RECT 159.862 195.950 165.441 304.900 ;
        RECT 138.950 187.750 148.950 304.900 ;
        RECT 138.950 95.850 143.050 304.900 ;
    END
  END VSS
  PIN IN1
    DIRECTION INPUT ;
    PORT
      LAYER metal2 ;
        RECT 189.500 0.000 193.650 180.700 ;
        RECT 183.200 177.200 193.650 180.700 ;
    END
  END IN1
  PIN PAD
    DIRECTION OUTPUT ;
    PORT
      LAYER metal2 ;
        RECT 185.700 183.801 192.000 252.050 ;
        RECT 186.180 183.151 191.350 252.700 ;
        RECT 13.800 182.750 190.949 194.800 ;
        RECT 185.700 183.151 191.350 252.220 ;
        RECT 185.049 183.801 192.000 196.350 ;
        RECT 167.546 183.801 192.000 195.350 ;
        RECT 13.800 182.599 176.450 194.800 ;
        RECT 167.546 182.249 176.100 195.700 ;
        RECT 167.700 181.249 175.100 250.965 ;
        RECT 169.250 93.053 175.000 251.065 ;
        RECT 169.250 92.600 174.547 251.518 ;
        RECT 167.700 175.846 174.315 251.750 ;
        RECT 168.351 175.195 173.315 252.750 ;
        RECT 168.700 93.150 175.000 251.065 ;
        RECT 167.700 175.846 173.315 252.099 ;
        RECT 167.546 176.000 175.000 196.047 ;
        RECT 166.546 183.801 192.000 195.047 ;
        RECT 13.800 177.000 175.000 194.800 ;
        RECT 13.800 177.000 158.000 195.350 ;
        RECT 150.950 176.650 157.650 251.896 ;
        RECT 152.500 92.650 157.250 252.296 ;
        RECT 152.500 92.200 156.800 252.746 ;
        RECT 151.612 93.088 156.596 252.950 ;
        RECT 151.600 93.100 156.596 252.938 ;
        RECT 150.950 165.999 157.250 252.288 ;
        RECT 150.149 176.650 157.650 202.903 ;
        RECT 13.800 166.800 157.250 202.550 ;
        RECT 13.800 166.350 115.800 202.550 ;
        RECT 13.800 127.652 115.100 221.549 ;
        RECT 13.800 127.550 114.998 221.651 ;
        RECT 13.800 126.550 113.998 222.651 ;
        RECT 14.751 125.550 112.998 223.651 ;
        RECT 13.800 126.501 112.099 224.550 ;
        RECT 14.650 125.651 111.099 225.550 ;
        RECT 13.800 126.501 111.099 224.700 ;
    END
  END PAD
  PIN VDD
    DIRECTION INOUT ;
    USE POWER ;
    SHAPE ABUTMENT ;
    PORT
      LAYER metal1 ;
        RECT 145.800 0.000 149.100 185.400 ;
        RECT 0.000 0.000 210.000 90.700 ;
        RECT 183.950 0.000 188.300 172.850 ;
        RECT 176.950 0.000 180.650 174.600 ;
        RECT 159.850 0.000 166.400 174.296 ;
        RECT 159.850 0.000 166.246 174.450 ;
        RECT 160.656 0.000 165.246 175.450 ;
        RECT 159.850 0.000 165.246 174.644 ;
    END
    PORT
      CLASS CORE ;
      LAYER metal1 ;
        RECT 145.800 182.750 183.300 185.400 ;
    END
  END VDD
  OBS 
      LAYER metal2 ;
        RECT 115.948 225.601 136.000 253.250 ;
        RECT 116.948 224.601 136.000 253.250 ;
        RECT 115.049 226.601 136.000 253.250 ;
        RECT 117.948 224.499 136.000 253.250 ;
        RECT 114.049 227.500 136.000 253.250 ;
        RECT 118.050 205.500 136.000 253.250 ;
        RECT 0.850 228.500 136.000 253.250 ;
        RECT 0.850 103.450 136.000 122.600 ;
        RECT 115.948 103.450 136.000 123.600 ;
        RECT 116.948 103.450 136.000 124.600 ;
        RECT 117.948 103.450 136.000 124.702 ;
        RECT 118.050 103.450 136.000 163.400 ;
        RECT 118.750 103.450 136.000 163.850 ;
        RECT 159.960 204.400 165.342 304.900 ;
        RECT 159.450 204.910 165.342 304.900 ;
        RECT 177.400 204.400 181.949 304.900 ;
        RECT 177.050 204.750 181.949 304.900 ;
        RECT 177.050 205.400 182.949 304.900 ;
        RECT 159.450 205.058 166.000 304.900 ;
        RECT 177.050 205.651 183.200 304.900 ;
      LAYER metal1 ;
        RECT 0.750 103.250 136.200 253.450 ;
        RECT 150.950 193.100 174.950 193.200 ;
        RECT 168.191 193.100 174.950 193.650 ;
        RECT 168.191 193.100 174.080 193.994 ;
        RECT 168.191 194.800 174.400 252.350 ;
        RECT 167.700 195.002 174.400 252.350 ;
        RECT 168.191 193.100 173.937 252.841 ;
        RECT 151.500 191.850 157.650 252.998 ;
        RECT 150.950 192.400 156.848 253.050 ;
        RECT 168.750 194.450 174.050 253.450 ;
        RECT 151.500 191.850 156.848 253.600 ;
        RECT 151.700 191.850 156.848 253.800 ;
        RECT 200.400 193.100 209.250 253.450 ;
        RECT 169.652 92.350 174.250 180.000 ;
        RECT 151.900 92.450 157.198 180.000 ;
        RECT 151.850 92.500 157.198 180.000 ;
        RECT 151.850 93.052 157.800 180.000 ;
        RECT 168.700 93.302 174.900 180.000 ;
        RECT 169.652 93.000 174.900 180.000 ;
        RECT 167.996 177.200 174.900 180.000 ;
        RECT 151.100 93.250 157.800 178.198 ;
        RECT 151.850 177.394 157.906 180.000 ;
        RECT 167.996 177.350 209.250 180.000 ;
        RECT 191.050 93.450 209.250 180.000 ;
        RECT 151.850 178.200 209.250 180.000 ;
        RECT 183.400 175.600 193.450 180.900 ;
        RECT 176.900 177.350 193.450 180.900 ;
        RECT 190.600 175.600 192.400 253.450 ;
        RECT 187.100 191.900 193.450 194.600 ;
        RECT 185.343 193.100 193.450 193.457 ;
        RECT 191.050 93.450 193.450 194.600 ;
        RECT 185.700 196.952 192.400 252.797 ;
        RECT 186.050 193.100 192.400 253.450 ;
      LAYER via1 ;
        RECT 0.750 0.750 209.250 304.150 ;
  END 
END OPAD04



MACRO PVDD01
  CLASS  PAD ;
  FOREIGN PVDD01 0.000 0.000 ;
  ORIGIN 0.000 0.000 ;
  SIZE 189.100 BY 304.900 ;
  SYMMETRY X Y R90  ;
  SITE IO ;
  PIN VSS
    DIRECTION INOUT ;
    USE GROUND ;
    PORT
      
      LAYER metal1 ;
        RECT 0.000 256.200 189.100 304.900 ;
    END
  END VSS
  PIN VDD
    DIRECTION INPUT ;
    PORT
      LAYER metal2 ;
        RECT 12.900 3.007 110.895 230.079 ;
        RECT 12.900 190.168 113.000 228.189 ;
        RECT 13.700 2.600 112.900 228.444 ;
        RECT 14.500 2.000 112.495 229.044 ;
        RECT 15.300 1.200 111.695 229.844 ;
        RECT 16.271 0.400 110.895 230.644 ;
        RECT 16.271 0.000 110.095 231.250 ;
        RECT 15.300 0.886 109.689 231.850 ;
        RECT 15.471 0.436 108.889 232.250 ;
        RECT 15.300 0.886 108.889 232.200 ;
        RECT 14.500 1.407 109.689 231.679 ;
        RECT 13.700 2.207 110.095 230.879 ;
    END
  END VDD
  PIN VDD
    DIRECTION INOUT ;
    USE POWER ;
    PORT
      LAYER metal2 ;
        RECT 12.900 3.007 110.895 230.079 ;
        RECT 13.700 2.600 112.900 228.444 ;
        RECT 14.500 2.000 112.495 229.044 ;
        RECT 15.300 1.200 111.695 229.844 ;
        RECT 16.271 0.400 110.895 230.644 ;
        RECT 16.271 0.000 110.095 231.250 ;
        RECT 15.300 0.886 109.689 231.850 ;
        RECT 15.471 0.436 108.889 232.250 ;
        RECT 15.300 0.886 108.889 232.200 ;
        RECT 14.500 1.407 109.689 231.679 ;
        RECT 13.700 2.207 110.095 230.879 ;
      LAYER metal1 ;
        RECT 10.149 0.000 122.002 91.100 ;
        RECT 0.000 0.000 189.100 90.700 ;
        RECT 10.949 0.000 122.002 91.102 ;
        RECT 10.949 0.000 121.250 91.852 ;
        RECT 11.749 0.000 120.450 92.652 ;
        RECT 12.500 0.000 119.650 93.452 ;
        RECT 12.500 0.000 118.850 94.252 ;
        RECT 12.500 0.000 118.050 95.052 ;
        RECT 12.500 0.000 117.250 246.200 ;
        RECT 13.300 0.000 116.949 246.750 ;
        RECT 13.511 0.000 116.149 247.150 ;
        RECT 13.300 0.000 116.149 247.050 ;
        RECT 12.500 0.000 116.949 246.539 ;
        RECT 11.749 0.000 119.650 92.701 ;
        RECT 10.949 0.000 120.450 91.900 ;
    END
    PORT
      CLASS CORE ;
      LAYER metal2 ;
        RECT 12.900 190.168 113.000 228.189 ;
    END
  END VDD
  OBS
      LAYER metal2 ;
        RECT 0.850 93.650 7.199 187.218 ;
        RECT 0.850 94.050 7.999 187.218 ;
        RECT 0.850 94.850 8.799 187.218 ;
        RECT 0.850 95.651 9.550 187.218 ;
        RECT 121.800 96.402 188.250 253.250 ;
        RECT 121.000 97.202 188.250 253.250 ;
        RECT 122.600 95.602 188.250 253.250 ;
        RECT 120.200 98.002 188.250 253.250 ;
        RECT 0.850 231.139 9.550 253.250 ;
        RECT 123.400 94.802 188.250 253.250 ;
        RECT 119.899 249.150 188.250 253.250 ;
        RECT 0.850 249.489 10.350 253.250 ;
        RECT 0.850 250.000 10.561 253.250 ;
        RECT 124.200 94.052 188.250 253.250 ;
        RECT 119.099 249.700 188.250 253.250 ;
        RECT 124.952 93.650 188.250 253.250 ;
        RECT 0.850 250.100 188.250 253.250 ;
      LAYER metal1 ;
        RECT 0.750 93.450 7.399 253.450 ;
        RECT 0.750 93.850 8.199 253.450 ;
        RECT 0.750 94.650 8.999 253.450 ;
        RECT 121.600 96.202 188.350 253.450 ;
        RECT 120.800 97.002 188.350 253.450 ;
        RECT 122.400 95.402 188.350 253.450 ;
        RECT 120.000 97.802 188.350 253.450 ;
        RECT 0.750 95.451 9.750 253.450 ;
        RECT 123.200 94.602 188.350 253.450 ;
        RECT 119.699 248.950 188.350 253.450 ;
        RECT 0.750 249.289 10.550 253.450 ;
        RECT 0.750 249.800 10.761 253.450 ;
        RECT 124.000 93.852 188.350 253.450 ;
        RECT 118.899 249.500 188.350 253.450 ;
        RECT 124.752 93.450 188.350 253.450 ;
        RECT 0.750 249.900 188.350 253.450 ;
  END
END PVDD01

MACRO PVSS01
  CLASS  PAD ;
  FOREIGN PVSS01 0.000 0.000 ;
  ORIGIN 0.000 0.000 ;
  SIZE 189.100 BY 304.900 ;
  SYMMETRY X Y R90  ;
  SITE IO ;
  PIN VSS
    DIRECTION INOUT ;
    USE GROUND ;
    PORT
      LAYER metal2 ;
        RECT 0.000 256.200 189.100 304.900 ;
        RECT 12.900 190.168 113.000 304.900 ;
        RECT 12.900 110.860 112.900 304.900 ;
        RECT 15.300 109.200 112.900 304.900 ;
        RECT 15.300 108.550 112.349 304.900 ;
        RECT 15.300 108.460 111.549 304.900 ;
        RECT 16.100 107.750 111.549 304.900 ;
        RECT 16.100 107.660 110.749 304.900 ;
        RECT 16.900 106.950 110.749 304.900 ;
        RECT 16.900 106.860 109.949 304.900 ;
        RECT 17.700 106.150 109.949 304.900 ;
        RECT 17.700 106.060 109.149 304.900 ;
        RECT 18.500 105.350 109.149 304.900 ;
        RECT 18.500 105.260 108.349 304.900 ;
        RECT 19.300 104.550 108.349 304.900 ;
        RECT 19.300 104.460 107.549 304.900 ;
        RECT 20.100 103.750 107.549 304.900 ;
        RECT 20.100 103.660 106.749 304.900 ;
        RECT 20.900 102.950 106.749 304.900 ;
        RECT 20.900 102.860 105.949 304.900 ;
        RECT 21.700 102.150 105.949 304.900 ;
        RECT 21.700 102.060 105.149 304.900 ;
        RECT 22.500 101.350 105.149 304.900 ;
        RECT 22.500 101.260 104.349 304.900 ;
        RECT 23.300 100.950 104.349 304.900 ;
        RECT 23.300 100.650 91.550 304.900 ;
        RECT 30.250 0.000 91.550 304.900 ;
        RECT 23.710 100.450 91.550 304.900 ;
        RECT 13.700 110.060 112.900 304.900 ;
        RECT 14.500 109.260 112.900 304.900 ;
      LAYER metal1 ;
        RECT 0.000 256.200 189.100 304.900 ;
        RECT 12.500 109.350 117.200 304.900 ;
        RECT 12.500 109.150 116.950 304.900 ;
        RECT 13.300 108.850 116.950 304.900 ;
        RECT 13.300 108.350 116.150 304.900 ;
        RECT 14.100 108.050 116.150 304.900 ;
        RECT 14.100 107.550 115.350 304.900 ;
        RECT 14.900 107.250 115.350 304.900 ;
        RECT 14.900 106.750 114.550 304.900 ;
        RECT 15.700 106.450 114.550 304.900 ;
        RECT 15.700 105.950 113.750 304.900 ;
        RECT 16.500 105.650 113.750 304.900 ;
        RECT 16.500 105.150 112.950 304.900 ;
        RECT 17.300 104.850 112.950 304.900 ;
        RECT 17.300 104.550 112.150 304.900 ;
        RECT 17.650 104.050 112.150 304.900 ;
        RECT 17.650 103.250 111.350 304.900 ;
        RECT 17.650 102.450 110.550 304.900 ;
        RECT 17.650 101.650 109.750 304.900 ;
        RECT 17.650 100.850 108.950 304.900 ;
        RECT 17.650 100.050 108.150 304.900 ;
        RECT 17.650 99.250 107.350 304.900 ;
        RECT 17.650 98.450 106.550 304.900 ;
        RECT 17.650 97.650 105.750 304.900 ;
        RECT 17.650 96.850 104.950 304.900 ;
        RECT 17.650 93.700 104.150 304.900 ;
    END
  END VSS
  PIN VSS
    DIRECTION INPUT ;
    PORT
      LAYER metal2 ;
        RECT 14.250 109.510 112.900 261.800 ;
        RECT 13.450 190.168 113.000 261.800 ;
        RECT 12.900 110.960 112.900 261.550 ;
        RECT 15.050 109.200 112.900 261.800 ;
        RECT 15.050 108.710 112.349 261.800 ;
        RECT 15.850 108.550 112.349 261.800 ;
        RECT 15.850 107.910 111.549 261.800 ;
        RECT 16.650 107.750 111.549 261.800 ;
        RECT 16.650 107.110 110.749 261.800 ;
        RECT 17.450 106.950 110.749 261.800 ;
        RECT 17.450 106.310 109.949 261.800 ;
        RECT 18.250 106.150 109.949 261.800 ;
        RECT 18.250 105.510 109.149 261.800 ;
        RECT 19.050 105.350 109.149 261.800 ;
        RECT 19.050 104.710 108.349 261.800 ;
        RECT 19.850 104.550 108.349 261.800 ;
        RECT 19.850 103.910 107.549 261.800 ;
        RECT 20.650 103.750 107.549 261.800 ;
        RECT 20.650 103.110 106.749 261.800 ;
        RECT 21.450 102.950 106.749 261.800 ;
        RECT 21.450 102.310 105.949 261.800 ;
        RECT 22.250 102.150 105.949 261.800 ;
        RECT 22.250 101.510 105.149 261.800 ;
        RECT 23.050 101.350 105.149 261.800 ;
        RECT 23.050 100.950 104.349 261.800 ;
        RECT 23.050 100.750 91.550 261.800 ;
        RECT 30.250 0.000 91.550 261.800 ;
        RECT 23.710 100.450 91.550 261.800 ;
        RECT 13.450 110.310 112.900 261.800 ;
    END
  END VSS
  PIN VDD
    DIRECTION INOUT ;
    USE POWER ;
    PORT
      LAYER metal1 ;
        RECT 0.000 0.000 189.100 90.700 ;
    END
  END VDD
  OBS
      LAYER metal2 ;
        RECT 0.850 93.650 14.700 97.500 ;
        RECT 107.100 93.650 188.250 93.900 ;
        RECT 107.900 93.650 188.250 94.700 ;
        RECT 108.700 93.650 188.250 95.500 ;
        RECT 109.500 93.650 188.250 96.300 ;
        RECT 110.300 93.650 188.250 97.100 ;
        RECT 111.100 93.650 188.250 97.900 ;
        RECT 111.900 93.650 188.250 98.700 ;
        RECT 112.700 93.650 188.250 99.500 ;
        RECT 113.500 93.650 188.250 100.300 ;
        RECT 114.300 93.650 188.250 101.100 ;
        RECT 115.100 93.650 188.250 101.900 ;
        RECT 115.900 93.650 188.250 102.700 ;
        RECT 116.700 93.650 188.250 103.500 ;
        RECT 117.500 93.650 188.250 104.300 ;
        RECT 118.300 93.650 188.250 105.100 ;
        RECT 119.100 93.650 188.250 105.900 ;
        RECT 119.900 93.650 188.250 106.400 ;
        RECT 120.150 93.650 188.250 253.250 ;
      LAYER metal1 ;
        RECT 0.750 93.450 14.900 101.800 ;
        RECT 0.750 93.450 14.550 102.400 ;
        RECT 0.750 93.450 13.750 103.200 ;
        RECT 0.750 93.450 12.950 104.000 ;
        RECT 0.750 93.450 12.150 104.800 ;
        RECT 0.750 93.450 11.350 105.600 ;
        RECT 0.750 93.450 10.550 106.400 ;
        RECT 0.750 93.450 9.750 253.450 ;
        RECT 106.900 93.450 188.350 94.100 ;
        RECT 107.700 93.450 188.350 94.900 ;
        RECT 108.500 93.450 188.350 95.700 ;
        RECT 109.300 93.450 188.350 96.500 ;
        RECT 110.100 93.450 188.350 97.300 ;
        RECT 110.900 93.450 188.350 98.100 ;
        RECT 111.700 93.450 188.350 98.900 ;
        RECT 112.500 93.450 188.350 99.700 ;
        RECT 113.300 93.450 188.350 100.500 ;
        RECT 114.100 93.450 188.350 101.300 ;
        RECT 114.900 93.450 188.350 102.100 ;
        RECT 115.700 93.450 188.350 102.900 ;
        RECT 116.500 93.450 188.350 103.700 ;
        RECT 117.300 93.450 188.350 104.500 ;
        RECT 118.100 93.450 188.350 105.300 ;
        RECT 118.900 93.450 188.350 106.100 ;
        RECT 119.700 93.450 188.350 106.600 ;
        RECT 119.950 93.450 188.350 253.450 ;
  END
END PVSS01
MACRO BPD320
  CLASS  PAD ;
  FOREIGN BPD320 0.000 0.000 ;
  ORIGIN 0.000 0.000 ;
  SIZE 273.000 BY 304.900 ;
  SYMMETRY X Y R90  ;
  SITE IO ;
  PIN N_EN
    DIRECTION INPUT ;
    PORT
      LAYER metal2 ;
        RECT 223.900 116.400 226.500 194.400 ;
        RECT 223.900 92.550 230.150 95.400 ;
        RECT 227.650 0.000 230.150 95.400 ;
        RECT 220.750 191.800 226.500 194.400 ;
    END
  END N_EN
  PIN TO_CORE
    DIRECTION OUTPUT ;
    PORT
      LAYER metal2 ;
        RECT 248.300 177.900 250.800 212.200 ;
        RECT 248.300 177.900 255.350 180.600 ;
        RECT 252.850 0.000 255.350 180.600 ;
    END
  END TO_CORE
  PIN VSS
    DIRECTION INOUT ;
    USE GROUND ;
    SHAPE ABUTMENT ;
    PORT
      LAYER metal2 ;
        RECT 201.901 199.800 206.948 304.900 ;
        RECT 0.000 256.200 273.000 304.900 ;
        RECT 233.000 214.800 237.950 217.300 ;
        RECT 233.000 115.300 235.550 217.300 ;
        RECT 233.000 115.300 235.500 304.900 ;
        RECT 218.250 198.110 221.550 304.900 ;
        RECT 218.510 198.002 221.550 304.900 ;
        RECT 218.510 197.850 221.398 304.900 ;
        RECT 200.900 200.801 207.450 304.900 ;
        RECT 201.900 200.302 207.450 304.900 ;
        RECT 201.900 199.801 206.948 304.900 ;
      LAYER metal1 ;
        RECT 0.750 95.850 158.334 100.500 ;
        RECT 0.000 256.200 273.000 304.900 ;
        RECT 234.350 255.000 260.450 304.900 ;
        RECT 256.650 204.700 260.450 304.900 ;
        RECT 218.250 196.400 221.750 304.900 ;
        RECT 218.700 195.950 221.750 304.900 ;
        RECT 186.750 187.750 220.750 190.350 ;
        RECT 200.900 187.750 207.450 304.900 ;
        RECT 186.750 99.300 190.950 304.900 ;
        RECT 186.850 99.200 190.850 304.900 ;
        RECT 151.350 97.066 159.550 304.900 ;
        RECT 0.750 96.850 159.334 100.500 ;
    END
  END VSS
  PIN PAD
    DIRECTION INOUT ;
    PORT
      LAYER metal2 ;
        RECT 14.751 125.550 112.998 225.550 ;
        RECT 14.650 125.651 112.998 225.550 ;
        RECT 112.998 228.600 180.200 229.799 ;
        RECT 14.650 126.352 113.800 225.550 ;
        RECT 210.101 183.902 215.750 252.148 ;
        RECT 210.101 183.150 214.998 252.900 ;
        RECT 158.950 182.702 214.550 193.000 ;
        RECT 210.101 105.213 213.550 252.900 ;
        RECT 208.450 104.802 212.887 193.900 ;
        RECT 209.150 183.902 215.750 251.949 ;
        RECT 208.702 104.550 212.887 194.152 ;
        RECT 159.950 176.900 213.550 193.000 ;
        RECT 207.550 176.689 213.550 193.000 ;
        RECT 159.950 176.837 202.100 193.000 ;
        RECT 159.950 176.307 201.100 193.000 ;
        RECT 197.100 104.900 201.100 193.000 ;
        RECT 197.650 104.554 200.754 193.000 ;
        RECT 197.650 104.350 200.550 193.204 ;
        RECT 158.950 177.307 200.100 193.654 ;
        RECT 192.400 173.450 199.100 253.050 ;
        RECT 193.002 173.450 198.250 253.900 ;
        RECT 196.499 172.450 201.100 193.000 ;
        RECT 192.400 173.450 198.250 253.298 ;
        RECT 191.700 173.450 199.100 198.200 ;
        RECT 190.700 173.450 199.100 197.200 ;
        RECT 162.807 173.450 199.100 196.200 ;
        RECT 158.950 177.307 183.200 196.452 ;
        RECT 158.950 177.307 182.200 197.452 ;
        RECT 158.950 177.307 181.200 198.452 ;
        RECT 132.150 228.600 179.547 249.150 ;
        RECT 157.950 227.600 180.200 248.497 ;
        RECT 161.950 174.307 179.547 249.150 ;
        RECT 158.950 177.307 180.200 248.497 ;
        RECT 160.950 175.307 179.547 249.150 ;
        RECT 112.749 228.452 152.150 229.550 ;
        RECT 111.749 227.452 151.150 228.550 ;
        RECT 110.749 226.452 150.150 227.550 ;
        RECT 109.749 225.452 149.150 226.550 ;
        RECT 14.650 224.452 148.150 225.550 ;
        RECT 13.800 223.452 147.150 224.700 ;
        RECT 13.800 222.452 146.150 224.700 ;
        RECT 13.800 221.452 145.150 224.700 ;
        RECT 13.800 220.452 144.150 224.700 ;
        RECT 13.800 219.452 143.150 224.700 ;
        RECT 13.800 218.452 142.150 224.700 ;
        RECT 13.800 217.452 141.150 224.700 ;
        RECT 13.800 216.452 140.150 224.700 ;
        RECT 13.800 215.452 139.150 224.700 ;
        RECT 13.800 214.452 138.150 224.700 ;
        RECT 13.800 213.452 137.150 224.700 ;
        RECT 13.800 212.452 136.150 224.700 ;
        RECT 13.800 211.452 135.150 224.700 ;
        RECT 13.800 210.452 134.150 224.700 ;
        RECT 13.800 209.452 133.150 224.700 ;
        RECT 13.800 208.452 132.150 224.700 ;
        RECT 132.048 228.600 179.547 248.849 ;
        RECT 13.800 208.350 132.048 224.700 ;
        RECT 131.048 228.600 180.200 247.849 ;
        RECT 13.800 207.350 131.048 224.700 ;
        RECT 130.048 228.600 180.200 246.849 ;
        RECT 13.800 206.350 130.048 224.700 ;
        RECT 129.048 228.600 180.200 245.849 ;
        RECT 13.800 205.350 129.048 224.700 ;
        RECT 128.048 228.600 180.200 244.849 ;
        RECT 13.800 204.350 128.048 224.700 ;
        RECT 127.048 228.600 180.200 243.849 ;
        RECT 13.800 203.350 127.048 224.700 ;
        RECT 126.048 228.600 180.200 242.849 ;
        RECT 13.800 202.350 126.048 224.700 ;
        RECT 125.048 228.600 180.200 241.849 ;
        RECT 13.800 201.350 125.048 224.700 ;
        RECT 125.032 228.600 180.200 241.833 ;
        RECT 124.800 228.600 180.200 241.601 ;
        RECT 13.800 201.118 124.800 224.700 ;
        RECT 123.800 228.600 180.200 240.601 ;
        RECT 13.800 200.118 123.800 224.700 ;
        RECT 122.800 228.600 180.200 239.601 ;
        RECT 13.800 199.118 122.800 224.700 ;
        RECT 121.800 228.600 180.200 238.601 ;
        RECT 13.800 198.118 121.800 224.700 ;
        RECT 120.800 228.600 180.200 237.601 ;
        RECT 13.800 197.118 120.800 224.700 ;
        RECT 119.800 228.600 180.200 236.601 ;
        RECT 13.800 196.118 119.800 224.700 ;
        RECT 118.800 228.600 180.200 235.601 ;
        RECT 13.800 195.118 118.800 224.700 ;
        RECT 117.800 228.600 180.200 234.601 ;
        RECT 13.800 194.118 117.800 224.700 ;
        RECT 116.800 228.600 180.200 233.601 ;
        RECT 13.800 193.118 116.800 224.700 ;
        RECT 115.800 228.600 180.200 232.601 ;
        RECT 13.800 192.118 115.800 224.700 ;
        RECT 114.800 228.600 180.200 231.601 ;
        RECT 13.800 191.118 114.800 224.700 ;
        RECT 113.800 228.600 180.200 230.601 ;
        RECT 13.800 126.501 113.800 224.700 ;
    END
  END PAD
  PIN VDD
    DIRECTION INOUT ;
    USE POWER ;
    SHAPE ABUTMENT ;
    PORT
      LAYER metal1 ;
        RECT 161.150 0.000 164.197 233.850 ;
        RECT 0.000 0.000 273.000 90.700 ;
        RECT 256.650 0.000 259.550 202.300 ;
        RECT 232.850 0.000 247.600 93.300 ;
        RECT 224.850 199.800 245.200 202.300 ;
        RECT 192.850 182.750 227.350 185.400 ;
        RECT 214.300 0.000 217.750 174.600 ;
        RECT 203.100 0.000 206.650 174.396 ;
        RECT 203.100 0.000 206.596 174.450 ;
        RECT 203.906 0.000 205.596 175.450 ;
        RECT 203.100 0.000 205.596 174.644 ;
        RECT 192.850 0.000 196.350 90.801 ;
        RECT 192.850 0.000 195.350 185.400 ;
        RECT 182.053 0.000 185.150 233.900 ;
        RECT 182.053 0.000 184.800 234.250 ;
        RECT 181.650 0.000 185.150 233.847 ;
        RECT 170.652 0.000 185.150 108.750 ;
        RECT 170.150 0.000 185.150 108.248 ;
        RECT 161.150 0.000 164.650 233.797 ;
        RECT 161.550 0.000 164.197 234.250 ;
    END
    PORT
      CLASS CORE ;
      LAYER metal1 ;
        RECT 224.850 182.750 227.350 202.300 ;
    END
  END VDD
  PIN P_EN
    DIRECTION INPUT ;
    PORT
      LAYER metal2 ;
        RECT 215.050 0.000 217.550 95.350 ;
        RECT 219.350 111.350 222.000 180.800 ;
        RECT 215.050 92.700 221.850 95.350 ;
    END
  END P_EN
  OBS 
      LAYER metal2 ;
        RECT 0.850 228.500 106.799 253.250 ;
        RECT 167.600 111.198 167.702 170.500 ;
        RECT 167.600 111.700 178.700 170.500 ;
        RECT 183.150 237.200 183.800 253.250 ;
        RECT 228.650 173.950 231.300 226.950 ;
        RECT 224.700 205.250 230.050 253.250 ;
        RECT 244.850 148.000 248.150 176.100 ;
        RECT 199.300 93.650 200.150 101.550 ;
        RECT 198.300 93.751 200.150 101.550 ;
        RECT 209.600 93.650 211.350 101.550 ;
        RECT 186.550 98.350 249.900 101.400 ;
        RECT 186.865 97.450 230.416 101.550 ;
        RECT 188.100 93.650 189.900 102.392 ;
        RECT 165.950 102.550 168.950 108.552 ;
        RECT 186.550 97.765 189.650 108.300 ;
        RECT 185.550 98.765 189.650 108.300 ;
        RECT 165.950 104.750 189.650 108.300 ;
        RECT 233.050 86.650 235.550 105.400 ;
        RECT 227.900 98.350 231.350 105.450 ;
        RECT 166.150 102.450 168.950 108.552 ;
        RECT 166.150 102.350 168.850 108.652 ;
        RECT 0.850 104.850 168.650 108.950 ;
        RECT 0.850 104.850 168.600 109.000 ;
        RECT 0.850 104.850 167.600 109.550 ;
        RECT 0.850 104.850 150.800 110.101 ;
        RECT 0.850 104.850 149.800 122.548 ;
        RECT 0.850 103.450 148.400 122.600 ;
        RECT 115.948 104.850 149.298 123.050 ;
        RECT 115.948 103.450 148.400 123.402 ;
        RECT 116.750 103.450 148.400 188.168 ;
        RECT 238.300 86.650 240.800 212.850 ;
        RECT 117.750 103.450 148.400 189.168 ;
        RECT 118.750 103.450 148.400 190.168 ;
        RECT 119.750 103.450 148.400 191.168 ;
        RECT 120.750 103.450 148.400 192.168 ;
        RECT 121.750 103.450 148.400 193.168 ;
        RECT 122.750 103.450 148.400 194.168 ;
        RECT 123.750 103.450 148.400 195.168 ;
        RECT 124.750 103.450 148.400 196.168 ;
        RECT 125.750 103.450 148.400 197.168 ;
        RECT 126.750 103.450 148.400 198.168 ;
        RECT 127.750 103.450 148.400 198.400 ;
        RECT 127.998 103.450 148.400 199.400 ;
        RECT 128.998 103.450 148.400 200.400 ;
        RECT 129.998 103.450 148.400 201.400 ;
        RECT 130.998 103.450 148.400 202.400 ;
        RECT 131.998 103.450 148.400 203.400 ;
        RECT 132.998 103.450 148.400 204.400 ;
        RECT 133.998 103.450 148.400 205.400 ;
        RECT 134.998 103.450 148.400 205.502 ;
        RECT 135.100 103.450 148.400 206.502 ;
        RECT 136.100 103.450 148.400 207.502 ;
        RECT 137.100 103.450 148.400 208.502 ;
        RECT 138.100 103.450 148.400 209.502 ;
        RECT 238.300 188.500 241.750 212.850 ;
        RECT 139.100 103.450 148.400 210.502 ;
        RECT 140.100 103.450 148.400 211.502 ;
        RECT 141.100 103.450 148.400 212.502 ;
        RECT 238.300 210.300 246.550 212.850 ;
        RECT 142.100 103.450 148.400 213.502 ;
        RECT 143.100 103.450 148.400 214.502 ;
        RECT 144.100 103.450 148.400 215.502 ;
        RECT 145.100 103.450 148.400 216.502 ;
        RECT 146.100 103.450 148.400 217.502 ;
        RECT 252.600 195.350 255.300 218.300 ;
        RECT 248.700 215.800 255.300 218.300 ;
        RECT 147.100 103.450 148.400 218.502 ;
        RECT 148.100 103.450 148.400 219.502 ;
        RECT 244.050 210.300 246.550 252.050 ;
        RECT 248.700 215.800 251.200 252.050 ;
        RECT 238.450 220.250 253.700 252.050 ;
        RECT 263.400 220.250 272.150 253.250 ;
        RECT 262.500 98.350 272.150 101.400 ;
      LAYER metal1 ;
        RECT 0.750 106.650 149.350 249.448 ;
        RECT 0.750 103.250 148.600 253.450 ;
        RECT 166.150 110.250 179.130 135.394 ;
        RECT 166.150 102.350 168.650 135.394 ;
        RECT 166.157 111.270 180.150 135.413 ;
        RECT 166.238 111.270 180.150 135.448 ;
        RECT 166.238 110.468 179.348 135.532 ;
        RECT 166.956 110.468 179.348 136.250 ;
        RECT 166.750 139.250 178.900 253.450 ;
        RECT 167.400 110.250 178.900 253.450 ;
        RECT 166.150 139.850 178.900 253.450 ;
        RECT 166.150 139.906 179.900 253.450 ;
        RECT 166.150 140.156 180.150 253.450 ;
        RECT 162.300 237.000 184.000 253.450 ;
        RECT 187.900 93.450 190.100 96.450 ;
        RECT 192.950 191.850 199.100 253.898 ;
        RECT 192.850 191.950 198.398 254.200 ;
        RECT 192.950 191.850 198.398 254.300 ;
        RECT 193.250 191.850 198.398 254.600 ;
        RECT 209.150 193.100 223.350 193.650 ;
        RECT 217.400 191.900 223.350 194.400 ;
        RECT 209.150 192.500 215.850 253.550 ;
        RECT 209.800 192.150 215.850 254.050 ;
        RECT 209.800 191.850 215.550 254.200 ;
        RECT 210.200 191.850 215.550 254.350 ;
        RECT 210.200 191.850 215.300 254.600 ;
        RECT 233.050 189.000 250.550 191.900 ;
        RECT 228.900 183.300 250.800 186.500 ;
        RECT 228.900 183.300 231.500 197.300 ;
        RECT 228.900 194.350 250.800 197.300 ;
        RECT 248.300 194.350 250.800 202.500 ;
        RECT 224.500 248.550 254.300 251.600 ;
        RECT 224.500 205.050 253.900 252.250 ;
        RECT 224.500 205.050 232.050 253.450 ;
        RECT 224.900 205.050 227.400 254.250 ;
        RECT 229.150 205.050 232.050 254.650 ;
        RECT 223.900 92.550 226.800 180.000 ;
        RECT 198.150 93.500 201.048 180.000 ;
        RECT 198.150 93.502 201.050 180.000 ;
        RECT 219.350 93.450 230.100 114.250 ;
        RECT 219.350 92.700 222.300 114.250 ;
        RECT 208.346 177.200 212.150 180.000 ;
        RECT 197.350 177.394 201.156 179.848 ;
        RECT 220.500 96.050 253.900 180.000 ;
        RECT 208.346 177.350 255.100 180.000 ;
        RECT 197.350 93.600 201.050 179.848 ;
        RECT 250.350 93.450 253.900 180.000 ;
        RECT 198.150 178.200 255.100 180.000 ;
        RECT 208.950 93.150 212.150 180.050 ;
        RECT 208.950 93.050 211.800 180.149 ;
        RECT 209.200 92.800 211.800 180.399 ;
        RECT 209.651 92.800 211.800 180.400 ;
        RECT 198.150 92.800 200.348 180.648 ;
        RECT 198.152 92.850 200.398 180.650 ;
        RECT 213.650 177.350 222.000 180.800 ;
        RECT 209.651 92.800 211.350 180.850 ;
        RECT 232.300 96.050 249.800 181.100 ;
        RECT 252.600 112.700 255.100 197.950 ;
        RECT 263.200 205.050 272.250 253.450 ;
        RECT 262.300 93.450 272.250 180.000 ;
      LAYER via1 ;
        RECT 0.750 0.750 272.250 304.150 ;
  END 
END BPD320

MACRO BPD340
  CLASS  PAD ;
  FOREIGN BPD340 0.000 0.000 ;
  ORIGIN 0.000 0.000 ;
  SIZE 285.600 BY 304.900 ;
  SYMMETRY X Y R90  ;
  SITE IO ;
  PIN N_EN
    DIRECTION INPUT ;
    PORT
      LAYER metal2 ;
        RECT 234.650 116.400 237.250 194.400 ;
        RECT 231.850 92.300 237.250 95.150 ;
        RECT 231.850 0.000 234.350 95.150 ;
        RECT 231.750 191.800 237.250 194.400 ;
    END
  END N_EN
  PIN TO_CORE
    DIRECTION OUTPUT ;
    PORT
      LAYER metal2 ;
        RECT 259.300 177.900 261.800 212.200 ;
        RECT 259.300 177.900 267.950 180.600 ;
        RECT 265.450 0.000 267.950 180.600 ;
    END
  END TO_CORE
  PIN VSS
    DIRECTION INOUT ;
    USE GROUND ;
    SHAPE ABUTMENT ;
    PORT
      LAYER metal2 ;
        RECT 0.000 256.200 285.600 304.900 ;
      LAYER metal1 ;
        RECT 0.750 95.850 158.334 100.500 ;
        RECT 0.000 256.200 285.600 304.900 ;
        RECT 245.650 255.000 271.900 304.900 ;
        RECT 267.650 204.700 271.900 304.900 ;
        RECT 186.750 187.750 233.550 190.350 ;
        RECT 217.950 196.400 224.200 304.900 ;
        RECT 218.400 195.950 224.200 304.900 ;
        RECT 200.900 187.750 207.450 304.900 ;
        RECT 186.750 99.300 190.950 304.900 ;
        RECT 186.850 99.200 190.850 304.900 ;
        RECT 151.350 97.066 159.550 304.900 ;
        RECT 0.750 96.850 159.334 100.500 ;
    END
  END VSS
  PIN PAD
    DIRECTION INOUT ;
    PORT
      LAYER metal2 ;
        RECT 226.850 198.739 232.950 252.250 ;
        RECT 227.850 198.389 232.600 252.600 ;
        RECT 227.853 197.389 231.600 253.600 ;
        RECT 222.699 196.739 230.950 197.860 ;
        RECT 221.699 170.900 229.950 196.860 ;
        RECT 227.853 122.592 229.950 253.600 ;
        RECT 224.350 122.357 229.158 199.511 ;
        RECT 227.850 197.389 231.600 253.597 ;
        RECT 226.850 198.389 232.600 252.597 ;
        RECT 225.907 198.739 232.950 201.068 ;
        RECT 224.907 121.800 229.158 200.068 ;
        RECT 223.350 123.357 229.950 198.511 ;
        RECT 222.699 169.900 229.950 197.860 ;
        RECT 221.350 170.900 229.950 196.511 ;
        RECT 209.150 170.900 229.950 196.500 ;
        RECT 210.101 170.900 215.750 252.148 ;
        RECT 210.101 170.900 214.998 252.900 ;
        RECT 160.050 170.849 214.100 195.200 ;
        RECT 160.050 170.800 213.100 195.200 ;
        RECT 210.101 96.813 213.100 252.900 ;
        RECT 208.769 96.450 212.737 196.227 ;
        RECT 209.150 170.900 215.750 251.949 ;
        RECT 208.150 97.069 213.100 195.608 ;
        RECT 207.742 169.805 213.100 195.200 ;
        RECT 160.050 170.301 202.150 195.200 ;
        RECT 196.600 95.850 202.150 195.200 ;
        RECT 192.400 168.950 199.100 251.500 ;
        RECT 192.400 168.950 198.300 252.300 ;
        RECT 192.802 168.950 197.300 253.300 ;
        RECT 194.821 167.950 202.150 195.200 ;
        RECT 195.821 166.950 197.300 253.300 ;
        RECT 192.400 168.950 197.300 252.898 ;
        RECT 191.788 168.950 199.100 200.700 ;
        RECT 161.401 168.950 199.100 199.700 ;
        RECT 158.050 172.301 182.200 200.102 ;
        RECT 158.050 172.301 181.200 201.102 ;
        RECT 132.150 228.600 179.547 249.150 ;
        RECT 158.050 172.301 180.200 248.497 ;
        RECT 161.050 169.301 179.547 249.150 ;
        RECT 159.050 171.301 229.950 195.200 ;
        RECT 112.749 228.452 152.150 229.550 ;
        RECT 111.749 227.452 151.150 228.550 ;
        RECT 110.749 226.452 150.150 227.550 ;
        RECT 109.749 225.452 149.150 226.550 ;
        RECT 14.650 224.452 148.150 225.550 ;
        RECT 13.800 223.452 147.150 224.700 ;
        RECT 13.800 222.452 146.150 224.700 ;
        RECT 13.800 221.452 145.150 224.700 ;
        RECT 13.800 220.452 144.150 224.700 ;
        RECT 13.800 219.452 143.150 224.700 ;
        RECT 13.800 218.452 142.150 224.700 ;
        RECT 13.800 217.452 141.150 224.700 ;
        RECT 13.800 216.452 140.150 224.700 ;
        RECT 13.800 215.452 139.150 224.700 ;
        RECT 13.800 214.452 138.150 224.700 ;
        RECT 13.800 213.452 137.150 224.700 ;
        RECT 13.800 212.452 136.150 224.700 ;
        RECT 13.800 211.452 135.150 224.700 ;
        RECT 13.800 210.452 134.150 224.700 ;
        RECT 13.800 209.452 133.150 224.700 ;
        RECT 13.800 208.452 132.150 224.700 ;
        RECT 132.048 228.600 179.547 248.849 ;
        RECT 13.800 208.350 132.048 224.700 ;
        RECT 131.048 228.600 180.200 247.849 ;
        RECT 13.800 207.350 131.048 224.700 ;
        RECT 130.048 228.600 180.200 246.849 ;
        RECT 13.800 206.350 130.048 224.700 ;
        RECT 129.048 228.600 180.200 245.849 ;
        RECT 13.800 205.350 129.048 224.700 ;
        RECT 128.048 228.600 180.200 244.849 ;
        RECT 13.800 204.350 128.048 224.700 ;
        RECT 127.048 228.600 180.200 243.849 ;
        RECT 13.800 203.350 127.048 224.700 ;
        RECT 126.048 228.600 180.200 242.849 ;
        RECT 13.800 202.350 126.048 224.700 ;
        RECT 125.048 228.600 180.200 241.849 ;
        RECT 13.800 201.350 125.048 224.700 ;
        RECT 125.032 228.600 180.200 241.833 ;
        RECT 124.800 228.600 180.200 241.601 ;
        RECT 13.800 201.118 124.800 224.700 ;
        RECT 123.800 228.600 180.200 240.601 ;
        RECT 13.800 200.118 123.800 224.700 ;
        RECT 122.800 228.600 180.200 239.601 ;
        RECT 13.800 199.118 122.800 224.700 ;
        RECT 121.800 228.600 180.200 238.601 ;
        RECT 13.800 198.118 121.800 224.700 ;
        RECT 120.800 228.600 180.200 237.601 ;
        RECT 13.800 197.118 120.800 224.700 ;
        RECT 119.800 228.600 180.200 236.601 ;
        RECT 13.800 196.118 119.800 224.700 ;
        RECT 118.800 228.600 180.200 235.601 ;
        RECT 13.800 195.118 118.800 224.700 ;
        RECT 117.800 228.600 180.200 234.601 ;
        RECT 13.800 194.118 117.800 224.700 ;
        RECT 116.800 228.600 180.200 233.601 ;
        RECT 13.800 193.118 116.800 224.700 ;
        RECT 115.800 228.600 180.200 232.601 ;
        RECT 13.800 192.118 115.800 224.700 ;
        RECT 114.800 228.600 180.200 231.601 ;
        RECT 13.800 191.118 114.800 224.700 ;
        RECT 113.800 228.600 180.200 230.601 ;
        RECT 13.800 126.501 113.800 224.700 ;
        RECT 14.650 126.352 113.800 225.550 ;
        RECT 112.998 228.600 180.200 229.799 ;
        RECT 14.650 125.651 112.998 225.550 ;
        RECT 14.751 125.550 112.998 225.550 ;
    END
  END PAD
  PIN VDD
    DIRECTION INOUT ;
    USE POWER ;
    SHAPE ABUTMENT ;
    PORT
      LAYER metal1 ;
        RECT 0.000 0.000 285.600 90.700 ;
        RECT 263.750 199.800 270.750 202.300 ;
        RECT 267.650 0.000 270.750 202.300 ;
        RECT 242.800 0.000 258.400 93.450 ;
        RECT 235.850 199.800 257.550 202.300 ;
        RECT 192.850 182.750 238.350 185.400 ;
        RECT 213.992 0.000 221.950 90.701 ;
        RECT 214.300 0.000 220.950 175.600 ;
        RECT 215.300 0.000 220.550 176.000 ;
        RECT 215.451 0.000 219.550 177.000 ;
        RECT 215.300 0.000 219.550 176.849 ;
        RECT 214.300 0.000 220.550 175.849 ;
        RECT 213.992 0.000 220.950 91.700 ;
        RECT 203.100 0.000 206.650 174.396 ;
        RECT 203.100 0.000 206.596 174.450 ;
        RECT 203.906 0.000 205.596 175.450 ;
        RECT 203.100 0.000 205.596 174.644 ;
        RECT 192.850 0.000 196.350 90.701 ;
        RECT 192.850 0.000 195.350 185.400 ;
        RECT 182.053 0.000 185.150 233.900 ;
        RECT 182.053 0.000 184.800 234.250 ;
        RECT 181.650 0.000 185.150 233.847 ;
        RECT 170.652 0.000 185.150 108.750 ;
        RECT 170.150 0.000 185.150 108.248 ;
        RECT 161.150 0.000 164.650 233.797 ;
        RECT 161.550 0.000 164.197 234.250 ;
        RECT 161.150 0.000 164.197 233.850 ;
    END
    PORT
      CLASS CORE ;
      LAYER metal1 ;
        RECT 235.850 182.750 238.350 202.300 ;
    END
  END VDD
  PIN P_EN
    DIRECTION INPUT ;
    PORT
      LAYER metal2 ;
        RECT 223.450 0.000 225.950 96.200 ;
        RECT 222.900 92.800 225.950 96.200 ;
    END
  END P_EN
  OBS 
      LAYER metal2 ;
        RECT 0.850 228.500 106.799 253.250 ;
        RECT 167.600 111.198 167.702 166.000 ;
        RECT 167.600 111.700 178.700 166.000 ;
        RECT 239.650 173.950 242.300 226.950 ;
        RECT 235.900 224.400 242.300 226.950 ;
        RECT 186.356 87.900 218.744 92.800 ;
        RECT 185.450 88.806 189.900 96.250 ;
        RECT 215.250 88.706 219.550 105.500 ;
        RECT 165.950 102.550 168.950 108.552 ;
        RECT 185.450 88.806 189.650 108.300 ;
        RECT 165.950 104.750 189.650 108.300 ;
        RECT 216.200 102.350 242.350 106.450 ;
        RECT 166.150 102.450 168.950 108.552 ;
        RECT 166.150 102.350 168.850 108.652 ;
        RECT 0.850 104.850 168.650 108.950 ;
        RECT 0.850 104.850 168.600 109.000 ;
        RECT 0.850 104.850 167.600 109.550 ;
        RECT 0.850 104.850 150.800 110.101 ;
        RECT 0.850 104.850 149.800 122.548 ;
        RECT 0.850 103.450 148.400 122.600 ;
        RECT 115.948 104.850 149.298 123.050 ;
        RECT 115.948 103.450 148.400 123.402 ;
        RECT 116.750 103.450 148.400 188.168 ;
        RECT 117.750 103.450 148.400 189.168 ;
        RECT 118.750 103.450 148.400 190.168 ;
        RECT 119.750 103.450 148.400 191.168 ;
        RECT 120.750 103.450 148.400 192.168 ;
        RECT 121.750 103.450 148.400 193.168 ;
        RECT 122.750 103.450 148.400 194.168 ;
        RECT 123.750 103.450 148.400 195.168 ;
        RECT 124.750 103.450 148.400 196.168 ;
        RECT 125.750 103.450 148.400 197.168 ;
        RECT 126.750 103.450 148.400 198.168 ;
        RECT 127.750 103.450 148.400 198.400 ;
        RECT 127.998 103.450 148.400 199.400 ;
        RECT 128.998 103.450 148.400 200.400 ;
        RECT 129.998 103.450 148.400 201.400 ;
        RECT 130.998 103.450 148.400 202.400 ;
        RECT 131.998 103.450 148.400 203.400 ;
        RECT 132.998 103.450 148.400 204.400 ;
        RECT 133.998 103.450 148.400 205.400 ;
        RECT 134.998 103.450 148.400 205.502 ;
        RECT 135.100 103.450 148.400 206.502 ;
        RECT 136.100 103.450 148.400 207.502 ;
        RECT 137.100 103.450 148.400 208.502 ;
        RECT 138.100 103.450 148.400 209.502 ;
        RECT 139.100 103.450 148.400 210.502 ;
        RECT 140.100 103.450 148.400 211.502 ;
        RECT 141.100 103.450 148.400 212.502 ;
        RECT 142.100 103.450 148.400 213.502 ;
        RECT 143.100 103.450 148.400 214.502 ;
        RECT 144.100 103.450 148.400 215.502 ;
        RECT 145.100 103.450 148.400 216.502 ;
        RECT 146.100 103.450 148.400 217.502 ;
        RECT 147.100 103.450 148.400 218.502 ;
        RECT 148.100 103.450 148.400 219.502 ;
        RECT 244.050 86.650 246.550 105.400 ;
        RECT 249.600 224.900 252.100 251.600 ;
        RECT 249.300 86.650 251.800 212.850 ;
        RECT 249.300 188.500 252.750 212.850 ;
        RECT 249.300 210.300 257.550 212.850 ;
        RECT 255.050 210.300 257.550 245.650 ;
        RECT 255.050 242.600 258.050 245.650 ;
        RECT 255.850 148.000 259.150 176.100 ;
        RECT 263.600 195.350 266.300 218.300 ;
        RECT 259.700 215.800 266.300 218.300 ;
        RECT 259.700 215.800 262.200 223.200 ;
        RECT 201.850 200.100 207.189 304.900 ;
        RECT 219.054 201.150 222.780 304.900 ;
        RECT 218.400 201.804 222.780 304.900 ;
        RECT 218.400 202.150 223.780 304.900 ;
        RECT 244.000 115.250 246.900 217.500 ;
        RECT 244.000 214.800 248.950 217.500 ;
        RECT 201.850 200.361 207.450 304.900 ;
        RECT 200.900 201.050 207.450 304.900 ;
        RECT 218.400 202.570 224.200 304.900 ;
        RECT 244.000 115.250 246.700 304.900 ;
      LAYER metal1 ;
        RECT 0.750 106.650 149.350 249.448 ;
        RECT 0.750 103.250 148.600 253.450 ;
        RECT 166.150 110.250 179.130 135.394 ;
        RECT 166.150 102.350 168.650 135.394 ;
        RECT 166.157 111.270 180.150 135.413 ;
        RECT 166.238 111.270 180.150 135.448 ;
        RECT 166.238 110.468 179.348 135.532 ;
        RECT 166.956 110.468 179.348 136.250 ;
        RECT 166.750 139.250 178.900 253.450 ;
        RECT 167.400 110.250 178.900 253.450 ;
        RECT 166.150 139.850 178.900 253.450 ;
        RECT 166.150 139.906 179.900 253.450 ;
        RECT 166.150 140.156 180.150 253.450 ;
        RECT 162.300 237.000 184.000 253.450 ;
        RECT 187.900 93.450 190.100 96.450 ;
        RECT 192.950 191.850 199.100 253.898 ;
        RECT 192.850 191.950 198.398 254.200 ;
        RECT 192.950 191.850 198.398 254.300 ;
        RECT 193.250 191.850 198.398 254.600 ;
        RECT 244.050 189.000 261.550 191.900 ;
        RECT 239.900 183.300 261.800 186.500 ;
        RECT 239.900 183.300 242.500 197.300 ;
        RECT 239.900 194.350 261.800 197.300 ;
        RECT 259.300 194.350 261.800 202.500 ;
        RECT 210.200 193.100 234.350 193.200 ;
        RECT 210.200 193.100 215.650 193.650 ;
        RECT 228.400 191.900 234.350 194.400 ;
        RECT 226.950 193.100 233.100 253.450 ;
        RECT 210.200 193.100 215.200 254.600 ;
        RECT 226.850 248.550 265.300 251.600 ;
        RECT 226.850 205.050 264.900 252.250 ;
        RECT 226.850 205.050 243.050 253.450 ;
        RECT 209.150 196.250 215.850 253.550 ;
        RECT 226.850 195.950 232.550 254.000 ;
        RECT 210.150 196.250 215.850 254.050 ;
        RECT 235.900 205.050 238.400 254.250 ;
        RECT 210.150 196.250 215.300 254.550 ;
        RECT 210.200 196.250 215.300 254.600 ;
        RECT 240.150 205.050 243.050 254.650 ;
        RECT 234.300 92.300 237.250 180.000 ;
        RECT 199.100 93.450 200.350 180.650 ;
        RECT 222.900 93.450 240.050 118.950 ;
        RECT 208.950 96.600 212.200 180.000 ;
        RECT 197.350 97.300 201.048 179.848 ;
        RECT 222.900 92.800 226.100 118.950 ;
        RECT 197.350 97.302 201.050 179.848 ;
        RECT 197.350 177.394 201.156 179.848 ;
        RECT 208.346 177.200 212.550 180.000 ;
        RECT 223.300 178.350 266.100 180.000 ;
        RECT 208.950 96.950 212.550 180.000 ;
        RECT 197.350 178.200 212.550 179.848 ;
        RECT 197.350 179.599 212.701 179.848 ;
        RECT 223.700 96.200 264.900 180.000 ;
        RECT 222.300 178.750 266.100 180.000 ;
        RECT 197.350 97.000 200.398 179.848 ;
        RECT 261.150 93.450 264.900 180.000 ;
        RECT 198.100 179.750 266.100 180.000 ;
        RECT 208.950 96.400 212.000 180.149 ;
        RECT 209.400 96.400 212.000 180.200 ;
        RECT 198.100 93.451 200.350 180.598 ;
        RECT 209.400 93.450 211.242 180.599 ;
        RECT 198.152 96.650 200.398 180.650 ;
        RECT 209.651 94.450 211.550 180.650 ;
        RECT 223.450 121.800 230.300 180.800 ;
        RECT 209.651 94.450 211.350 180.850 ;
        RECT 243.300 96.200 260.800 181.100 ;
        RECT 263.600 112.700 266.100 197.950 ;
        RECT 274.650 205.050 284.850 253.450 ;
        RECT 273.500 93.450 284.850 180.000 ;
      LAYER via1 ;
        RECT 0.750 0.750 284.850 304.150 ;
  END 
END BPD340

MACRO IPAD00
  CLASS  PAD ;
  FOREIGN IPAD00 0.000 0.000 ;
  ORIGIN 0.000 0.000 ;
  SIZE 205.800 BY 304.900 ;
  SYMMETRY X Y R90  ;
  SITE IO ;
  PIN OUT1
    DIRECTION OUTPUT ;
    PORT
      LAYER metal2 ;
        RECT 142.800 104.850 149.800 123.050 ;
        RECT 168.850 0.000 171.350 107.850 ;
        RECT 142.800 104.850 170.650 108.550 ;
        RECT 142.800 104.850 169.650 109.550 ;
        RECT 166.150 100.400 171.350 107.850 ;
        RECT 166.400 100.150 169.650 109.550 ;
    END
  END OUT1
  PIN VSS
    DIRECTION INOUT ;
    USE GROUND ;
    SHAPE ABUTMENT ;
    PORT
      LAYER metal2 ;
        RECT 0.000 256.200 205.800 304.900 ;
      LAYER metal1 ;
        RECT 0.750 95.350 157.834 100.500 ;
        RECT 0.000 256.200 205.800 304.900 ;
        RECT 186.894 255.200 192.050 304.900 ;
        RECT 187.700 100.400 192.050 304.900 ;
        RECT 187.700 100.200 191.850 304.900 ;
        RECT 187.700 99.350 190.850 304.900 ;
        RECT 187.850 99.200 190.850 304.900 ;
        RECT 151.350 97.066 159.550 304.900 ;
        RECT 0.750 96.350 158.834 100.500 ;
    END
  END VSS
  PIN IN1
    DIRECTION INPUT ;
    PORT
      LAYER metal2 ;
        RECT 14.751 125.550 112.998 225.550 ;
        RECT 14.650 125.651 112.998 225.550 ;
        RECT 112.998 229.147 179.547 229.799 ;
        RECT 14.650 126.352 113.800 225.550 ;
        RECT 13.800 126.501 113.800 224.700 ;
        RECT 113.800 229.800 180.200 230.601 ;
        RECT 13.800 191.118 114.800 224.700 ;
        RECT 114.800 229.800 180.200 231.601 ;
        RECT 13.800 192.118 115.800 224.700 ;
        RECT 115.800 229.800 180.200 232.601 ;
        RECT 13.800 193.118 116.800 224.700 ;
        RECT 116.800 229.800 180.200 233.601 ;
        RECT 13.800 194.118 117.800 224.700 ;
        RECT 117.800 229.800 180.200 234.601 ;
        RECT 13.800 195.118 118.800 224.700 ;
        RECT 118.800 229.800 180.200 235.601 ;
        RECT 132.048 229.800 180.200 248.497 ;
        RECT 132.150 229.147 179.547 249.150 ;
        RECT 112.749 228.600 179.000 229.550 ;
        RECT 112.749 228.452 152.150 229.550 ;
        RECT 111.749 227.452 151.150 228.550 ;
        RECT 110.749 226.452 150.150 227.550 ;
        RECT 109.749 225.452 149.150 226.550 ;
        RECT 14.650 224.452 148.150 225.550 ;
        RECT 13.800 223.452 147.150 224.700 ;
        RECT 13.800 222.452 146.150 224.700 ;
        RECT 13.800 221.452 145.150 224.700 ;
        RECT 13.800 220.452 144.150 224.700 ;
        RECT 13.800 219.452 143.150 224.700 ;
        RECT 13.800 218.452 142.150 224.700 ;
        RECT 13.800 217.452 141.150 224.700 ;
        RECT 13.800 216.452 140.150 224.700 ;
        RECT 13.800 215.452 139.150 224.700 ;
        RECT 13.800 214.452 138.150 224.700 ;
        RECT 13.800 213.452 137.150 224.700 ;
        RECT 13.800 212.452 136.150 224.700 ;
        RECT 13.800 211.452 135.150 224.700 ;
        RECT 13.800 210.452 134.150 224.700 ;
        RECT 13.800 209.452 133.150 224.700 ;
        RECT 13.800 208.452 132.150 224.700 ;
        RECT 132.048 229.147 179.547 248.849 ;
        RECT 13.800 208.350 132.048 224.700 ;
        RECT 131.048 229.800 180.200 247.849 ;
        RECT 13.800 207.350 131.048 224.700 ;
        RECT 130.048 229.800 180.200 246.849 ;
        RECT 13.800 206.350 130.048 224.700 ;
        RECT 129.048 229.800 180.200 245.849 ;
        RECT 13.800 205.350 129.048 224.700 ;
        RECT 128.048 229.800 180.200 244.849 ;
        RECT 13.800 204.350 128.048 224.700 ;
        RECT 127.048 229.800 180.200 243.849 ;
        RECT 13.800 203.350 127.048 224.700 ;
        RECT 126.048 229.800 180.200 242.849 ;
        RECT 13.800 202.350 126.048 224.700 ;
        RECT 125.048 229.800 180.200 241.849 ;
        RECT 13.800 201.350 125.048 224.700 ;
        RECT 125.032 229.800 180.200 241.833 ;
        RECT 124.800 229.800 180.200 241.601 ;
        RECT 13.800 201.118 124.800 224.700 ;
        RECT 123.800 229.800 180.200 240.601 ;
        RECT 13.800 200.118 123.800 224.700 ;
        RECT 122.800 229.800 180.200 239.601 ;
        RECT 13.800 199.118 122.800 224.700 ;
        RECT 121.800 229.800 180.200 238.601 ;
        RECT 13.800 198.118 121.800 224.700 ;
        RECT 120.800 229.800 180.200 237.601 ;
        RECT 13.800 197.118 120.800 224.700 ;
        RECT 119.800 229.800 180.200 236.601 ;
        RECT 13.800 196.118 119.800 224.700 ;
    END
  END IN1
  PIN VDD
    DIRECTION INOUT ;
    USE POWER ;
    SHAPE ABUTMENT ;
    PORT
      LAYER metal1 ;
        RECT 161.150 0.000 164.197 233.850 ;
        RECT 0.000 0.000 205.800 90.700 ;
        RECT 182.053 0.000 185.150 233.900 ;
        RECT 182.053 0.000 184.800 234.250 ;
        RECT 181.650 0.000 185.150 233.847 ;
        RECT 170.652 0.000 185.150 108.750 ;
        RECT 170.150 0.000 185.150 108.248 ;
        RECT 161.150 0.000 164.650 233.797 ;
        RECT 161.550 0.000 164.197 234.250 ;
    END
  END VDD
  OBS 
      LAYER metal2 ;
        RECT 0.850 228.500 106.799 253.250 ;
        RECT 0.850 229.500 107.799 253.250 ;
        RECT 0.850 230.500 108.799 253.250 ;
        RECT 0.850 231.500 109.799 253.250 ;
        RECT 0.850 232.500 110.048 253.250 ;
        RECT 0.850 232.749 110.850 253.250 ;
        RECT 0.850 233.551 111.850 253.250 ;
        RECT 0.850 234.551 112.850 253.250 ;
        RECT 0.850 235.551 113.850 253.250 ;
        RECT 0.850 236.551 114.850 253.250 ;
        RECT 0.850 237.551 115.850 253.250 ;
        RECT 0.850 238.551 116.850 253.250 ;
        RECT 0.850 239.551 117.850 253.250 ;
        RECT 0.850 240.551 118.850 253.250 ;
        RECT 0.850 241.551 119.850 253.250 ;
        RECT 0.850 242.551 120.850 253.250 ;
        RECT 0.850 243.551 121.850 253.250 ;
        RECT 0.850 244.551 122.082 253.250 ;
        RECT 0.850 244.783 122.098 253.250 ;
        RECT 0.850 244.799 123.098 253.250 ;
        RECT 0.850 245.799 124.098 253.250 ;
        RECT 0.850 246.799 125.098 253.250 ;
        RECT 0.850 247.799 126.098 253.250 ;
        RECT 0.850 248.799 127.098 253.250 ;
        RECT 0.850 249.799 128.098 253.250 ;
        RECT 0.850 250.799 129.098 253.250 ;
        RECT 0.850 251.799 129.200 253.250 ;
        RECT 0.850 252.100 148.400 253.250 ;
        RECT 0.850 103.450 139.850 122.600 ;
        RECT 115.948 103.450 139.850 123.402 ;
        RECT 116.750 103.450 139.850 188.168 ;
        RECT 117.750 126.000 148.400 189.168 ;
        RECT 118.750 126.000 148.400 190.168 ;
        RECT 119.750 126.000 148.400 191.168 ;
        RECT 120.750 126.000 148.400 192.168 ;
        RECT 121.750 126.000 148.400 193.168 ;
        RECT 122.750 126.000 148.400 194.168 ;
        RECT 123.750 126.000 148.400 195.168 ;
        RECT 124.750 126.000 148.400 196.168 ;
        RECT 125.750 126.000 148.400 197.168 ;
        RECT 126.750 126.000 148.400 198.168 ;
        RECT 127.750 126.000 148.400 198.400 ;
        RECT 127.998 126.000 148.400 199.400 ;
        RECT 128.998 126.000 148.400 200.400 ;
        RECT 129.998 126.000 148.400 201.400 ;
        RECT 130.998 126.000 148.400 202.400 ;
        RECT 131.998 126.000 148.400 203.400 ;
        RECT 132.998 126.000 148.400 204.400 ;
        RECT 133.998 126.000 148.400 205.400 ;
        RECT 134.998 126.000 148.400 205.502 ;
        RECT 135.100 126.000 148.400 206.502 ;
        RECT 136.100 126.000 148.400 207.502 ;
        RECT 137.100 126.000 148.400 208.502 ;
        RECT 138.100 126.000 148.400 209.502 ;
        RECT 139.100 126.000 148.400 210.502 ;
        RECT 140.100 126.000 148.400 211.502 ;
        RECT 141.100 126.000 148.400 212.502 ;
        RECT 142.100 126.000 148.400 213.502 ;
        RECT 143.100 126.000 148.400 214.502 ;
        RECT 144.100 126.000 148.400 215.502 ;
        RECT 145.100 126.000 148.400 216.502 ;
        RECT 146.100 126.000 148.400 217.502 ;
        RECT 147.100 126.000 148.400 218.502 ;
        RECT 148.100 126.000 148.400 219.502 ;
        RECT 167.600 126.000 178.700 222.502 ;
        RECT 162.500 252.100 184.750 252.250 ;
        RECT 162.500 252.100 183.944 253.250 ;
        RECT 195.000 252.100 204.950 253.250 ;
        RECT 195.000 126.000 204.950 222.502 ;
        RECT 188.100 93.650 204.950 96.250 ;
        RECT 193.800 93.650 204.950 97.200 ;
      LAYER metal1 ;
        RECT 0.750 106.650 149.350 249.448 ;
        RECT 0.750 103.250 148.600 253.450 ;
        RECT 166.150 110.250 179.130 135.394 ;
        RECT 166.150 102.350 168.650 135.394 ;
        RECT 166.157 111.270 180.150 135.413 ;
        RECT 166.238 111.270 180.150 135.448 ;
        RECT 166.238 110.468 179.348 135.532 ;
        RECT 166.956 110.468 179.348 136.250 ;
        RECT 166.750 139.250 178.900 253.450 ;
        RECT 167.400 110.250 178.900 253.450 ;
        RECT 166.150 139.850 178.900 253.450 ;
        RECT 166.150 139.906 179.900 253.450 ;
        RECT 166.150 140.156 180.150 253.450 ;
        RECT 162.300 237.000 184.950 252.450 ;
        RECT 162.300 237.000 184.144 253.450 ;
        RECT 187.900 93.450 205.050 96.450 ;
        RECT 193.600 93.450 205.050 97.450 ;
        RECT 194.600 93.450 205.050 97.650 ;
        RECT 194.800 93.450 205.050 253.450 ;
      LAYER via ;
        RECT 0.750 0.750 205.050 304.150 ;
  END 
END IPAD00


MACRO AIPAD00
  CLASS  PAD ;
  FOREIGN AIPAD00 0.000 0.000 ;
  ORIGIN 0.000 0.000 ;
  SIZE 205.800 BY 304.900 ;
  SYMMETRY X Y R90  ;
  SITE IO ;
  PIN OUT1
    DIRECTION OUTPUT ;
    PORT
      LAYER metal2 ;
        RECT 142.800 104.850 149.800 123.050 ;
        RECT 168.850 0.000 171.350 107.850 ;
        RECT 142.800 104.850 170.650 108.550 ;
        RECT 142.800 104.850 169.650 109.550 ;
        RECT 166.150 100.400 171.350 107.850 ;
        RECT 166.400 100.150 169.650 109.550 ;
    END
  END OUT1
  PIN VSS
    DIRECTION INOUT ;
    USE GROUND ;
    SHAPE ABUTMENT ;
    PORT
      LAYER metal2 ;
        RECT 0.000 256.200 205.800 304.900 ;
      LAYER metal1 ;
        RECT 0.750 95.350 157.834 100.500 ;
        RECT 0.000 256.200 205.800 304.900 ;
        RECT 186.894 255.200 192.050 304.900 ;
        RECT 187.700 100.400 192.050 304.900 ;
        RECT 187.700 100.200 191.850 304.900 ;
        RECT 187.700 99.350 190.850 304.900 ;
        RECT 187.850 99.200 190.850 304.900 ;
        RECT 151.350 97.066 159.550 304.900 ;
        RECT 0.750 96.350 158.834 100.500 ;
    END
  END VSS
  PIN IN1
    DIRECTION INPUT ;
    PORT
      LAYER metal2 ;
        RECT 14.751 125.550 112.998 225.550 ;
        RECT 14.650 125.651 112.998 225.550 ;
        RECT 112.998 229.147 179.547 229.799 ;
        RECT 14.650 126.352 113.800 225.550 ;
        RECT 13.800 126.501 113.800 224.700 ;
        RECT 113.800 229.800 180.200 230.601 ;
        RECT 13.800 191.118 114.800 224.700 ;
        RECT 114.800 229.800 180.200 231.601 ;
        RECT 13.800 192.118 115.800 224.700 ;
        RECT 115.800 229.800 180.200 232.601 ;
        RECT 13.800 193.118 116.800 224.700 ;
        RECT 116.800 229.800 180.200 233.601 ;
        RECT 13.800 194.118 117.800 224.700 ;
        RECT 117.800 229.800 180.200 234.601 ;
        RECT 13.800 195.118 118.800 224.700 ;
        RECT 118.800 229.800 180.200 235.601 ;
        RECT 132.048 229.800 180.200 248.497 ;
        RECT 132.150 229.147 179.547 249.150 ;
        RECT 112.749 228.600 179.000 229.550 ;
        RECT 112.749 228.452 152.150 229.550 ;
        RECT 111.749 227.452 151.150 228.550 ;
        RECT 110.749 226.452 150.150 227.550 ;
        RECT 109.749 225.452 149.150 226.550 ;
        RECT 14.650 224.452 148.150 225.550 ;
        RECT 13.800 223.452 147.150 224.700 ;
        RECT 13.800 222.452 146.150 224.700 ;
        RECT 13.800 221.452 145.150 224.700 ;
        RECT 13.800 220.452 144.150 224.700 ;
        RECT 13.800 219.452 143.150 224.700 ;
        RECT 13.800 218.452 142.150 224.700 ;
        RECT 13.800 217.452 141.150 224.700 ;
        RECT 13.800 216.452 140.150 224.700 ;
        RECT 13.800 215.452 139.150 224.700 ;
        RECT 13.800 214.452 138.150 224.700 ;
        RECT 13.800 213.452 137.150 224.700 ;
        RECT 13.800 212.452 136.150 224.700 ;
        RECT 13.800 211.452 135.150 224.700 ;
        RECT 13.800 210.452 134.150 224.700 ;
        RECT 13.800 209.452 133.150 224.700 ;
        RECT 13.800 208.452 132.150 224.700 ;
        RECT 132.048 229.147 179.547 248.849 ;
        RECT 13.800 208.350 132.048 224.700 ;
        RECT 131.048 229.800 180.200 247.849 ;
        RECT 13.800 207.350 131.048 224.700 ;
        RECT 130.048 229.800 180.200 246.849 ;
        RECT 13.800 206.350 130.048 224.700 ;
        RECT 129.048 229.800 180.200 245.849 ;
        RECT 13.800 205.350 129.048 224.700 ;
        RECT 128.048 229.800 180.200 244.849 ;
        RECT 13.800 204.350 128.048 224.700 ;
        RECT 127.048 229.800 180.200 243.849 ;
        RECT 13.800 203.350 127.048 224.700 ;
        RECT 126.048 229.800 180.200 242.849 ;
        RECT 13.800 202.350 126.048 224.700 ;
        RECT 125.048 229.800 180.200 241.849 ;
        RECT 13.800 201.350 125.048 224.700 ;
        RECT 125.032 229.800 180.200 241.833 ;
        RECT 124.800 229.800 180.200 241.601 ;
        RECT 13.800 201.118 124.800 224.700 ;
        RECT 123.800 229.800 180.200 240.601 ;
        RECT 13.800 200.118 123.800 224.700 ;
        RECT 122.800 229.800 180.200 239.601 ;
        RECT 13.800 199.118 122.800 224.700 ;
        RECT 121.800 229.800 180.200 238.601 ;
        RECT 13.800 198.118 121.800 224.700 ;
        RECT 120.800 229.800 180.200 237.601 ;
        RECT 13.800 197.118 120.800 224.700 ;
        RECT 119.800 229.800 180.200 236.601 ;
        RECT 13.800 196.118 119.800 224.700 ;
    END
  END IN1
  PIN VDD
    DIRECTION INOUT ;
    USE POWER ;
    SHAPE ABUTMENT ;
    PORT
      LAYER metal1 ;
        RECT 161.150 0.000 164.197 233.850 ;
        RECT 0.000 0.000 205.800 90.700 ;
        RECT 182.053 0.000 185.150 233.900 ;
        RECT 182.053 0.000 184.800 234.250 ;
        RECT 181.650 0.000 185.150 233.847 ;
        RECT 170.652 0.000 185.150 108.750 ;
        RECT 170.150 0.000 185.150 108.248 ;
        RECT 161.150 0.000 164.650 233.797 ;
        RECT 161.550 0.000 164.197 234.250 ;
    END
  END VDD
  OBS 
      LAYER metal2 ;
        RECT 0.850 228.500 106.799 253.250 ;
        RECT 0.850 229.500 107.799 253.250 ;
        RECT 0.850 230.500 108.799 253.250 ;
        RECT 0.850 231.500 109.799 253.250 ;
        RECT 0.850 232.500 110.048 253.250 ;
        RECT 0.850 232.749 110.850 253.250 ;
        RECT 0.850 233.551 111.850 253.250 ;
        RECT 0.850 234.551 112.850 253.250 ;
        RECT 0.850 235.551 113.850 253.250 ;
        RECT 0.850 236.551 114.850 253.250 ;
        RECT 0.850 237.551 115.850 253.250 ;
        RECT 0.850 238.551 116.850 253.250 ;
        RECT 0.850 239.551 117.850 253.250 ;
        RECT 0.850 240.551 118.850 253.250 ;
        RECT 0.850 241.551 119.850 253.250 ;
        RECT 0.850 242.551 120.850 253.250 ;
        RECT 0.850 243.551 121.850 253.250 ;
        RECT 0.850 244.551 122.082 253.250 ;
        RECT 0.850 244.783 122.098 253.250 ;
        RECT 0.850 244.799 123.098 253.250 ;
        RECT 0.850 245.799 124.098 253.250 ;
        RECT 0.850 246.799 125.098 253.250 ;
        RECT 0.850 247.799 126.098 253.250 ;
        RECT 0.850 248.799 127.098 253.250 ;
        RECT 0.850 249.799 128.098 253.250 ;
        RECT 0.850 250.799 129.098 253.250 ;
        RECT 0.850 251.799 129.200 253.250 ;
        RECT 0.850 252.100 148.400 253.250 ;
        RECT 0.850 103.450 139.850 122.600 ;
        RECT 115.948 103.450 139.850 123.402 ;
        RECT 116.750 103.450 139.850 188.168 ;
        RECT 117.750 126.000 148.400 189.168 ;
        RECT 118.750 126.000 148.400 190.168 ;
        RECT 119.750 126.000 148.400 191.168 ;
        RECT 120.750 126.000 148.400 192.168 ;
        RECT 121.750 126.000 148.400 193.168 ;
        RECT 122.750 126.000 148.400 194.168 ;
        RECT 123.750 126.000 148.400 195.168 ;
        RECT 124.750 126.000 148.400 196.168 ;
        RECT 125.750 126.000 148.400 197.168 ;
        RECT 126.750 126.000 148.400 198.168 ;
        RECT 127.750 126.000 148.400 198.400 ;
        RECT 127.998 126.000 148.400 199.400 ;
        RECT 128.998 126.000 148.400 200.400 ;
        RECT 129.998 126.000 148.400 201.400 ;
        RECT 130.998 126.000 148.400 202.400 ;
        RECT 131.998 126.000 148.400 203.400 ;
        RECT 132.998 126.000 148.400 204.400 ;
        RECT 133.998 126.000 148.400 205.400 ;
        RECT 134.998 126.000 148.400 205.502 ;
        RECT 135.100 126.000 148.400 206.502 ;
        RECT 136.100 126.000 148.400 207.502 ;
        RECT 137.100 126.000 148.400 208.502 ;
        RECT 138.100 126.000 148.400 209.502 ;
        RECT 139.100 126.000 148.400 210.502 ;
        RECT 140.100 126.000 148.400 211.502 ;
        RECT 141.100 126.000 148.400 212.502 ;
        RECT 142.100 126.000 148.400 213.502 ;
        RECT 143.100 126.000 148.400 214.502 ;
        RECT 144.100 126.000 148.400 215.502 ;
        RECT 145.100 126.000 148.400 216.502 ;
        RECT 146.100 126.000 148.400 217.502 ;
        RECT 147.100 126.000 148.400 218.502 ;
        RECT 148.100 126.000 148.400 219.502 ;
        RECT 167.600 126.000 178.700 222.502 ;
        RECT 162.500 252.100 184.750 252.250 ;
        RECT 162.500 252.100 183.944 253.250 ;
        RECT 195.000 252.100 204.950 253.250 ;
        RECT 195.000 126.000 204.950 222.502 ;
        RECT 188.100 93.650 204.950 96.250 ;
        RECT 193.800 93.650 204.950 97.200 ;
      LAYER metal1 ;
        RECT 0.750 106.650 149.350 249.448 ;
        RECT 0.750 103.250 148.600 253.450 ;
        RECT 166.150 110.250 179.130 135.394 ;
        RECT 166.150 102.350 168.650 135.394 ;
        RECT 166.157 111.270 180.150 135.413 ;
        RECT 166.238 111.270 180.150 135.448 ;
        RECT 166.238 110.468 179.348 135.532 ;
        RECT 166.956 110.468 179.348 136.250 ;
        RECT 166.750 139.250 178.900 253.450 ;
        RECT 167.400 110.250 178.900 253.450 ;
        RECT 166.150 139.850 178.900 253.450 ;
        RECT 166.150 139.906 179.900 253.450 ;
        RECT 166.150 140.156 180.150 253.450 ;
        RECT 162.300 237.000 184.950 252.450 ;
        RECT 162.300 237.000 184.144 253.450 ;
        RECT 187.900 93.450 205.050 96.450 ;
        RECT 193.600 93.450 205.050 97.450 ;
        RECT 194.600 93.450 205.050 97.650 ;
        RECT 194.800 93.450 205.050 253.450 ;
      LAYER via ;
        RECT 0.750 0.750 205.050 304.150 ;
  END 
END AIPAD00




END LIBRARY
